VERSION 5.8 ;
BUSBITCHARS "[]" ;
DIVIDERCHAR "/" ;
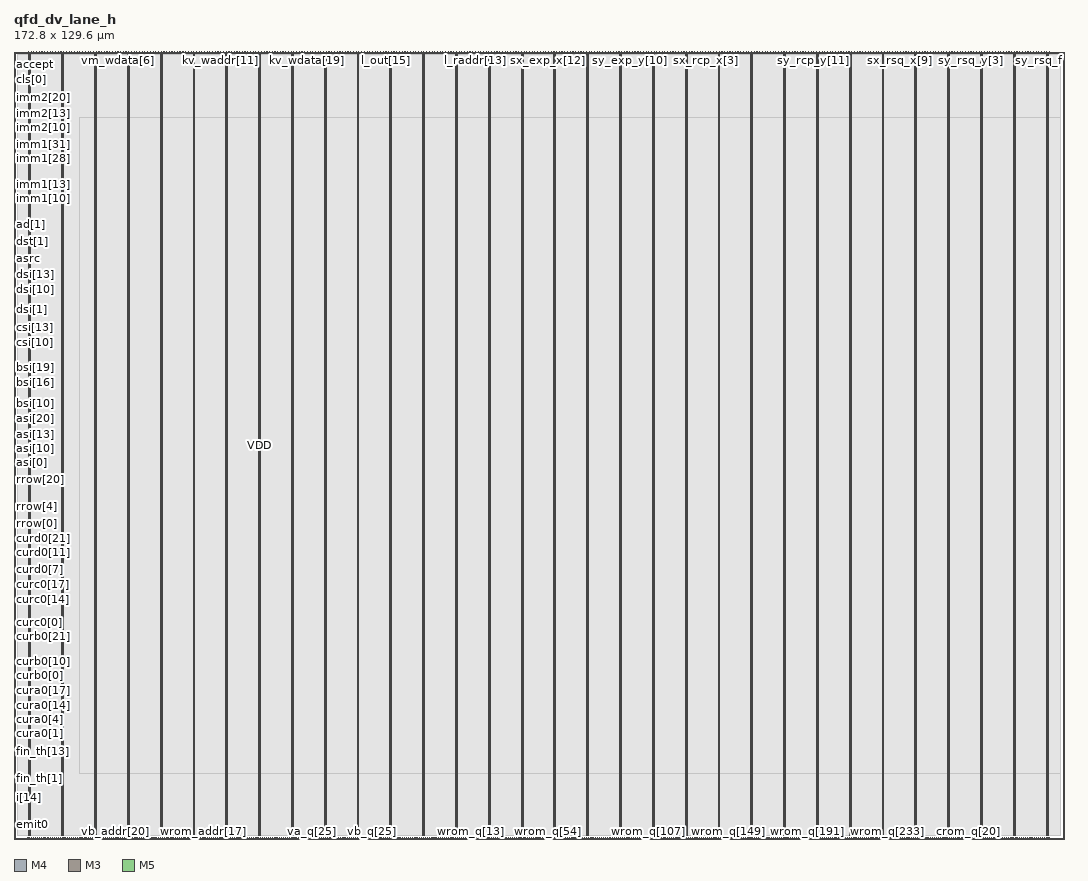
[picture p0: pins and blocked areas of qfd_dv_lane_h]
MACRO qfd_dv_lane_h
  CLASS BLOCK ;
  ORIGIN 0 0 ;
  FOREIGN qfd_dv_lane_h 0 0 ;
  SIZE 172.8 BY 129.6 ;
  SYMMETRY X Y ;
  PIN emit0
    DIRECTION INPUT ;
    USE SIGNAL ;
    PORT
      LAYER M4 ;
        RECT 0.000 2.352 0.192 2.376 ;
    END
  END emit0
  PIN live
    DIRECTION INPUT ;
    USE SIGNAL ;
    PORT
      LAYER M4 ;
        RECT 0.000 2.688 0.192 2.712 ;
    END
  END live
  PIN i[0]
    DIRECTION INPUT ;
    USE SIGNAL ;
    PORT
      LAYER M4 ;
        RECT 0.000 3.072 0.192 3.096 ;
    END
  END i[0]
  PIN i[1]
    DIRECTION INPUT ;
    USE SIGNAL ;
    PORT
      LAYER M4 ;
        RECT 0.000 3.408 0.192 3.432 ;
    END
  END i[1]
  PIN i[2]
    DIRECTION INPUT ;
    USE SIGNAL ;
    PORT
      LAYER M4 ;
        RECT 0.000 3.792 0.192 3.816 ;
    END
  END i[2]
  PIN i[3]
    DIRECTION INPUT ;
    USE SIGNAL ;
    PORT
      LAYER M4 ;
        RECT 0.000 4.128 0.192 4.152 ;
    END
  END i[3]
  PIN i[4]
    DIRECTION INPUT ;
    USE SIGNAL ;
    PORT
      LAYER M4 ;
        RECT 0.000 4.512 0.192 4.536 ;
    END
  END i[4]
  PIN i[5]
    DIRECTION INPUT ;
    USE SIGNAL ;
    PORT
      LAYER M4 ;
        RECT 0.000 4.896 0.192 4.920 ;
    END
  END i[5]
  PIN i[6]
    DIRECTION INPUT ;
    USE SIGNAL ;
    PORT
      LAYER M4 ;
        RECT 0.000 5.232 0.192 5.256 ;
    END
  END i[6]
  PIN i[7]
    DIRECTION INPUT ;
    USE SIGNAL ;
    PORT
      LAYER M4 ;
        RECT 0.000 5.616 0.192 5.640 ;
    END
  END i[7]
  PIN i[8]
    DIRECTION INPUT ;
    USE SIGNAL ;
    PORT
      LAYER M4 ;
        RECT 0.000 5.952 0.192 5.976 ;
    END
  END i[8]
  PIN i[9]
    DIRECTION INPUT ;
    USE SIGNAL ;
    PORT
      LAYER M4 ;
        RECT 0.000 6.336 0.192 6.360 ;
    END
  END i[9]
  PIN i[10]
    DIRECTION INPUT ;
    USE SIGNAL ;
    PORT
      LAYER M4 ;
        RECT 0.000 6.720 0.192 6.744 ;
    END
  END i[10]
  PIN i[11]
    DIRECTION INPUT ;
    USE SIGNAL ;
    PORT
      LAYER M4 ;
        RECT 0.000 7.056 0.192 7.080 ;
    END
  END i[11]
  PIN i[12]
    DIRECTION INPUT ;
    USE SIGNAL ;
    PORT
      LAYER M4 ;
        RECT 0.000 7.440 0.192 7.464 ;
    END
  END i[12]
  PIN i[13]
    DIRECTION INPUT ;
    USE SIGNAL ;
    PORT
      LAYER M4 ;
        RECT 0.000 7.776 0.192 7.800 ;
    END
  END i[13]
  PIN i[14]
    DIRECTION INPUT ;
    USE SIGNAL ;
    PORT
      LAYER M4 ;
        RECT 0.000 8.160 0.192 8.184 ;
    END
  END i[14]
  PIN i[15]
    DIRECTION INPUT ;
    USE SIGNAL ;
    PORT
      LAYER M4 ;
        RECT 0.000 8.544 0.192 8.568 ;
    END
  END i[15]
  PIN i[16]
    DIRECTION INPUT ;
    USE SIGNAL ;
    PORT
      LAYER M4 ;
        RECT 0.000 8.880 0.192 8.904 ;
    END
  END i[16]
  PIN i[17]
    DIRECTION INPUT ;
    USE SIGNAL ;
    PORT
      LAYER M4 ;
        RECT 0.000 9.264 0.192 9.288 ;
    END
  END i[17]
  PIN fin_th[0]
    DIRECTION INPUT ;
    USE SIGNAL ;
    PORT
      LAYER M4 ;
        RECT 0.000 9.600 0.192 9.624 ;
    END
  END fin_th[0]
  PIN fin_th[1]
    DIRECTION INPUT ;
    USE SIGNAL ;
    PORT
      LAYER M4 ;
        RECT 0.000 9.984 0.192 10.008 ;
    END
  END fin_th[1]
  PIN fin_th[2]
    DIRECTION INPUT ;
    USE SIGNAL ;
    PORT
      LAYER M4 ;
        RECT 0.000 10.320 0.192 10.344 ;
    END
  END fin_th[2]
  PIN fin_th[3]
    DIRECTION INPUT ;
    USE SIGNAL ;
    PORT
      LAYER M4 ;
        RECT 0.000 10.704 0.192 10.728 ;
    END
  END fin_th[3]
  PIN fin_th[4]
    DIRECTION INPUT ;
    USE SIGNAL ;
    PORT
      LAYER M4 ;
        RECT 0.000 11.088 0.192 11.112 ;
    END
  END fin_th[4]
  PIN fin_th[5]
    DIRECTION INPUT ;
    USE SIGNAL ;
    PORT
      LAYER M4 ;
        RECT 0.000 11.424 0.192 11.448 ;
    END
  END fin_th[5]
  PIN fin_th[6]
    DIRECTION INPUT ;
    USE SIGNAL ;
    PORT
      LAYER M4 ;
        RECT 0.000 11.808 0.192 11.832 ;
    END
  END fin_th[6]
  PIN fin_th[7]
    DIRECTION INPUT ;
    USE SIGNAL ;
    PORT
      LAYER M4 ;
        RECT 0.000 12.144 0.192 12.168 ;
    END
  END fin_th[7]
  PIN fin_th[8]
    DIRECTION INPUT ;
    USE SIGNAL ;
    PORT
      LAYER M4 ;
        RECT 0.000 12.528 0.192 12.552 ;
    END
  END fin_th[8]
  PIN fin_th[9]
    DIRECTION INPUT ;
    USE SIGNAL ;
    PORT
      LAYER M4 ;
        RECT 0.000 12.912 0.192 12.936 ;
    END
  END fin_th[9]
  PIN fin_th[10]
    DIRECTION INPUT ;
    USE SIGNAL ;
    PORT
      LAYER M4 ;
        RECT 0.000 13.248 0.192 13.272 ;
    END
  END fin_th[10]
  PIN fin_th[11]
    DIRECTION INPUT ;
    USE SIGNAL ;
    PORT
      LAYER M4 ;
        RECT 0.000 13.632 0.192 13.656 ;
    END
  END fin_th[11]
  PIN fin_th[12]
    DIRECTION INPUT ;
    USE SIGNAL ;
    PORT
      LAYER M4 ;
        RECT 0.000 13.968 0.192 13.992 ;
    END
  END fin_th[12]
  PIN fin_th[13]
    DIRECTION INPUT ;
    USE SIGNAL ;
    PORT
      LAYER M4 ;
        RECT 0.000 14.352 0.192 14.376 ;
    END
  END fin_th[13]
  PIN fin_th[14]
    DIRECTION INPUT ;
    USE SIGNAL ;
    PORT
      LAYER M4 ;
        RECT 0.000 14.736 0.192 14.760 ;
    END
  END fin_th[14]
  PIN fin_th[15]
    DIRECTION INPUT ;
    USE SIGNAL ;
    PORT
      LAYER M4 ;
        RECT 0.000 15.072 0.192 15.096 ;
    END
  END fin_th[15]
  PIN fin_th[16]
    DIRECTION INPUT ;
    USE SIGNAL ;
    PORT
      LAYER M4 ;
        RECT 0.000 15.456 0.192 15.480 ;
    END
  END fin_th[16]
  PIN fin_th[17]
    DIRECTION INPUT ;
    USE SIGNAL ;
    PORT
      LAYER M4 ;
        RECT 0.000 15.792 0.192 15.816 ;
    END
  END fin_th[17]
  PIN fin_th[18]
    DIRECTION INPUT ;
    USE SIGNAL ;
    PORT
      LAYER M4 ;
        RECT 0.000 16.176 0.192 16.200 ;
    END
  END fin_th[18]
  PIN i_last_r
    DIRECTION INPUT ;
    USE SIGNAL ;
    PORT
      LAYER M4 ;
        RECT 0.000 16.512 0.192 16.536 ;
    END
  END i_last_r
  PIN cura0[0]
    DIRECTION INPUT ;
    USE SIGNAL ;
    PORT
      LAYER M4 ;
        RECT 0.000 16.896 0.192 16.920 ;
    END
  END cura0[0]
  PIN cura0[1]
    DIRECTION INPUT ;
    USE SIGNAL ;
    PORT
      LAYER M4 ;
        RECT 0.000 17.280 0.192 17.304 ;
    END
  END cura0[1]
  PIN cura0[2]
    DIRECTION INPUT ;
    USE SIGNAL ;
    PORT
      LAYER M4 ;
        RECT 0.000 17.616 0.192 17.640 ;
    END
  END cura0[2]
  PIN cura0[3]
    DIRECTION INPUT ;
    USE SIGNAL ;
    PORT
      LAYER M4 ;
        RECT 0.000 18.000 0.192 18.024 ;
    END
  END cura0[3]
  PIN cura0[4]
    DIRECTION INPUT ;
    USE SIGNAL ;
    PORT
      LAYER M4 ;
        RECT 0.000 18.336 0.192 18.360 ;
    END
  END cura0[4]
  PIN cura0[5]
    DIRECTION INPUT ;
    USE SIGNAL ;
    PORT
      LAYER M4 ;
        RECT 0.000 18.720 0.192 18.744 ;
    END
  END cura0[5]
  PIN cura0[6]
    DIRECTION INPUT ;
    USE SIGNAL ;
    PORT
      LAYER M4 ;
        RECT 0.000 19.104 0.192 19.128 ;
    END
  END cura0[6]
  PIN cura0[7]
    DIRECTION INPUT ;
    USE SIGNAL ;
    PORT
      LAYER M4 ;
        RECT 0.000 19.440 0.192 19.464 ;
    END
  END cura0[7]
  PIN cura0[8]
    DIRECTION INPUT ;
    USE SIGNAL ;
    PORT
      LAYER M4 ;
        RECT 0.000 19.824 0.192 19.848 ;
    END
  END cura0[8]
  PIN cura0[9]
    DIRECTION INPUT ;
    USE SIGNAL ;
    PORT
      LAYER M4 ;
        RECT 0.000 20.160 0.192 20.184 ;
    END
  END cura0[9]
  PIN cura0[10]
    DIRECTION INPUT ;
    USE SIGNAL ;
    PORT
      LAYER M4 ;
        RECT 0.000 20.544 0.192 20.568 ;
    END
  END cura0[10]
  PIN cura0[11]
    DIRECTION INPUT ;
    USE SIGNAL ;
    PORT
      LAYER M4 ;
        RECT 0.000 20.880 0.192 20.904 ;
    END
  END cura0[11]
  PIN cura0[12]
    DIRECTION INPUT ;
    USE SIGNAL ;
    PORT
      LAYER M4 ;
        RECT 0.000 21.264 0.192 21.288 ;
    END
  END cura0[12]
  PIN cura0[13]
    DIRECTION INPUT ;
    USE SIGNAL ;
    PORT
      LAYER M4 ;
        RECT 0.000 21.648 0.192 21.672 ;
    END
  END cura0[13]
  PIN cura0[14]
    DIRECTION INPUT ;
    USE SIGNAL ;
    PORT
      LAYER M4 ;
        RECT 0.000 21.984 0.192 22.008 ;
    END
  END cura0[14]
  PIN cura0[15]
    DIRECTION INPUT ;
    USE SIGNAL ;
    PORT
      LAYER M4 ;
        RECT 0.000 22.368 0.192 22.392 ;
    END
  END cura0[15]
  PIN cura0[16]
    DIRECTION INPUT ;
    USE SIGNAL ;
    PORT
      LAYER M4 ;
        RECT 0.000 22.704 0.192 22.728 ;
    END
  END cura0[16]
  PIN cura0[17]
    DIRECTION INPUT ;
    USE SIGNAL ;
    PORT
      LAYER M4 ;
        RECT 0.000 23.088 0.192 23.112 ;
    END
  END cura0[17]
  PIN cura0[18]
    DIRECTION INPUT ;
    USE SIGNAL ;
    PORT
      LAYER M4 ;
        RECT 0.000 23.472 0.192 23.496 ;
    END
  END cura0[18]
  PIN cura0[19]
    DIRECTION INPUT ;
    USE SIGNAL ;
    PORT
      LAYER M4 ;
        RECT 0.000 23.808 0.192 23.832 ;
    END
  END cura0[19]
  PIN cura0[20]
    DIRECTION INPUT ;
    USE SIGNAL ;
    PORT
      LAYER M4 ;
        RECT 0.000 24.192 0.192 24.216 ;
    END
  END cura0[20]
  PIN cura0[21]
    DIRECTION INPUT ;
    USE SIGNAL ;
    PORT
      LAYER M4 ;
        RECT 0.000 24.528 0.192 24.552 ;
    END
  END cura0[21]
  PIN cura0[22]
    DIRECTION INPUT ;
    USE SIGNAL ;
    PORT
      LAYER M4 ;
        RECT 0.000 24.912 0.192 24.936 ;
    END
  END cura0[22]
  PIN cura0[23]
    DIRECTION INPUT ;
    USE SIGNAL ;
    PORT
      LAYER M4 ;
        RECT 0.000 25.296 0.192 25.320 ;
    END
  END cura0[23]
  PIN curb0[0]
    DIRECTION INPUT ;
    USE SIGNAL ;
    PORT
      LAYER M4 ;
        RECT 0.000 25.632 0.192 25.656 ;
    END
  END curb0[0]
  PIN curb0[1]
    DIRECTION INPUT ;
    USE SIGNAL ;
    PORT
      LAYER M4 ;
        RECT 0.000 26.016 0.192 26.040 ;
    END
  END curb0[1]
  PIN curb0[2]
    DIRECTION INPUT ;
    USE SIGNAL ;
    PORT
      LAYER M4 ;
        RECT 0.000 26.352 0.192 26.376 ;
    END
  END curb0[2]
  PIN curb0[3]
    DIRECTION INPUT ;
    USE SIGNAL ;
    PORT
      LAYER M4 ;
        RECT 0.000 26.736 0.192 26.760 ;
    END
  END curb0[3]
  PIN curb0[4]
    DIRECTION INPUT ;
    USE SIGNAL ;
    PORT
      LAYER M4 ;
        RECT 0.000 27.072 0.192 27.096 ;
    END
  END curb0[4]
  PIN curb0[5]
    DIRECTION INPUT ;
    USE SIGNAL ;
    PORT
      LAYER M4 ;
        RECT 0.000 27.456 0.192 27.480 ;
    END
  END curb0[5]
  PIN curb0[6]
    DIRECTION INPUT ;
    USE SIGNAL ;
    PORT
      LAYER M4 ;
        RECT 0.000 27.840 0.192 27.864 ;
    END
  END curb0[6]
  PIN curb0[7]
    DIRECTION INPUT ;
    USE SIGNAL ;
    PORT
      LAYER M4 ;
        RECT 0.000 28.176 0.192 28.200 ;
    END
  END curb0[7]
  PIN curb0[8]
    DIRECTION INPUT ;
    USE SIGNAL ;
    PORT
      LAYER M4 ;
        RECT 0.000 28.560 0.192 28.584 ;
    END
  END curb0[8]
  PIN curb0[9]
    DIRECTION INPUT ;
    USE SIGNAL ;
    PORT
      LAYER M4 ;
        RECT 0.000 28.896 0.192 28.920 ;
    END
  END curb0[9]
  PIN curb0[10]
    DIRECTION INPUT ;
    USE SIGNAL ;
    PORT
      LAYER M4 ;
        RECT 0.000 29.280 0.192 29.304 ;
    END
  END curb0[10]
  PIN curb0[11]
    DIRECTION INPUT ;
    USE SIGNAL ;
    PORT
      LAYER M4 ;
        RECT 0.000 29.664 0.192 29.688 ;
    END
  END curb0[11]
  PIN curb0[12]
    DIRECTION INPUT ;
    USE SIGNAL ;
    PORT
      LAYER M4 ;
        RECT 0.000 30.000 0.192 30.024 ;
    END
  END curb0[12]
  PIN curb0[13]
    DIRECTION INPUT ;
    USE SIGNAL ;
    PORT
      LAYER M4 ;
        RECT 0.000 30.384 0.192 30.408 ;
    END
  END curb0[13]
  PIN curb0[14]
    DIRECTION INPUT ;
    USE SIGNAL ;
    PORT
      LAYER M4 ;
        RECT 0.000 30.720 0.192 30.744 ;
    END
  END curb0[14]
  PIN curb0[15]
    DIRECTION INPUT ;
    USE SIGNAL ;
    PORT
      LAYER M4 ;
        RECT 0.000 31.104 0.192 31.128 ;
    END
  END curb0[15]
  PIN curb0[16]
    DIRECTION INPUT ;
    USE SIGNAL ;
    PORT
      LAYER M4 ;
        RECT 0.000 31.488 0.192 31.512 ;
    END
  END curb0[16]
  PIN curb0[17]
    DIRECTION INPUT ;
    USE SIGNAL ;
    PORT
      LAYER M4 ;
        RECT 0.000 31.824 0.192 31.848 ;
    END
  END curb0[17]
  PIN curb0[18]
    DIRECTION INPUT ;
    USE SIGNAL ;
    PORT
      LAYER M4 ;
        RECT 0.000 32.208 0.192 32.232 ;
    END
  END curb0[18]
  PIN curb0[19]
    DIRECTION INPUT ;
    USE SIGNAL ;
    PORT
      LAYER M4 ;
        RECT 0.000 32.544 0.192 32.568 ;
    END
  END curb0[19]
  PIN curb0[20]
    DIRECTION INPUT ;
    USE SIGNAL ;
    PORT
      LAYER M4 ;
        RECT 0.000 32.928 0.192 32.952 ;
    END
  END curb0[20]
  PIN curb0[21]
    DIRECTION INPUT ;
    USE SIGNAL ;
    PORT
      LAYER M4 ;
        RECT 0.000 33.264 0.192 33.288 ;
    END
  END curb0[21]
  PIN curb0[22]
    DIRECTION INPUT ;
    USE SIGNAL ;
    PORT
      LAYER M4 ;
        RECT 0.000 33.648 0.192 33.672 ;
    END
  END curb0[22]
  PIN curb0[23]
    DIRECTION INPUT ;
    USE SIGNAL ;
    PORT
      LAYER M4 ;
        RECT 0.000 34.032 0.192 34.056 ;
    END
  END curb0[23]
  PIN curc0[0]
    DIRECTION INPUT ;
    USE SIGNAL ;
    PORT
      LAYER M4 ;
        RECT 0.000 34.368 0.192 34.392 ;
    END
  END curc0[0]
  PIN curc0[1]
    DIRECTION INPUT ;
    USE SIGNAL ;
    PORT
      LAYER M4 ;
        RECT 0.000 34.752 0.192 34.776 ;
    END
  END curc0[1]
  PIN curc0[2]
    DIRECTION INPUT ;
    USE SIGNAL ;
    PORT
      LAYER M4 ;
        RECT 0.000 35.088 0.192 35.112 ;
    END
  END curc0[2]
  PIN curc0[3]
    DIRECTION INPUT ;
    USE SIGNAL ;
    PORT
      LAYER M4 ;
        RECT 0.000 35.472 0.192 35.496 ;
    END
  END curc0[3]
  PIN curc0[4]
    DIRECTION INPUT ;
    USE SIGNAL ;
    PORT
      LAYER M4 ;
        RECT 0.000 35.856 0.192 35.880 ;
    END
  END curc0[4]
  PIN curc0[5]
    DIRECTION INPUT ;
    USE SIGNAL ;
    PORT
      LAYER M4 ;
        RECT 0.000 36.192 0.192 36.216 ;
    END
  END curc0[5]
  PIN curc0[6]
    DIRECTION INPUT ;
    USE SIGNAL ;
    PORT
      LAYER M4 ;
        RECT 0.000 36.576 0.192 36.600 ;
    END
  END curc0[6]
  PIN curc0[7]
    DIRECTION INPUT ;
    USE SIGNAL ;
    PORT
      LAYER M4 ;
        RECT 0.000 36.912 0.192 36.936 ;
    END
  END curc0[7]
  PIN curc0[8]
    DIRECTION INPUT ;
    USE SIGNAL ;
    PORT
      LAYER M4 ;
        RECT 0.000 37.296 0.192 37.320 ;
    END
  END curc0[8]
  PIN curc0[9]
    DIRECTION INPUT ;
    USE SIGNAL ;
    PORT
      LAYER M4 ;
        RECT 0.000 37.680 0.192 37.704 ;
    END
  END curc0[9]
  PIN curc0[10]
    DIRECTION INPUT ;
    USE SIGNAL ;
    PORT
      LAYER M4 ;
        RECT 0.000 38.016 0.192 38.040 ;
    END
  END curc0[10]
  PIN curc0[11]
    DIRECTION INPUT ;
    USE SIGNAL ;
    PORT
      LAYER M4 ;
        RECT 0.000 38.400 0.192 38.424 ;
    END
  END curc0[11]
  PIN curc0[12]
    DIRECTION INPUT ;
    USE SIGNAL ;
    PORT
      LAYER M4 ;
        RECT 0.000 38.736 0.192 38.760 ;
    END
  END curc0[12]
  PIN curc0[13]
    DIRECTION INPUT ;
    USE SIGNAL ;
    PORT
      LAYER M4 ;
        RECT 0.000 39.120 0.192 39.144 ;
    END
  END curc0[13]
  PIN curc0[14]
    DIRECTION INPUT ;
    USE SIGNAL ;
    PORT
      LAYER M4 ;
        RECT 0.000 39.456 0.192 39.480 ;
    END
  END curc0[14]
  PIN curc0[15]
    DIRECTION INPUT ;
    USE SIGNAL ;
    PORT
      LAYER M4 ;
        RECT 0.000 39.840 0.192 39.864 ;
    END
  END curc0[15]
  PIN curc0[16]
    DIRECTION INPUT ;
    USE SIGNAL ;
    PORT
      LAYER M4 ;
        RECT 0.000 40.224 0.192 40.248 ;
    END
  END curc0[16]
  PIN curc0[17]
    DIRECTION INPUT ;
    USE SIGNAL ;
    PORT
      LAYER M4 ;
        RECT 0.000 40.560 0.192 40.584 ;
    END
  END curc0[17]
  PIN curc0[18]
    DIRECTION INPUT ;
    USE SIGNAL ;
    PORT
      LAYER M4 ;
        RECT 0.000 40.944 0.192 40.968 ;
    END
  END curc0[18]
  PIN curc0[19]
    DIRECTION INPUT ;
    USE SIGNAL ;
    PORT
      LAYER M4 ;
        RECT 0.000 41.280 0.192 41.304 ;
    END
  END curc0[19]
  PIN curc0[20]
    DIRECTION INPUT ;
    USE SIGNAL ;
    PORT
      LAYER M4 ;
        RECT 0.000 41.664 0.192 41.688 ;
    END
  END curc0[20]
  PIN curc0[21]
    DIRECTION INPUT ;
    USE SIGNAL ;
    PORT
      LAYER M4 ;
        RECT 0.000 42.048 0.192 42.072 ;
    END
  END curc0[21]
  PIN curc0[22]
    DIRECTION INPUT ;
    USE SIGNAL ;
    PORT
      LAYER M4 ;
        RECT 0.000 42.384 0.192 42.408 ;
    END
  END curc0[22]
  PIN curc0[23]
    DIRECTION INPUT ;
    USE SIGNAL ;
    PORT
      LAYER M4 ;
        RECT 0.000 42.768 0.192 42.792 ;
    END
  END curc0[23]
  PIN curd0[0]
    DIRECTION INPUT ;
    USE SIGNAL ;
    PORT
      LAYER M4 ;
        RECT 0.000 43.104 0.192 43.128 ;
    END
  END curd0[0]
  PIN curd0[1]
    DIRECTION INPUT ;
    USE SIGNAL ;
    PORT
      LAYER M4 ;
        RECT 0.000 43.488 0.192 43.512 ;
    END
  END curd0[1]
  PIN curd0[2]
    DIRECTION INPUT ;
    USE SIGNAL ;
    PORT
      LAYER M4 ;
        RECT 0.000 43.824 0.192 43.848 ;
    END
  END curd0[2]
  PIN curd0[3]
    DIRECTION INPUT ;
    USE SIGNAL ;
    PORT
      LAYER M4 ;
        RECT 0.000 44.208 0.192 44.232 ;
    END
  END curd0[3]
  PIN curd0[4]
    DIRECTION INPUT ;
    USE SIGNAL ;
    PORT
      LAYER M4 ;
        RECT 0.000 44.592 0.192 44.616 ;
    END
  END curd0[4]
  PIN curd0[5]
    DIRECTION INPUT ;
    USE SIGNAL ;
    PORT
      LAYER M4 ;
        RECT 0.000 44.928 0.192 44.952 ;
    END
  END curd0[5]
  PIN curd0[6]
    DIRECTION INPUT ;
    USE SIGNAL ;
    PORT
      LAYER M4 ;
        RECT 0.000 45.312 0.192 45.336 ;
    END
  END curd0[6]
  PIN curd0[7]
    DIRECTION INPUT ;
    USE SIGNAL ;
    PORT
      LAYER M4 ;
        RECT 0.000 45.648 0.192 45.672 ;
    END
  END curd0[7]
  PIN curd0[8]
    DIRECTION INPUT ;
    USE SIGNAL ;
    PORT
      LAYER M4 ;
        RECT 0.000 46.032 0.192 46.056 ;
    END
  END curd0[8]
  PIN curd0[9]
    DIRECTION INPUT ;
    USE SIGNAL ;
    PORT
      LAYER M4 ;
        RECT 0.000 46.416 0.192 46.440 ;
    END
  END curd0[9]
  PIN curd0[10]
    DIRECTION INPUT ;
    USE SIGNAL ;
    PORT
      LAYER M4 ;
        RECT 0.000 46.752 0.192 46.776 ;
    END
  END curd0[10]
  PIN curd0[11]
    DIRECTION INPUT ;
    USE SIGNAL ;
    PORT
      LAYER M4 ;
        RECT 0.000 47.136 0.192 47.160 ;
    END
  END curd0[11]
  PIN curd0[12]
    DIRECTION INPUT ;
    USE SIGNAL ;
    PORT
      LAYER M4 ;
        RECT 0.000 47.472 0.192 47.496 ;
    END
  END curd0[12]
  PIN curd0[13]
    DIRECTION INPUT ;
    USE SIGNAL ;
    PORT
      LAYER M4 ;
        RECT 0.000 47.856 0.192 47.880 ;
    END
  END curd0[13]
  PIN curd0[14]
    DIRECTION INPUT ;
    USE SIGNAL ;
    PORT
      LAYER M4 ;
        RECT 0.000 48.240 0.192 48.264 ;
    END
  END curd0[14]
  PIN curd0[15]
    DIRECTION INPUT ;
    USE SIGNAL ;
    PORT
      LAYER M4 ;
        RECT 0.000 48.576 0.192 48.600 ;
    END
  END curd0[15]
  PIN curd0[16]
    DIRECTION INPUT ;
    USE SIGNAL ;
    PORT
      LAYER M4 ;
        RECT 0.000 48.960 0.192 48.984 ;
    END
  END curd0[16]
  PIN curd0[17]
    DIRECTION INPUT ;
    USE SIGNAL ;
    PORT
      LAYER M4 ;
        RECT 0.000 49.296 0.192 49.320 ;
    END
  END curd0[17]
  PIN curd0[18]
    DIRECTION INPUT ;
    USE SIGNAL ;
    PORT
      LAYER M4 ;
        RECT 0.000 49.680 0.192 49.704 ;
    END
  END curd0[18]
  PIN curd0[19]
    DIRECTION INPUT ;
    USE SIGNAL ;
    PORT
      LAYER M4 ;
        RECT 0.000 50.016 0.192 50.040 ;
    END
  END curd0[19]
  PIN curd0[20]
    DIRECTION INPUT ;
    USE SIGNAL ;
    PORT
      LAYER M4 ;
        RECT 0.000 50.400 0.192 50.424 ;
    END
  END curd0[20]
  PIN curd0[21]
    DIRECTION INPUT ;
    USE SIGNAL ;
    PORT
      LAYER M4 ;
        RECT 0.000 50.784 0.192 50.808 ;
    END
  END curd0[21]
  PIN curd0[22]
    DIRECTION INPUT ;
    USE SIGNAL ;
    PORT
      LAYER M4 ;
        RECT 0.000 51.120 0.192 51.144 ;
    END
  END curd0[22]
  PIN curd0[23]
    DIRECTION INPUT ;
    USE SIGNAL ;
    PORT
      LAYER M4 ;
        RECT 0.000 51.504 0.192 51.528 ;
    END
  END curd0[23]
  PIN rrow[0]
    DIRECTION INPUT ;
    USE SIGNAL ;
    PORT
      LAYER M4 ;
        RECT 0.000 51.840 0.192 51.864 ;
    END
  END rrow[0]
  PIN rrow[1]
    DIRECTION INPUT ;
    USE SIGNAL ;
    PORT
      LAYER M4 ;
        RECT 0.000 52.224 0.192 52.248 ;
    END
  END rrow[1]
  PIN rrow[2]
    DIRECTION INPUT ;
    USE SIGNAL ;
    PORT
      LAYER M4 ;
        RECT 0.000 52.608 0.192 52.632 ;
    END
  END rrow[2]
  PIN rrow[3]
    DIRECTION INPUT ;
    USE SIGNAL ;
    PORT
      LAYER M4 ;
        RECT 0.000 52.944 0.192 52.968 ;
    END
  END rrow[3]
  PIN rrow[4]
    DIRECTION INPUT ;
    USE SIGNAL ;
    PORT
      LAYER M4 ;
        RECT 0.000 53.328 0.192 53.352 ;
    END
  END rrow[4]
  PIN rrow[5]
    DIRECTION INPUT ;
    USE SIGNAL ;
    PORT
      LAYER M4 ;
        RECT 0.000 53.664 0.192 53.688 ;
    END
  END rrow[5]
  PIN rrow[6]
    DIRECTION INPUT ;
    USE SIGNAL ;
    PORT
      LAYER M4 ;
        RECT 0.000 54.048 0.192 54.072 ;
    END
  END rrow[6]
  PIN rrow[7]
    DIRECTION INPUT ;
    USE SIGNAL ;
    PORT
      LAYER M4 ;
        RECT 0.000 54.432 0.192 54.456 ;
    END
  END rrow[7]
  PIN rrow[8]
    DIRECTION INPUT ;
    USE SIGNAL ;
    PORT
      LAYER M4 ;
        RECT 0.000 54.768 0.192 54.792 ;
    END
  END rrow[8]
  PIN rrow[9]
    DIRECTION INPUT ;
    USE SIGNAL ;
    PORT
      LAYER M4 ;
        RECT 0.000 55.152 0.192 55.176 ;
    END
  END rrow[9]
  PIN rrow[10]
    DIRECTION INPUT ;
    USE SIGNAL ;
    PORT
      LAYER M4 ;
        RECT 0.000 55.488 0.192 55.512 ;
    END
  END rrow[10]
  PIN rrow[11]
    DIRECTION INPUT ;
    USE SIGNAL ;
    PORT
      LAYER M4 ;
        RECT 0.000 55.872 0.192 55.896 ;
    END
  END rrow[11]
  PIN rrow[12]
    DIRECTION INPUT ;
    USE SIGNAL ;
    PORT
      LAYER M4 ;
        RECT 0.000 56.208 0.192 56.232 ;
    END
  END rrow[12]
  PIN rrow[13]
    DIRECTION INPUT ;
    USE SIGNAL ;
    PORT
      LAYER M4 ;
        RECT 0.000 56.592 0.192 56.616 ;
    END
  END rrow[13]
  PIN rrow[14]
    DIRECTION INPUT ;
    USE SIGNAL ;
    PORT
      LAYER M4 ;
        RECT 0.000 56.976 0.192 57.000 ;
    END
  END rrow[14]
  PIN rrow[15]
    DIRECTION INPUT ;
    USE SIGNAL ;
    PORT
      LAYER M4 ;
        RECT 0.000 57.312 0.192 57.336 ;
    END
  END rrow[15]
  PIN rrow[16]
    DIRECTION INPUT ;
    USE SIGNAL ;
    PORT
      LAYER M4 ;
        RECT 0.000 57.696 0.192 57.720 ;
    END
  END rrow[16]
  PIN rrow[17]
    DIRECTION INPUT ;
    USE SIGNAL ;
    PORT
      LAYER M4 ;
        RECT 0.000 58.032 0.192 58.056 ;
    END
  END rrow[17]
  PIN rrow[18]
    DIRECTION INPUT ;
    USE SIGNAL ;
    PORT
      LAYER M4 ;
        RECT 0.000 58.416 0.192 58.440 ;
    END
  END rrow[18]
  PIN rrow[19]
    DIRECTION INPUT ;
    USE SIGNAL ;
    PORT
      LAYER M4 ;
        RECT 0.000 58.800 0.192 58.824 ;
    END
  END rrow[19]
  PIN rrow[20]
    DIRECTION INPUT ;
    USE SIGNAL ;
    PORT
      LAYER M4 ;
        RECT 0.000 59.136 0.192 59.160 ;
    END
  END rrow[20]
  PIN rrow[21]
    DIRECTION INPUT ;
    USE SIGNAL ;
    PORT
      LAYER M4 ;
        RECT 0.000 59.520 0.192 59.544 ;
    END
  END rrow[21]
  PIN rrow[22]
    DIRECTION INPUT ;
    USE SIGNAL ;
    PORT
      LAYER M4 ;
        RECT 0.000 59.856 0.192 59.880 ;
    END
  END rrow[22]
  PIN rrow[23]
    DIRECTION INPUT ;
    USE SIGNAL ;
    PORT
      LAYER M4 ;
        RECT 0.000 60.240 0.192 60.264 ;
    END
  END rrow[23]
  PIN asi[0]
    DIRECTION INPUT ;
    USE SIGNAL ;
    PORT
      LAYER M4 ;
        RECT 0.000 60.576 0.192 60.600 ;
    END
  END asi[0]
  PIN asi[1]
    DIRECTION INPUT ;
    USE SIGNAL ;
    PORT
      LAYER M4 ;
        RECT 0.000 60.960 0.192 60.984 ;
    END
  END asi[1]
  PIN asi[2]
    DIRECTION INPUT ;
    USE SIGNAL ;
    PORT
      LAYER M4 ;
        RECT 0.000 61.344 0.192 61.368 ;
    END
  END asi[2]
  PIN asi[3]
    DIRECTION INPUT ;
    USE SIGNAL ;
    PORT
      LAYER M4 ;
        RECT 0.000 61.680 0.192 61.704 ;
    END
  END asi[3]
  PIN asi[4]
    DIRECTION INPUT ;
    USE SIGNAL ;
    PORT
      LAYER M4 ;
        RECT 0.000 62.064 0.192 62.088 ;
    END
  END asi[4]
  PIN asi[5]
    DIRECTION INPUT ;
    USE SIGNAL ;
    PORT
      LAYER M4 ;
        RECT 0.000 62.400 0.192 62.424 ;
    END
  END asi[5]
  PIN asi[6]
    DIRECTION INPUT ;
    USE SIGNAL ;
    PORT
      LAYER M4 ;
        RECT 0.000 62.784 0.192 62.808 ;
    END
  END asi[6]
  PIN asi[7]
    DIRECTION INPUT ;
    USE SIGNAL ;
    PORT
      LAYER M4 ;
        RECT 0.000 63.168 0.192 63.192 ;
    END
  END asi[7]
  PIN asi[8]
    DIRECTION INPUT ;
    USE SIGNAL ;
    PORT
      LAYER M4 ;
        RECT 0.000 63.504 0.192 63.528 ;
    END
  END asi[8]
  PIN asi[9]
    DIRECTION INPUT ;
    USE SIGNAL ;
    PORT
      LAYER M4 ;
        RECT 0.000 63.888 0.192 63.912 ;
    END
  END asi[9]
  PIN asi[10]
    DIRECTION INPUT ;
    USE SIGNAL ;
    PORT
      LAYER M4 ;
        RECT 0.000 64.224 0.192 64.248 ;
    END
  END asi[10]
  PIN asi[11]
    DIRECTION INPUT ;
    USE SIGNAL ;
    PORT
      LAYER M4 ;
        RECT 0.000 64.608 0.192 64.632 ;
    END
  END asi[11]
  PIN asi[12]
    DIRECTION INPUT ;
    USE SIGNAL ;
    PORT
      LAYER M4 ;
        RECT 0.000 64.992 0.192 65.016 ;
    END
  END asi[12]
  PIN asi[13]
    DIRECTION INPUT ;
    USE SIGNAL ;
    PORT
      LAYER M4 ;
        RECT 0.000 65.328 0.192 65.352 ;
    END
  END asi[13]
  PIN asi[14]
    DIRECTION INPUT ;
    USE SIGNAL ;
    PORT
      LAYER M4 ;
        RECT 0.000 65.712 0.192 65.736 ;
    END
  END asi[14]
  PIN asi[15]
    DIRECTION INPUT ;
    USE SIGNAL ;
    PORT
      LAYER M4 ;
        RECT 0.000 66.048 0.192 66.072 ;
    END
  END asi[15]
  PIN asi[16]
    DIRECTION INPUT ;
    USE SIGNAL ;
    PORT
      LAYER M4 ;
        RECT 0.000 66.432 0.192 66.456 ;
    END
  END asi[16]
  PIN asi[17]
    DIRECTION INPUT ;
    USE SIGNAL ;
    PORT
      LAYER M4 ;
        RECT 0.000 66.768 0.192 66.792 ;
    END
  END asi[17]
  PIN asi[18]
    DIRECTION INPUT ;
    USE SIGNAL ;
    PORT
      LAYER M4 ;
        RECT 0.000 67.152 0.192 67.176 ;
    END
  END asi[18]
  PIN asi[19]
    DIRECTION INPUT ;
    USE SIGNAL ;
    PORT
      LAYER M4 ;
        RECT 0.000 67.536 0.192 67.560 ;
    END
  END asi[19]
  PIN asi[20]
    DIRECTION INPUT ;
    USE SIGNAL ;
    PORT
      LAYER M4 ;
        RECT 0.000 67.872 0.192 67.896 ;
    END
  END asi[20]
  PIN asi[21]
    DIRECTION INPUT ;
    USE SIGNAL ;
    PORT
      LAYER M4 ;
        RECT 0.000 68.256 0.192 68.280 ;
    END
  END asi[21]
  PIN asi[22]
    DIRECTION INPUT ;
    USE SIGNAL ;
    PORT
      LAYER M4 ;
        RECT 0.000 68.592 0.192 68.616 ;
    END
  END asi[22]
  PIN asi[23]
    DIRECTION INPUT ;
    USE SIGNAL ;
    PORT
      LAYER M4 ;
        RECT 0.000 68.976 0.192 69.000 ;
    END
  END asi[23]
  PIN bsi[0]
    DIRECTION INPUT ;
    USE SIGNAL ;
    PORT
      LAYER M4 ;
        RECT 0.000 69.360 0.192 69.384 ;
    END
  END bsi[0]
  PIN bsi[1]
    DIRECTION INPUT ;
    USE SIGNAL ;
    PORT
      LAYER M4 ;
        RECT 0.000 69.696 0.192 69.720 ;
    END
  END bsi[1]
  PIN bsi[2]
    DIRECTION INPUT ;
    USE SIGNAL ;
    PORT
      LAYER M4 ;
        RECT 0.000 70.080 0.192 70.104 ;
    END
  END bsi[2]
  PIN bsi[3]
    DIRECTION INPUT ;
    USE SIGNAL ;
    PORT
      LAYER M4 ;
        RECT 0.000 70.416 0.192 70.440 ;
    END
  END bsi[3]
  PIN bsi[4]
    DIRECTION INPUT ;
    USE SIGNAL ;
    PORT
      LAYER M4 ;
        RECT 0.000 70.800 0.192 70.824 ;
    END
  END bsi[4]
  PIN bsi[5]
    DIRECTION INPUT ;
    USE SIGNAL ;
    PORT
      LAYER M4 ;
        RECT 0.000 71.184 0.192 71.208 ;
    END
  END bsi[5]
  PIN bsi[6]
    DIRECTION INPUT ;
    USE SIGNAL ;
    PORT
      LAYER M4 ;
        RECT 0.000 71.520 0.192 71.544 ;
    END
  END bsi[6]
  PIN bsi[7]
    DIRECTION INPUT ;
    USE SIGNAL ;
    PORT
      LAYER M4 ;
        RECT 0.000 71.904 0.192 71.928 ;
    END
  END bsi[7]
  PIN bsi[8]
    DIRECTION INPUT ;
    USE SIGNAL ;
    PORT
      LAYER M4 ;
        RECT 0.000 72.240 0.192 72.264 ;
    END
  END bsi[8]
  PIN bsi[9]
    DIRECTION INPUT ;
    USE SIGNAL ;
    PORT
      LAYER M4 ;
        RECT 0.000 72.624 0.192 72.648 ;
    END
  END bsi[9]
  PIN bsi[10]
    DIRECTION INPUT ;
    USE SIGNAL ;
    PORT
      LAYER M4 ;
        RECT 0.000 72.960 0.192 72.984 ;
    END
  END bsi[10]
  PIN bsi[11]
    DIRECTION INPUT ;
    USE SIGNAL ;
    PORT
      LAYER M4 ;
        RECT 0.000 73.344 0.192 73.368 ;
    END
  END bsi[11]
  PIN bsi[12]
    DIRECTION INPUT ;
    USE SIGNAL ;
    PORT
      LAYER M4 ;
        RECT 0.000 73.728 0.192 73.752 ;
    END
  END bsi[12]
  PIN bsi[13]
    DIRECTION INPUT ;
    USE SIGNAL ;
    PORT
      LAYER M4 ;
        RECT 0.000 74.064 0.192 74.088 ;
    END
  END bsi[13]
  PIN bsi[14]
    DIRECTION INPUT ;
    USE SIGNAL ;
    PORT
      LAYER M4 ;
        RECT 0.000 74.448 0.192 74.472 ;
    END
  END bsi[14]
  PIN bsi[15]
    DIRECTION INPUT ;
    USE SIGNAL ;
    PORT
      LAYER M4 ;
        RECT 0.000 74.784 0.192 74.808 ;
    END
  END bsi[15]
  PIN bsi[16]
    DIRECTION INPUT ;
    USE SIGNAL ;
    PORT
      LAYER M4 ;
        RECT 0.000 75.168 0.192 75.192 ;
    END
  END bsi[16]
  PIN bsi[17]
    DIRECTION INPUT ;
    USE SIGNAL ;
    PORT
      LAYER M4 ;
        RECT 0.000 75.552 0.192 75.576 ;
    END
  END bsi[17]
  PIN bsi[18]
    DIRECTION INPUT ;
    USE SIGNAL ;
    PORT
      LAYER M4 ;
        RECT 0.000 75.888 0.192 75.912 ;
    END
  END bsi[18]
  PIN bsi[19]
    DIRECTION INPUT ;
    USE SIGNAL ;
    PORT
      LAYER M4 ;
        RECT 0.000 76.272 0.192 76.296 ;
    END
  END bsi[19]
  PIN bsi[20]
    DIRECTION INPUT ;
    USE SIGNAL ;
    PORT
      LAYER M4 ;
        RECT 0.000 76.608 0.192 76.632 ;
    END
  END bsi[20]
  PIN bsi[21]
    DIRECTION INPUT ;
    USE SIGNAL ;
    PORT
      LAYER M4 ;
        RECT 0.000 76.992 0.192 77.016 ;
    END
  END bsi[21]
  PIN bsi[22]
    DIRECTION INPUT ;
    USE SIGNAL ;
    PORT
      LAYER M4 ;
        RECT 0.000 77.376 0.192 77.400 ;
    END
  END bsi[22]
  PIN bsi[23]
    DIRECTION INPUT ;
    USE SIGNAL ;
    PORT
      LAYER M4 ;
        RECT 0.000 77.712 0.192 77.736 ;
    END
  END bsi[23]
  PIN csi[0]
    DIRECTION INPUT ;
    USE SIGNAL ;
    PORT
      LAYER M4 ;
        RECT 0.000 78.096 0.192 78.120 ;
    END
  END csi[0]
  PIN csi[1]
    DIRECTION INPUT ;
    USE SIGNAL ;
    PORT
      LAYER M4 ;
        RECT 0.000 78.432 0.192 78.456 ;
    END
  END csi[1]
  PIN csi[2]
    DIRECTION INPUT ;
    USE SIGNAL ;
    PORT
      LAYER M4 ;
        RECT 0.000 78.816 0.192 78.840 ;
    END
  END csi[2]
  PIN csi[3]
    DIRECTION INPUT ;
    USE SIGNAL ;
    PORT
      LAYER M4 ;
        RECT 0.000 79.152 0.192 79.176 ;
    END
  END csi[3]
  PIN csi[4]
    DIRECTION INPUT ;
    USE SIGNAL ;
    PORT
      LAYER M4 ;
        RECT 0.000 79.536 0.192 79.560 ;
    END
  END csi[4]
  PIN csi[5]
    DIRECTION INPUT ;
    USE SIGNAL ;
    PORT
      LAYER M4 ;
        RECT 0.000 79.920 0.192 79.944 ;
    END
  END csi[5]
  PIN csi[6]
    DIRECTION INPUT ;
    USE SIGNAL ;
    PORT
      LAYER M4 ;
        RECT 0.000 80.256 0.192 80.280 ;
    END
  END csi[6]
  PIN csi[7]
    DIRECTION INPUT ;
    USE SIGNAL ;
    PORT
      LAYER M4 ;
        RECT 0.000 80.640 0.192 80.664 ;
    END
  END csi[7]
  PIN csi[8]
    DIRECTION INPUT ;
    USE SIGNAL ;
    PORT
      LAYER M4 ;
        RECT 0.000 80.976 0.192 81.000 ;
    END
  END csi[8]
  PIN csi[9]
    DIRECTION INPUT ;
    USE SIGNAL ;
    PORT
      LAYER M4 ;
        RECT 0.000 81.360 0.192 81.384 ;
    END
  END csi[9]
  PIN csi[10]
    DIRECTION INPUT ;
    USE SIGNAL ;
    PORT
      LAYER M4 ;
        RECT 0.000 81.744 0.192 81.768 ;
    END
  END csi[10]
  PIN csi[11]
    DIRECTION INPUT ;
    USE SIGNAL ;
    PORT
      LAYER M4 ;
        RECT 0.000 82.080 0.192 82.104 ;
    END
  END csi[11]
  PIN csi[12]
    DIRECTION INPUT ;
    USE SIGNAL ;
    PORT
      LAYER M4 ;
        RECT 0.000 82.464 0.192 82.488 ;
    END
  END csi[12]
  PIN csi[13]
    DIRECTION INPUT ;
    USE SIGNAL ;
    PORT
      LAYER M4 ;
        RECT 0.000 82.800 0.192 82.824 ;
    END
  END csi[13]
  PIN csi[14]
    DIRECTION INPUT ;
    USE SIGNAL ;
    PORT
      LAYER M4 ;
        RECT 0.000 83.184 0.192 83.208 ;
    END
  END csi[14]
  PIN csi[15]
    DIRECTION INPUT ;
    USE SIGNAL ;
    PORT
      LAYER M4 ;
        RECT 0.000 83.520 0.192 83.544 ;
    END
  END csi[15]
  PIN csi[16]
    DIRECTION INPUT ;
    USE SIGNAL ;
    PORT
      LAYER M4 ;
        RECT 0.000 83.904 0.192 83.928 ;
    END
  END csi[16]
  PIN csi[17]
    DIRECTION INPUT ;
    USE SIGNAL ;
    PORT
      LAYER M4 ;
        RECT 0.000 84.288 0.192 84.312 ;
    END
  END csi[17]
  PIN csi[18]
    DIRECTION INPUT ;
    USE SIGNAL ;
    PORT
      LAYER M4 ;
        RECT 0.000 84.624 0.192 84.648 ;
    END
  END csi[18]
  PIN csi[19]
    DIRECTION INPUT ;
    USE SIGNAL ;
    PORT
      LAYER M4 ;
        RECT 0.000 85.008 0.192 85.032 ;
    END
  END csi[19]
  PIN csi[20]
    DIRECTION INPUT ;
    USE SIGNAL ;
    PORT
      LAYER M4 ;
        RECT 0.000 85.344 0.192 85.368 ;
    END
  END csi[20]
  PIN csi[21]
    DIRECTION INPUT ;
    USE SIGNAL ;
    PORT
      LAYER M4 ;
        RECT 0.000 85.728 0.192 85.752 ;
    END
  END csi[21]
  PIN csi[22]
    DIRECTION INPUT ;
    USE SIGNAL ;
    PORT
      LAYER M4 ;
        RECT 0.000 86.112 0.192 86.136 ;
    END
  END csi[22]
  PIN csi[23]
    DIRECTION INPUT ;
    USE SIGNAL ;
    PORT
      LAYER M4 ;
        RECT 0.000 86.448 0.192 86.472 ;
    END
  END csi[23]
  PIN dsi[0]
    DIRECTION INPUT ;
    USE SIGNAL ;
    PORT
      LAYER M4 ;
        RECT 0.000 86.832 0.192 86.856 ;
    END
  END dsi[0]
  PIN dsi[1]
    DIRECTION INPUT ;
    USE SIGNAL ;
    PORT
      LAYER M4 ;
        RECT 0.000 87.168 0.192 87.192 ;
    END
  END dsi[1]
  PIN dsi[2]
    DIRECTION INPUT ;
    USE SIGNAL ;
    PORT
      LAYER M4 ;
        RECT 0.000 87.552 0.192 87.576 ;
    END
  END dsi[2]
  PIN dsi[3]
    DIRECTION INPUT ;
    USE SIGNAL ;
    PORT
      LAYER M4 ;
        RECT 0.000 87.936 0.192 87.960 ;
    END
  END dsi[3]
  PIN dsi[4]
    DIRECTION INPUT ;
    USE SIGNAL ;
    PORT
      LAYER M4 ;
        RECT 0.000 88.272 0.192 88.296 ;
    END
  END dsi[4]
  PIN dsi[5]
    DIRECTION INPUT ;
    USE SIGNAL ;
    PORT
      LAYER M4 ;
        RECT 0.000 88.656 0.192 88.680 ;
    END
  END dsi[5]
  PIN dsi[6]
    DIRECTION INPUT ;
    USE SIGNAL ;
    PORT
      LAYER M4 ;
        RECT 0.000 88.992 0.192 89.016 ;
    END
  END dsi[6]
  PIN dsi[7]
    DIRECTION INPUT ;
    USE SIGNAL ;
    PORT
      LAYER M4 ;
        RECT 0.000 89.376 0.192 89.400 ;
    END
  END dsi[7]
  PIN dsi[8]
    DIRECTION INPUT ;
    USE SIGNAL ;
    PORT
      LAYER M4 ;
        RECT 0.000 89.712 0.192 89.736 ;
    END
  END dsi[8]
  PIN dsi[9]
    DIRECTION INPUT ;
    USE SIGNAL ;
    PORT
      LAYER M4 ;
        RECT 0.000 90.096 0.192 90.120 ;
    END
  END dsi[9]
  PIN dsi[10]
    DIRECTION INPUT ;
    USE SIGNAL ;
    PORT
      LAYER M4 ;
        RECT 0.000 90.480 0.192 90.504 ;
    END
  END dsi[10]
  PIN dsi[11]
    DIRECTION INPUT ;
    USE SIGNAL ;
    PORT
      LAYER M4 ;
        RECT 0.000 90.816 0.192 90.840 ;
    END
  END dsi[11]
  PIN dsi[12]
    DIRECTION INPUT ;
    USE SIGNAL ;
    PORT
      LAYER M4 ;
        RECT 0.000 91.200 0.192 91.224 ;
    END
  END dsi[12]
  PIN dsi[13]
    DIRECTION INPUT ;
    USE SIGNAL ;
    PORT
      LAYER M4 ;
        RECT 0.000 91.536 0.192 91.560 ;
    END
  END dsi[13]
  PIN dsi[14]
    DIRECTION INPUT ;
    USE SIGNAL ;
    PORT
      LAYER M4 ;
        RECT 0.000 91.920 0.192 91.944 ;
    END
  END dsi[14]
  PIN dsi[15]
    DIRECTION INPUT ;
    USE SIGNAL ;
    PORT
      LAYER M4 ;
        RECT 0.000 92.304 0.192 92.328 ;
    END
  END dsi[15]
  PIN dsi[16]
    DIRECTION INPUT ;
    USE SIGNAL ;
    PORT
      LAYER M4 ;
        RECT 0.000 92.640 0.192 92.664 ;
    END
  END dsi[16]
  PIN dsi[17]
    DIRECTION INPUT ;
    USE SIGNAL ;
    PORT
      LAYER M4 ;
        RECT 0.000 93.024 0.192 93.048 ;
    END
  END dsi[17]
  PIN dsi[18]
    DIRECTION INPUT ;
    USE SIGNAL ;
    PORT
      LAYER M4 ;
        RECT 0.000 93.360 0.192 93.384 ;
    END
  END dsi[18]
  PIN dsi[19]
    DIRECTION INPUT ;
    USE SIGNAL ;
    PORT
      LAYER M4 ;
        RECT 0.000 93.744 0.192 93.768 ;
    END
  END dsi[19]
  PIN dsi[20]
    DIRECTION INPUT ;
    USE SIGNAL ;
    PORT
      LAYER M4 ;
        RECT 0.000 94.128 0.192 94.152 ;
    END
  END dsi[20]
  PIN dsi[21]
    DIRECTION INPUT ;
    USE SIGNAL ;
    PORT
      LAYER M4 ;
        RECT 0.000 94.464 0.192 94.488 ;
    END
  END dsi[21]
  PIN dsi[22]
    DIRECTION INPUT ;
    USE SIGNAL ;
    PORT
      LAYER M4 ;
        RECT 0.000 94.848 0.192 94.872 ;
    END
  END dsi[22]
  PIN dsi[23]
    DIRECTION INPUT ;
    USE SIGNAL ;
    PORT
      LAYER M4 ;
        RECT 0.000 95.184 0.192 95.208 ;
    END
  END dsi[23]
  PIN asrc
    DIRECTION INPUT ;
    USE SIGNAL ;
    PORT
      LAYER M4 ;
        RECT 0.000 95.568 0.192 95.592 ;
    END
  END asrc
  PIN bsrc
    DIRECTION INPUT ;
    USE SIGNAL ;
    PORT
      LAYER M4 ;
        RECT 0.000 95.904 0.192 95.928 ;
    END
  END bsrc
  PIN csrc
    DIRECTION INPUT ;
    USE SIGNAL ;
    PORT
      LAYER M4 ;
        RECT 0.000 96.288 0.192 96.312 ;
    END
  END csrc
  PIN mc
    DIRECTION INPUT ;
    USE SIGNAL ;
    PORT
      LAYER M4 ;
        RECT 0.000 96.672 0.192 96.696 ;
    END
  END mc
  PIN md
    DIRECTION INPUT ;
    USE SIGNAL ;
    PORT
      LAYER M4 ;
        RECT 0.000 97.008 0.192 97.032 ;
    END
  END md
  PIN redsq
    DIRECTION INPUT ;
    USE SIGNAL ;
    PORT
      LAYER M4 ;
        RECT 0.000 97.392 0.192 97.416 ;
    END
  END redsq
  PIN ma[0]
    DIRECTION INPUT ;
    USE SIGNAL ;
    PORT
      LAYER M4 ;
        RECT 0.000 97.728 0.192 97.752 ;
    END
  END ma[0]
  PIN ma[1]
    DIRECTION INPUT ;
    USE SIGNAL ;
    PORT
      LAYER M4 ;
        RECT 0.000 98.112 0.192 98.136 ;
    END
  END ma[1]
  PIN mb[0]
    DIRECTION INPUT ;
    USE SIGNAL ;
    PORT
      LAYER M4 ;
        RECT 0.000 98.496 0.192 98.520 ;
    END
  END mb[0]
  PIN mb[1]
    DIRECTION INPUT ;
    USE SIGNAL ;
    PORT
      LAYER M4 ;
        RECT 0.000 98.832 0.192 98.856 ;
    END
  END mb[1]
  PIN dst[0]
    DIRECTION INPUT ;
    USE SIGNAL ;
    PORT
      LAYER M4 ;
        RECT 0.000 99.216 0.192 99.240 ;
    END
  END dst[0]
  PIN dst[1]
    DIRECTION INPUT ;
    USE SIGNAL ;
    PORT
      LAYER M4 ;
        RECT 0.000 99.552 0.192 99.576 ;
    END
  END dst[1]
  PIN red[0]
    DIRECTION INPUT ;
    USE SIGNAL ;
    PORT
      LAYER M4 ;
        RECT 0.000 99.936 0.192 99.960 ;
    END
  END red[0]
  PIN red[1]
    DIRECTION INPUT ;
    USE SIGNAL ;
    PORT
      LAYER M4 ;
        RECT 0.000 100.320 0.192 100.344 ;
    END
  END red[1]
  PIN ad[0]
    DIRECTION INPUT ;
    USE SIGNAL ;
    PORT
      LAYER M4 ;
        RECT 0.000 100.656 0.192 100.680 ;
    END
  END ad[0]
  PIN ad[1]
    DIRECTION INPUT ;
    USE SIGNAL ;
    PORT
      LAYER M4 ;
        RECT 0.000 101.040 0.192 101.064 ;
    END
  END ad[1]
  PIN ad[2]
    DIRECTION INPUT ;
    USE SIGNAL ;
    PORT
      LAYER M4 ;
        RECT 0.000 101.376 0.192 101.400 ;
    END
  END ad[2]
  PIN imm1[0]
    DIRECTION INPUT ;
    USE SIGNAL ;
    PORT
      LAYER M4 ;
        RECT 0.000 101.760 0.192 101.784 ;
    END
  END imm1[0]
  PIN imm1[1]
    DIRECTION INPUT ;
    USE SIGNAL ;
    PORT
      LAYER M4 ;
        RECT 0.000 102.096 0.192 102.120 ;
    END
  END imm1[1]
  PIN imm1[2]
    DIRECTION INPUT ;
    USE SIGNAL ;
    PORT
      LAYER M4 ;
        RECT 0.000 102.480 0.192 102.504 ;
    END
  END imm1[2]
  PIN imm1[3]
    DIRECTION INPUT ;
    USE SIGNAL ;
    PORT
      LAYER M4 ;
        RECT 0.000 102.864 0.192 102.888 ;
    END
  END imm1[3]
  PIN imm1[4]
    DIRECTION INPUT ;
    USE SIGNAL ;
    PORT
      LAYER M4 ;
        RECT 0.000 103.200 0.192 103.224 ;
    END
  END imm1[4]
  PIN imm1[5]
    DIRECTION INPUT ;
    USE SIGNAL ;
    PORT
      LAYER M4 ;
        RECT 0.000 103.584 0.192 103.608 ;
    END
  END imm1[5]
  PIN imm1[6]
    DIRECTION INPUT ;
    USE SIGNAL ;
    PORT
      LAYER M4 ;
        RECT 0.000 103.920 0.192 103.944 ;
    END
  END imm1[6]
  PIN imm1[7]
    DIRECTION INPUT ;
    USE SIGNAL ;
    PORT
      LAYER M4 ;
        RECT 0.000 104.304 0.192 104.328 ;
    END
  END imm1[7]
  PIN imm1[8]
    DIRECTION INPUT ;
    USE SIGNAL ;
    PORT
      LAYER M4 ;
        RECT 0.000 104.688 0.192 104.712 ;
    END
  END imm1[8]
  PIN imm1[9]
    DIRECTION INPUT ;
    USE SIGNAL ;
    PORT
      LAYER M4 ;
        RECT 0.000 105.024 0.192 105.048 ;
    END
  END imm1[9]
  PIN imm1[10]
    DIRECTION INPUT ;
    USE SIGNAL ;
    PORT
      LAYER M4 ;
        RECT 0.000 105.408 0.192 105.432 ;
    END
  END imm1[10]
  PIN imm1[11]
    DIRECTION INPUT ;
    USE SIGNAL ;
    PORT
      LAYER M4 ;
        RECT 0.000 105.744 0.192 105.768 ;
    END
  END imm1[11]
  PIN imm1[12]
    DIRECTION INPUT ;
    USE SIGNAL ;
    PORT
      LAYER M4 ;
        RECT 0.000 106.128 0.192 106.152 ;
    END
  END imm1[12]
  PIN imm1[13]
    DIRECTION INPUT ;
    USE SIGNAL ;
    PORT
      LAYER M4 ;
        RECT 0.000 106.464 0.192 106.488 ;
    END
  END imm1[13]
  PIN imm1[14]
    DIRECTION INPUT ;
    USE SIGNAL ;
    PORT
      LAYER M4 ;
        RECT 0.000 106.848 0.192 106.872 ;
    END
  END imm1[14]
  PIN imm1[15]
    DIRECTION INPUT ;
    USE SIGNAL ;
    PORT
      LAYER M4 ;
        RECT 0.000 107.232 0.192 107.256 ;
    END
  END imm1[15]
  PIN imm1[16]
    DIRECTION INPUT ;
    USE SIGNAL ;
    PORT
      LAYER M4 ;
        RECT 0.000 107.568 0.192 107.592 ;
    END
  END imm1[16]
  PIN imm1[17]
    DIRECTION INPUT ;
    USE SIGNAL ;
    PORT
      LAYER M4 ;
        RECT 0.000 107.952 0.192 107.976 ;
    END
  END imm1[17]
  PIN imm1[18]
    DIRECTION INPUT ;
    USE SIGNAL ;
    PORT
      LAYER M4 ;
        RECT 0.000 108.288 0.192 108.312 ;
    END
  END imm1[18]
  PIN imm1[19]
    DIRECTION INPUT ;
    USE SIGNAL ;
    PORT
      LAYER M4 ;
        RECT 0.000 108.672 0.192 108.696 ;
    END
  END imm1[19]
  PIN imm1[20]
    DIRECTION INPUT ;
    USE SIGNAL ;
    PORT
      LAYER M4 ;
        RECT 0.000 109.056 0.192 109.080 ;
    END
  END imm1[20]
  PIN imm1[21]
    DIRECTION INPUT ;
    USE SIGNAL ;
    PORT
      LAYER M4 ;
        RECT 0.000 109.392 0.192 109.416 ;
    END
  END imm1[21]
  PIN imm1[22]
    DIRECTION INPUT ;
    USE SIGNAL ;
    PORT
      LAYER M4 ;
        RECT 0.000 109.776 0.192 109.800 ;
    END
  END imm1[22]
  PIN imm1[23]
    DIRECTION INPUT ;
    USE SIGNAL ;
    PORT
      LAYER M4 ;
        RECT 0.000 110.112 0.192 110.136 ;
    END
  END imm1[23]
  PIN imm1[24]
    DIRECTION INPUT ;
    USE SIGNAL ;
    PORT
      LAYER M4 ;
        RECT 0.000 110.496 0.192 110.520 ;
    END
  END imm1[24]
  PIN imm1[25]
    DIRECTION INPUT ;
    USE SIGNAL ;
    PORT
      LAYER M4 ;
        RECT 0.000 110.880 0.192 110.904 ;
    END
  END imm1[25]
  PIN imm1[26]
    DIRECTION INPUT ;
    USE SIGNAL ;
    PORT
      LAYER M4 ;
        RECT 0.000 111.216 0.192 111.240 ;
    END
  END imm1[26]
  PIN imm1[27]
    DIRECTION INPUT ;
    USE SIGNAL ;
    PORT
      LAYER M4 ;
        RECT 0.000 111.600 0.192 111.624 ;
    END
  END imm1[27]
  PIN imm1[28]
    DIRECTION INPUT ;
    USE SIGNAL ;
    PORT
      LAYER M4 ;
        RECT 0.000 111.936 0.192 111.960 ;
    END
  END imm1[28]
  PIN imm1[29]
    DIRECTION INPUT ;
    USE SIGNAL ;
    PORT
      LAYER M4 ;
        RECT 0.000 112.320 0.192 112.344 ;
    END
  END imm1[29]
  PIN imm1[30]
    DIRECTION INPUT ;
    USE SIGNAL ;
    PORT
      LAYER M4 ;
        RECT 0.000 112.656 0.192 112.680 ;
    END
  END imm1[30]
  PIN imm1[31]
    DIRECTION INPUT ;
    USE SIGNAL ;
    PORT
      LAYER M4 ;
        RECT 0.000 113.040 0.192 113.064 ;
    END
  END imm1[31]
  PIN imm2[0]
    DIRECTION INPUT ;
    USE SIGNAL ;
    PORT
      LAYER M4 ;
        RECT 0.000 113.424 0.192 113.448 ;
    END
  END imm2[0]
  PIN imm2[1]
    DIRECTION INPUT ;
    USE SIGNAL ;
    PORT
      LAYER M4 ;
        RECT 0.000 113.760 0.192 113.784 ;
    END
  END imm2[1]
  PIN imm2[2]
    DIRECTION INPUT ;
    USE SIGNAL ;
    PORT
      LAYER M4 ;
        RECT 0.000 114.144 0.192 114.168 ;
    END
  END imm2[2]
  PIN imm2[3]
    DIRECTION INPUT ;
    USE SIGNAL ;
    PORT
      LAYER M4 ;
        RECT 0.000 114.480 0.192 114.504 ;
    END
  END imm2[3]
  PIN imm2[4]
    DIRECTION INPUT ;
    USE SIGNAL ;
    PORT
      LAYER M4 ;
        RECT 0.000 114.864 0.192 114.888 ;
    END
  END imm2[4]
  PIN imm2[5]
    DIRECTION INPUT ;
    USE SIGNAL ;
    PORT
      LAYER M4 ;
        RECT 0.000 115.248 0.192 115.272 ;
    END
  END imm2[5]
  PIN imm2[6]
    DIRECTION INPUT ;
    USE SIGNAL ;
    PORT
      LAYER M4 ;
        RECT 0.000 115.584 0.192 115.608 ;
    END
  END imm2[6]
  PIN imm2[7]
    DIRECTION INPUT ;
    USE SIGNAL ;
    PORT
      LAYER M4 ;
        RECT 0.000 115.968 0.192 115.992 ;
    END
  END imm2[7]
  PIN imm2[8]
    DIRECTION INPUT ;
    USE SIGNAL ;
    PORT
      LAYER M4 ;
        RECT 0.000 116.304 0.192 116.328 ;
    END
  END imm2[8]
  PIN imm2[9]
    DIRECTION INPUT ;
    USE SIGNAL ;
    PORT
      LAYER M4 ;
        RECT 0.000 116.688 0.192 116.712 ;
    END
  END imm2[9]
  PIN imm2[10]
    DIRECTION INPUT ;
    USE SIGNAL ;
    PORT
      LAYER M4 ;
        RECT 0.000 117.072 0.192 117.096 ;
    END
  END imm2[10]
  PIN imm2[11]
    DIRECTION INPUT ;
    USE SIGNAL ;
    PORT
      LAYER M4 ;
        RECT 0.000 117.408 0.192 117.432 ;
    END
  END imm2[11]
  PIN imm2[12]
    DIRECTION INPUT ;
    USE SIGNAL ;
    PORT
      LAYER M4 ;
        RECT 0.000 117.792 0.192 117.816 ;
    END
  END imm2[12]
  PIN imm2[13]
    DIRECTION INPUT ;
    USE SIGNAL ;
    PORT
      LAYER M4 ;
        RECT 0.000 118.128 0.192 118.152 ;
    END
  END imm2[13]
  PIN imm2[14]
    DIRECTION INPUT ;
    USE SIGNAL ;
    PORT
      LAYER M4 ;
        RECT 0.000 118.512 0.192 118.536 ;
    END
  END imm2[14]
  PIN imm2[15]
    DIRECTION INPUT ;
    USE SIGNAL ;
    PORT
      LAYER M4 ;
        RECT 0.000 118.848 0.192 118.872 ;
    END
  END imm2[15]
  PIN imm2[16]
    DIRECTION INPUT ;
    USE SIGNAL ;
    PORT
      LAYER M4 ;
        RECT 0.000 119.232 0.192 119.256 ;
    END
  END imm2[16]
  PIN imm2[17]
    DIRECTION INPUT ;
    USE SIGNAL ;
    PORT
      LAYER M4 ;
        RECT 0.000 119.616 0.192 119.640 ;
    END
  END imm2[17]
  PIN imm2[18]
    DIRECTION INPUT ;
    USE SIGNAL ;
    PORT
      LAYER M4 ;
        RECT 0.000 119.952 0.192 119.976 ;
    END
  END imm2[18]
  PIN imm2[19]
    DIRECTION INPUT ;
    USE SIGNAL ;
    PORT
      LAYER M4 ;
        RECT 0.000 120.336 0.192 120.360 ;
    END
  END imm2[19]
  PIN imm2[20]
    DIRECTION INPUT ;
    USE SIGNAL ;
    PORT
      LAYER M4 ;
        RECT 0.000 120.672 0.192 120.696 ;
    END
  END imm2[20]
  PIN imm2[21]
    DIRECTION INPUT ;
    USE SIGNAL ;
    PORT
      LAYER M4 ;
        RECT 0.000 121.056 0.192 121.080 ;
    END
  END imm2[21]
  PIN imm2[22]
    DIRECTION INPUT ;
    USE SIGNAL ;
    PORT
      LAYER M4 ;
        RECT 0.000 121.440 0.192 121.464 ;
    END
  END imm2[22]
  PIN imm2[23]
    DIRECTION INPUT ;
    USE SIGNAL ;
    PORT
      LAYER M4 ;
        RECT 0.000 121.776 0.192 121.800 ;
    END
  END imm2[23]
  PIN imm2[24]
    DIRECTION INPUT ;
    USE SIGNAL ;
    PORT
      LAYER M4 ;
        RECT 0.000 122.160 0.192 122.184 ;
    END
  END imm2[24]
  PIN imm2[25]
    DIRECTION INPUT ;
    USE SIGNAL ;
    PORT
      LAYER M4 ;
        RECT 0.000 122.496 0.192 122.520 ;
    END
  END imm2[25]
  PIN imm2[26]
    DIRECTION INPUT ;
    USE SIGNAL ;
    PORT
      LAYER M4 ;
        RECT 0.000 122.880 0.192 122.904 ;
    END
  END imm2[26]
  PIN imm2[27]
    DIRECTION INPUT ;
    USE SIGNAL ;
    PORT
      LAYER M4 ;
        RECT 0.000 123.216 0.192 123.240 ;
    END
  END imm2[27]
  PIN imm2[28]
    DIRECTION INPUT ;
    USE SIGNAL ;
    PORT
      LAYER M4 ;
        RECT 0.000 123.600 0.192 123.624 ;
    END
  END imm2[28]
  PIN imm2[29]
    DIRECTION INPUT ;
    USE SIGNAL ;
    PORT
      LAYER M4 ;
        RECT 0.000 123.984 0.192 124.008 ;
    END
  END imm2[29]
  PIN imm2[30]
    DIRECTION INPUT ;
    USE SIGNAL ;
    PORT
      LAYER M4 ;
        RECT 0.000 124.320 0.192 124.344 ;
    END
  END imm2[30]
  PIN imm2[31]
    DIRECTION INPUT ;
    USE SIGNAL ;
    PORT
      LAYER M4 ;
        RECT 0.000 124.704 0.192 124.728 ;
    END
  END imm2[31]
  PIN cls[0]
    DIRECTION INPUT ;
    USE SIGNAL ;
    PORT
      LAYER M4 ;
        RECT 0.000 125.040 0.192 125.064 ;
    END
  END cls[0]
  PIN cls[1]
    DIRECTION INPUT ;
    USE SIGNAL ;
    PORT
      LAYER M4 ;
        RECT 0.000 125.424 0.192 125.448 ;
    END
  END cls[1]
  PIN cls[2]
    DIRECTION INPUT ;
    USE SIGNAL ;
    PORT
      LAYER M4 ;
        RECT 0.000 125.808 0.192 125.832 ;
    END
  END cls[2]
  PIN accept
    DIRECTION INPUT ;
    USE SIGNAL ;
    PORT
      LAYER M4 ;
        RECT 0.000 126.144 0.192 126.168 ;
    END
  END accept
  PIN i_sfu[0]
    DIRECTION INPUT ;
    USE SIGNAL ;
    PORT
      LAYER M4 ;
        RECT 0.000 126.528 0.192 126.552 ;
    END
  END i_sfu[0]
  PIN i_sfu[1]
    DIRECTION INPUT ;
    USE SIGNAL ;
    PORT
      LAYER M4 ;
        RECT 0.000 126.864 0.192 126.888 ;
    END
  END i_sfu[1]
  PIN i_sfu[2]
    DIRECTION INPUT ;
    USE SIGNAL ;
    PORT
      LAYER M4 ;
        RECT 0.000 127.248 0.192 127.272 ;
    END
  END i_sfu[2]
  PIN va_re
    DIRECTION OUTPUT ;
    USE SIGNAL ;
    PORT
      LAYER M3 ;
        RECT 2.301 0.000 2.325 0.192 ;
    END
  END va_re
  PIN va_addr[0]
    DIRECTION OUTPUT ;
    USE SIGNAL ;
    PORT
      LAYER M5 ;
        RECT 2.592 0.000 2.616 0.192 ;
    END
  END va_addr[0]
  PIN va_addr[1]
    DIRECTION OUTPUT ;
    USE SIGNAL ;
    PORT
      LAYER M3 ;
        RECT 2.913 0.000 2.937 0.192 ;
    END
  END va_addr[1]
  PIN va_addr[2]
    DIRECTION OUTPUT ;
    USE SIGNAL ;
    PORT
      LAYER M5 ;
        RECT 3.216 0.000 3.240 0.192 ;
    END
  END va_addr[2]
  PIN va_addr[3]
    DIRECTION OUTPUT ;
    USE SIGNAL ;
    PORT
      LAYER M3 ;
        RECT 3.561 0.000 3.585 0.192 ;
    END
  END va_addr[3]
  PIN va_addr[4]
    DIRECTION OUTPUT ;
    USE SIGNAL ;
    PORT
      LAYER M5 ;
        RECT 3.840 0.000 3.864 0.192 ;
    END
  END va_addr[4]
  PIN va_addr[5]
    DIRECTION OUTPUT ;
    USE SIGNAL ;
    PORT
      LAYER M3 ;
        RECT 4.173 0.000 4.197 0.192 ;
    END
  END va_addr[5]
  PIN va_addr[6]
    DIRECTION OUTPUT ;
    USE SIGNAL ;
    PORT
      LAYER M5 ;
        RECT 4.464 0.000 4.488 0.192 ;
    END
  END va_addr[6]
  PIN va_addr[7]
    DIRECTION OUTPUT ;
    USE SIGNAL ;
    PORT
      LAYER M3 ;
        RECT 4.785 0.000 4.809 0.192 ;
    END
  END va_addr[7]
  PIN va_addr[8]
    DIRECTION OUTPUT ;
    USE SIGNAL ;
    PORT
      LAYER M5 ;
        RECT 5.088 0.000 5.112 0.192 ;
    END
  END va_addr[8]
  PIN va_addr[9]
    DIRECTION OUTPUT ;
    USE SIGNAL ;
    PORT
      LAYER M3 ;
        RECT 5.433 0.000 5.457 0.192 ;
    END
  END va_addr[9]
  PIN va_addr[10]
    DIRECTION OUTPUT ;
    USE SIGNAL ;
    PORT
      LAYER M5 ;
        RECT 5.712 0.000 5.736 0.192 ;
    END
  END va_addr[10]
  PIN va_addr[11]
    DIRECTION OUTPUT ;
    USE SIGNAL ;
    PORT
      LAYER M3 ;
        RECT 6.045 0.000 6.069 0.192 ;
    END
  END va_addr[11]
  PIN va_addr[12]
    DIRECTION OUTPUT ;
    USE SIGNAL ;
    PORT
      LAYER M5 ;
        RECT 6.336 0.000 6.360 0.192 ;
    END
  END va_addr[12]
  PIN va_addr[13]
    DIRECTION OUTPUT ;
    USE SIGNAL ;
    PORT
      LAYER M3 ;
        RECT 6.657 0.000 6.681 0.192 ;
    END
  END va_addr[13]
  PIN va_addr[14]
    DIRECTION OUTPUT ;
    USE SIGNAL ;
    PORT
      LAYER M5 ;
        RECT 6.960 0.000 6.984 0.192 ;
    END
  END va_addr[14]
  PIN va_addr[15]
    DIRECTION OUTPUT ;
    USE SIGNAL ;
    PORT
      LAYER M3 ;
        RECT 7.269 0.000 7.293 0.192 ;
    END
  END va_addr[15]
  PIN va_addr[16]
    DIRECTION OUTPUT ;
    USE SIGNAL ;
    PORT
      LAYER M5 ;
        RECT 7.584 0.000 7.608 0.192 ;
    END
  END va_addr[16]
  PIN va_addr[17]
    DIRECTION OUTPUT ;
    USE SIGNAL ;
    PORT
      LAYER M3 ;
        RECT 7.917 0.000 7.941 0.192 ;
    END
  END va_addr[17]
  PIN va_addr[18]
    DIRECTION OUTPUT ;
    USE SIGNAL ;
    PORT
      LAYER M5 ;
        RECT 8.208 0.000 8.232 0.192 ;
    END
  END va_addr[18]
  PIN va_addr[19]
    DIRECTION OUTPUT ;
    USE SIGNAL ;
    PORT
      LAYER M3 ;
        RECT 8.529 0.000 8.553 0.192 ;
    END
  END va_addr[19]
  PIN va_addr[20]
    DIRECTION OUTPUT ;
    USE SIGNAL ;
    PORT
      LAYER M5 ;
        RECT 8.832 0.000 8.856 0.192 ;
    END
  END va_addr[20]
  PIN va_addr[21]
    DIRECTION OUTPUT ;
    USE SIGNAL ;
    PORT
      LAYER M3 ;
        RECT 9.141 0.000 9.165 0.192 ;
    END
  END va_addr[21]
  PIN va_addr[22]
    DIRECTION OUTPUT ;
    USE SIGNAL ;
    PORT
      LAYER M5 ;
        RECT 9.456 0.000 9.480 0.192 ;
    END
  END va_addr[22]
  PIN va_addr[23]
    DIRECTION OUTPUT ;
    USE SIGNAL ;
    PORT
      LAYER M3 ;
        RECT 9.789 0.000 9.813 0.192 ;
    END
  END va_addr[23]
  PIN vb_re
    DIRECTION OUTPUT ;
    USE SIGNAL ;
    PORT
      LAYER M5 ;
        RECT 10.080 0.000 10.104 0.192 ;
    END
  END vb_re
  PIN vb_addr[0]
    DIRECTION OUTPUT ;
    USE SIGNAL ;
    PORT
      LAYER M3 ;
        RECT 10.401 0.000 10.425 0.192 ;
    END
  END vb_addr[0]
  PIN vb_addr[1]
    DIRECTION OUTPUT ;
    USE SIGNAL ;
    PORT
      LAYER M5 ;
        RECT 10.704 0.000 10.728 0.192 ;
    END
  END vb_addr[1]
  PIN vb_addr[2]
    DIRECTION OUTPUT ;
    USE SIGNAL ;
    PORT
      LAYER M3 ;
        RECT 11.013 0.000 11.037 0.192 ;
    END
  END vb_addr[2]
  PIN vb_addr[3]
    DIRECTION OUTPUT ;
    USE SIGNAL ;
    PORT
      LAYER M5 ;
        RECT 11.328 0.000 11.352 0.192 ;
    END
  END vb_addr[3]
  PIN vb_addr[4]
    DIRECTION OUTPUT ;
    USE SIGNAL ;
    PORT
      LAYER M3 ;
        RECT 11.661 0.000 11.685 0.192 ;
    END
  END vb_addr[4]
  PIN vb_addr[5]
    DIRECTION OUTPUT ;
    USE SIGNAL ;
    PORT
      LAYER M5 ;
        RECT 11.952 0.000 11.976 0.192 ;
    END
  END vb_addr[5]
  PIN vb_addr[6]
    DIRECTION OUTPUT ;
    USE SIGNAL ;
    PORT
      LAYER M3 ;
        RECT 12.273 0.000 12.297 0.192 ;
    END
  END vb_addr[6]
  PIN vb_addr[7]
    DIRECTION OUTPUT ;
    USE SIGNAL ;
    PORT
      LAYER M5 ;
        RECT 12.576 0.000 12.600 0.192 ;
    END
  END vb_addr[7]
  PIN vb_addr[8]
    DIRECTION OUTPUT ;
    USE SIGNAL ;
    PORT
      LAYER M3 ;
        RECT 12.885 0.000 12.909 0.192 ;
    END
  END vb_addr[8]
  PIN vb_addr[9]
    DIRECTION OUTPUT ;
    USE SIGNAL ;
    PORT
      LAYER M5 ;
        RECT 13.200 0.000 13.224 0.192 ;
    END
  END vb_addr[9]
  PIN vb_addr[10]
    DIRECTION OUTPUT ;
    USE SIGNAL ;
    PORT
      LAYER M3 ;
        RECT 13.497 0.000 13.521 0.192 ;
    END
  END vb_addr[10]
  PIN vb_addr[11]
    DIRECTION OUTPUT ;
    USE SIGNAL ;
    PORT
      LAYER M5 ;
        RECT 13.824 0.000 13.848 0.192 ;
    END
  END vb_addr[11]
  PIN vb_addr[12]
    DIRECTION OUTPUT ;
    USE SIGNAL ;
    PORT
      LAYER M3 ;
        RECT 14.145 0.000 14.169 0.192 ;
    END
  END vb_addr[12]
  PIN vb_addr[13]
    DIRECTION OUTPUT ;
    USE SIGNAL ;
    PORT
      LAYER M5 ;
        RECT 14.448 0.000 14.472 0.192 ;
    END
  END vb_addr[13]
  PIN vb_addr[14]
    DIRECTION OUTPUT ;
    USE SIGNAL ;
    PORT
      LAYER M3 ;
        RECT 14.757 0.000 14.781 0.192 ;
    END
  END vb_addr[14]
  PIN vb_addr[15]
    DIRECTION OUTPUT ;
    USE SIGNAL ;
    PORT
      LAYER M5 ;
        RECT 15.072 0.000 15.096 0.192 ;
    END
  END vb_addr[15]
  PIN vb_addr[16]
    DIRECTION OUTPUT ;
    USE SIGNAL ;
    PORT
      LAYER M3 ;
        RECT 15.369 0.000 15.393 0.192 ;
    END
  END vb_addr[16]
  PIN vb_addr[17]
    DIRECTION OUTPUT ;
    USE SIGNAL ;
    PORT
      LAYER M5 ;
        RECT 15.696 0.000 15.720 0.192 ;
    END
  END vb_addr[17]
  PIN vb_addr[18]
    DIRECTION OUTPUT ;
    USE SIGNAL ;
    PORT
      LAYER M3 ;
        RECT 16.017 0.000 16.041 0.192 ;
    END
  END vb_addr[18]
  PIN vb_addr[19]
    DIRECTION OUTPUT ;
    USE SIGNAL ;
    PORT
      LAYER M5 ;
        RECT 16.320 0.000 16.344 0.192 ;
    END
  END vb_addr[19]
  PIN vb_addr[20]
    DIRECTION OUTPUT ;
    USE SIGNAL ;
    PORT
      LAYER M3 ;
        RECT 16.629 0.000 16.653 0.192 ;
    END
  END vb_addr[20]
  PIN vb_addr[21]
    DIRECTION OUTPUT ;
    USE SIGNAL ;
    PORT
      LAYER M5 ;
        RECT 16.944 0.000 16.968 0.192 ;
    END
  END vb_addr[21]
  PIN vb_addr[22]
    DIRECTION OUTPUT ;
    USE SIGNAL ;
    PORT
      LAYER M3 ;
        RECT 17.241 0.000 17.265 0.192 ;
    END
  END vb_addr[22]
  PIN vb_addr[23]
    DIRECTION OUTPUT ;
    USE SIGNAL ;
    PORT
      LAYER M5 ;
        RECT 17.568 0.000 17.592 0.192 ;
    END
  END vb_addr[23]
  PIN vc_re
    DIRECTION OUTPUT ;
    USE SIGNAL ;
    PORT
      LAYER M3 ;
        RECT 17.889 0.000 17.913 0.192 ;
    END
  END vc_re
  PIN vc_addr[0]
    DIRECTION OUTPUT ;
    USE SIGNAL ;
    PORT
      LAYER M5 ;
        RECT 18.192 0.000 18.216 0.192 ;
    END
  END vc_addr[0]
  PIN vc_addr[1]
    DIRECTION OUTPUT ;
    USE SIGNAL ;
    PORT
      LAYER M3 ;
        RECT 18.501 0.000 18.525 0.192 ;
    END
  END vc_addr[1]
  PIN vc_addr[2]
    DIRECTION OUTPUT ;
    USE SIGNAL ;
    PORT
      LAYER M5 ;
        RECT 18.816 0.000 18.840 0.192 ;
    END
  END vc_addr[2]
  PIN vc_addr[3]
    DIRECTION OUTPUT ;
    USE SIGNAL ;
    PORT
      LAYER M3 ;
        RECT 19.113 0.000 19.137 0.192 ;
    END
  END vc_addr[3]
  PIN vc_addr[4]
    DIRECTION OUTPUT ;
    USE SIGNAL ;
    PORT
      LAYER M5 ;
        RECT 19.440 0.000 19.464 0.192 ;
    END
  END vc_addr[4]
  PIN vc_addr[5]
    DIRECTION OUTPUT ;
    USE SIGNAL ;
    PORT
      LAYER M3 ;
        RECT 19.761 0.000 19.785 0.192 ;
    END
  END vc_addr[5]
  PIN vc_addr[6]
    DIRECTION OUTPUT ;
    USE SIGNAL ;
    PORT
      LAYER M5 ;
        RECT 20.064 0.000 20.088 0.192 ;
    END
  END vc_addr[6]
  PIN vc_addr[7]
    DIRECTION OUTPUT ;
    USE SIGNAL ;
    PORT
      LAYER M3 ;
        RECT 20.373 0.000 20.397 0.192 ;
    END
  END vc_addr[7]
  PIN vc_addr[8]
    DIRECTION OUTPUT ;
    USE SIGNAL ;
    PORT
      LAYER M5 ;
        RECT 20.688 0.000 20.712 0.192 ;
    END
  END vc_addr[8]
  PIN vc_addr[9]
    DIRECTION OUTPUT ;
    USE SIGNAL ;
    PORT
      LAYER M3 ;
        RECT 20.985 0.000 21.009 0.192 ;
    END
  END vc_addr[9]
  PIN vc_addr[10]
    DIRECTION OUTPUT ;
    USE SIGNAL ;
    PORT
      LAYER M5 ;
        RECT 21.312 0.000 21.336 0.192 ;
    END
  END vc_addr[10]
  PIN vc_addr[11]
    DIRECTION OUTPUT ;
    USE SIGNAL ;
    PORT
      LAYER M3 ;
        RECT 21.597 0.000 21.621 0.192 ;
    END
  END vc_addr[11]
  PIN vc_addr[12]
    DIRECTION OUTPUT ;
    USE SIGNAL ;
    PORT
      LAYER M5 ;
        RECT 21.936 0.000 21.960 0.192 ;
    END
  END vc_addr[12]
  PIN vc_addr[13]
    DIRECTION OUTPUT ;
    USE SIGNAL ;
    PORT
      LAYER M3 ;
        RECT 22.245 0.000 22.269 0.192 ;
    END
  END vc_addr[13]
  PIN vc_addr[14]
    DIRECTION OUTPUT ;
    USE SIGNAL ;
    PORT
      LAYER M5 ;
        RECT 22.560 0.000 22.584 0.192 ;
    END
  END vc_addr[14]
  PIN vc_addr[15]
    DIRECTION OUTPUT ;
    USE SIGNAL ;
    PORT
      LAYER M3 ;
        RECT 22.857 0.000 22.881 0.192 ;
    END
  END vc_addr[15]
  PIN vc_addr[16]
    DIRECTION OUTPUT ;
    USE SIGNAL ;
    PORT
      LAYER M5 ;
        RECT 23.184 0.000 23.208 0.192 ;
    END
  END vc_addr[16]
  PIN vc_addr[17]
    DIRECTION OUTPUT ;
    USE SIGNAL ;
    PORT
      LAYER M3 ;
        RECT 23.469 0.000 23.493 0.192 ;
    END
  END vc_addr[17]
  PIN vc_addr[18]
    DIRECTION OUTPUT ;
    USE SIGNAL ;
    PORT
      LAYER M5 ;
        RECT 23.808 0.000 23.832 0.192 ;
    END
  END vc_addr[18]
  PIN vc_addr[19]
    DIRECTION OUTPUT ;
    USE SIGNAL ;
    PORT
      LAYER M3 ;
        RECT 24.117 0.000 24.141 0.192 ;
    END
  END vc_addr[19]
  PIN vc_addr[20]
    DIRECTION OUTPUT ;
    USE SIGNAL ;
    PORT
      LAYER M5 ;
        RECT 24.432 0.000 24.456 0.192 ;
    END
  END vc_addr[20]
  PIN vc_addr[21]
    DIRECTION OUTPUT ;
    USE SIGNAL ;
    PORT
      LAYER M3 ;
        RECT 24.729 0.000 24.753 0.192 ;
    END
  END vc_addr[21]
  PIN vc_addr[22]
    DIRECTION OUTPUT ;
    USE SIGNAL ;
    PORT
      LAYER M5 ;
        RECT 25.056 0.000 25.080 0.192 ;
    END
  END vc_addr[22]
  PIN vc_addr[23]
    DIRECTION OUTPUT ;
    USE SIGNAL ;
    PORT
      LAYER M3 ;
        RECT 25.341 0.000 25.365 0.192 ;
    END
  END vc_addr[23]
  PIN wrom_re
    DIRECTION OUTPUT ;
    USE SIGNAL ;
    PORT
      LAYER M5 ;
        RECT 25.680 0.000 25.704 0.192 ;
    END
  END wrom_re
  PIN wrom_addr[0]
    DIRECTION OUTPUT ;
    USE SIGNAL ;
    PORT
      LAYER M3 ;
        RECT 25.989 0.000 26.013 0.192 ;
    END
  END wrom_addr[0]
  PIN wrom_addr[1]
    DIRECTION OUTPUT ;
    USE SIGNAL ;
    PORT
      LAYER M5 ;
        RECT 26.304 0.000 26.328 0.192 ;
    END
  END wrom_addr[1]
  PIN wrom_addr[2]
    DIRECTION OUTPUT ;
    USE SIGNAL ;
    PORT
      LAYER M3 ;
        RECT 26.601 0.000 26.625 0.192 ;
    END
  END wrom_addr[2]
  PIN wrom_addr[3]
    DIRECTION OUTPUT ;
    USE SIGNAL ;
    PORT
      LAYER M5 ;
        RECT 26.928 0.000 26.952 0.192 ;
    END
  END wrom_addr[3]
  PIN wrom_addr[4]
    DIRECTION OUTPUT ;
    USE SIGNAL ;
    PORT
      LAYER M3 ;
        RECT 27.213 0.000 27.237 0.192 ;
    END
  END wrom_addr[4]
  PIN wrom_addr[5]
    DIRECTION OUTPUT ;
    USE SIGNAL ;
    PORT
      LAYER M5 ;
        RECT 27.552 0.000 27.576 0.192 ;
    END
  END wrom_addr[5]
  PIN wrom_addr[6]
    DIRECTION OUTPUT ;
    USE SIGNAL ;
    PORT
      LAYER M3 ;
        RECT 27.825 0.000 27.849 0.192 ;
    END
  END wrom_addr[6]
  PIN wrom_addr[7]
    DIRECTION OUTPUT ;
    USE SIGNAL ;
    PORT
      LAYER M5 ;
        RECT 28.128 0.000 28.152 0.192 ;
    END
  END wrom_addr[7]
  PIN wrom_addr[8]
    DIRECTION OUTPUT ;
    USE SIGNAL ;
    PORT
      LAYER M3 ;
        RECT 28.473 0.000 28.497 0.192 ;
    END
  END wrom_addr[8]
  PIN wrom_addr[9]
    DIRECTION OUTPUT ;
    USE SIGNAL ;
    PORT
      LAYER M5 ;
        RECT 28.752 0.000 28.776 0.192 ;
    END
  END wrom_addr[9]
  PIN wrom_addr[10]
    DIRECTION OUTPUT ;
    USE SIGNAL ;
    PORT
      LAYER M3 ;
        RECT 29.085 0.000 29.109 0.192 ;
    END
  END wrom_addr[10]
  PIN wrom_addr[11]
    DIRECTION OUTPUT ;
    USE SIGNAL ;
    PORT
      LAYER M5 ;
        RECT 29.376 0.000 29.400 0.192 ;
    END
  END wrom_addr[11]
  PIN wrom_addr[12]
    DIRECTION OUTPUT ;
    USE SIGNAL ;
    PORT
      LAYER M3 ;
        RECT 29.697 0.000 29.721 0.192 ;
    END
  END wrom_addr[12]
  PIN wrom_addr[13]
    DIRECTION OUTPUT ;
    USE SIGNAL ;
    PORT
      LAYER M5 ;
        RECT 30.000 0.000 30.024 0.192 ;
    END
  END wrom_addr[13]
  PIN wrom_addr[14]
    DIRECTION OUTPUT ;
    USE SIGNAL ;
    PORT
      LAYER M3 ;
        RECT 30.345 0.000 30.369 0.192 ;
    END
  END wrom_addr[14]
  PIN wrom_addr[15]
    DIRECTION OUTPUT ;
    USE SIGNAL ;
    PORT
      LAYER M5 ;
        RECT 30.624 0.000 30.648 0.192 ;
    END
  END wrom_addr[15]
  PIN wrom_addr[16]
    DIRECTION OUTPUT ;
    USE SIGNAL ;
    PORT
      LAYER M3 ;
        RECT 30.957 0.000 30.981 0.192 ;
    END
  END wrom_addr[16]
  PIN wrom_addr[17]
    DIRECTION OUTPUT ;
    USE SIGNAL ;
    PORT
      LAYER M5 ;
        RECT 31.248 0.000 31.272 0.192 ;
    END
  END wrom_addr[17]
  PIN wrom_addr[18]
    DIRECTION OUTPUT ;
    USE SIGNAL ;
    PORT
      LAYER M3 ;
        RECT 31.569 0.000 31.593 0.192 ;
    END
  END wrom_addr[18]
  PIN wrom_addr[19]
    DIRECTION OUTPUT ;
    USE SIGNAL ;
    PORT
      LAYER M5 ;
        RECT 31.872 0.000 31.896 0.192 ;
    END
  END wrom_addr[19]
  PIN wrom_addr[20]
    DIRECTION OUTPUT ;
    USE SIGNAL ;
    PORT
      LAYER M3 ;
        RECT 32.217 0.000 32.241 0.192 ;
    END
  END wrom_addr[20]
  PIN wrom_addr[21]
    DIRECTION OUTPUT ;
    USE SIGNAL ;
    PORT
      LAYER M5 ;
        RECT 32.496 0.000 32.520 0.192 ;
    END
  END wrom_addr[21]
  PIN wrom_addr[22]
    DIRECTION OUTPUT ;
    USE SIGNAL ;
    PORT
      LAYER M3 ;
        RECT 32.829 0.000 32.853 0.192 ;
    END
  END wrom_addr[22]
  PIN wrom_addr[23]
    DIRECTION OUTPUT ;
    USE SIGNAL ;
    PORT
      LAYER M5 ;
        RECT 33.120 0.000 33.144 0.192 ;
    END
  END wrom_addr[23]
  PIN crom_re
    DIRECTION OUTPUT ;
    USE SIGNAL ;
    PORT
      LAYER M3 ;
        RECT 33.441 0.000 33.465 0.192 ;
    END
  END crom_re
  PIN crom_addr[0]
    DIRECTION OUTPUT ;
    USE SIGNAL ;
    PORT
      LAYER M5 ;
        RECT 33.744 0.000 33.768 0.192 ;
    END
  END crom_addr[0]
  PIN crom_addr[1]
    DIRECTION OUTPUT ;
    USE SIGNAL ;
    PORT
      LAYER M3 ;
        RECT 34.053 0.000 34.077 0.192 ;
    END
  END crom_addr[1]
  PIN crom_addr[2]
    DIRECTION OUTPUT ;
    USE SIGNAL ;
    PORT
      LAYER M5 ;
        RECT 34.368 0.000 34.392 0.192 ;
    END
  END crom_addr[2]
  PIN crom_addr[3]
    DIRECTION OUTPUT ;
    USE SIGNAL ;
    PORT
      LAYER M3 ;
        RECT 34.701 0.000 34.725 0.192 ;
    END
  END crom_addr[3]
  PIN crom_addr[4]
    DIRECTION OUTPUT ;
    USE SIGNAL ;
    PORT
      LAYER M5 ;
        RECT 34.992 0.000 35.016 0.192 ;
    END
  END crom_addr[4]
  PIN crom_addr[5]
    DIRECTION OUTPUT ;
    USE SIGNAL ;
    PORT
      LAYER M3 ;
        RECT 35.313 0.000 35.337 0.192 ;
    END
  END crom_addr[5]
  PIN crom_addr[6]
    DIRECTION OUTPUT ;
    USE SIGNAL ;
    PORT
      LAYER M5 ;
        RECT 35.616 0.000 35.640 0.192 ;
    END
  END crom_addr[6]
  PIN crom_addr[7]
    DIRECTION OUTPUT ;
    USE SIGNAL ;
    PORT
      LAYER M3 ;
        RECT 35.925 0.000 35.949 0.192 ;
    END
  END crom_addr[7]
  PIN crom_addr[8]
    DIRECTION OUTPUT ;
    USE SIGNAL ;
    PORT
      LAYER M5 ;
        RECT 36.240 0.000 36.264 0.192 ;
    END
  END crom_addr[8]
  PIN crom_addr[9]
    DIRECTION OUTPUT ;
    USE SIGNAL ;
    PORT
      LAYER M3 ;
        RECT 36.573 0.000 36.597 0.192 ;
    END
  END crom_addr[9]
  PIN crom_addr[10]
    DIRECTION OUTPUT ;
    USE SIGNAL ;
    PORT
      LAYER M5 ;
        RECT 36.864 0.000 36.888 0.192 ;
    END
  END crom_addr[10]
  PIN crom_addr[11]
    DIRECTION OUTPUT ;
    USE SIGNAL ;
    PORT
      LAYER M3 ;
        RECT 37.185 0.000 37.209 0.192 ;
    END
  END crom_addr[11]
  PIN crom_addr[12]
    DIRECTION OUTPUT ;
    USE SIGNAL ;
    PORT
      LAYER M5 ;
        RECT 37.488 0.000 37.512 0.192 ;
    END
  END crom_addr[12]
  PIN crom_addr[13]
    DIRECTION OUTPUT ;
    USE SIGNAL ;
    PORT
      LAYER M3 ;
        RECT 37.797 0.000 37.821 0.192 ;
    END
  END crom_addr[13]
  PIN crom_addr[14]
    DIRECTION OUTPUT ;
    USE SIGNAL ;
    PORT
      LAYER M5 ;
        RECT 38.112 0.000 38.136 0.192 ;
    END
  END crom_addr[14]
  PIN crom_addr[15]
    DIRECTION OUTPUT ;
    USE SIGNAL ;
    PORT
      LAYER M3 ;
        RECT 38.445 0.000 38.469 0.192 ;
    END
  END crom_addr[15]
  PIN crom_addr[16]
    DIRECTION OUTPUT ;
    USE SIGNAL ;
    PORT
      LAYER M5 ;
        RECT 38.736 0.000 38.760 0.192 ;
    END
  END crom_addr[16]
  PIN crom_addr[17]
    DIRECTION OUTPUT ;
    USE SIGNAL ;
    PORT
      LAYER M3 ;
        RECT 39.057 0.000 39.081 0.192 ;
    END
  END crom_addr[17]
  PIN crom_addr[18]
    DIRECTION OUTPUT ;
    USE SIGNAL ;
    PORT
      LAYER M5 ;
        RECT 39.360 0.000 39.384 0.192 ;
    END
  END crom_addr[18]
  PIN crom_addr[19]
    DIRECTION OUTPUT ;
    USE SIGNAL ;
    PORT
      LAYER M3 ;
        RECT 39.669 0.000 39.693 0.192 ;
    END
  END crom_addr[19]
  PIN crom_addr[20]
    DIRECTION OUTPUT ;
    USE SIGNAL ;
    PORT
      LAYER M5 ;
        RECT 39.984 0.000 40.008 0.192 ;
    END
  END crom_addr[20]
  PIN crom_addr[21]
    DIRECTION OUTPUT ;
    USE SIGNAL ;
    PORT
      LAYER M3 ;
        RECT 40.281 0.000 40.305 0.192 ;
    END
  END crom_addr[21]
  PIN crom_addr[22]
    DIRECTION OUTPUT ;
    USE SIGNAL ;
    PORT
      LAYER M5 ;
        RECT 40.608 0.000 40.632 0.192 ;
    END
  END crom_addr[22]
  PIN crom_addr[23]
    DIRECTION OUTPUT ;
    USE SIGNAL ;
    PORT
      LAYER M3 ;
        RECT 40.929 0.000 40.953 0.192 ;
    END
  END crom_addr[23]
  PIN va_q[0]
    DIRECTION INPUT ;
    USE SIGNAL ;
    PORT
      LAYER M5 ;
        RECT 41.232 0.000 41.256 0.192 ;
    END
  END va_q[0]
  PIN va_q[1]
    DIRECTION INPUT ;
    USE SIGNAL ;
    PORT
      LAYER M3 ;
        RECT 41.541 0.000 41.565 0.192 ;
    END
  END va_q[1]
  PIN va_q[2]
    DIRECTION INPUT ;
    USE SIGNAL ;
    PORT
      LAYER M5 ;
        RECT 41.856 0.000 41.880 0.192 ;
    END
  END va_q[2]
  PIN va_q[3]
    DIRECTION INPUT ;
    USE SIGNAL ;
    PORT
      LAYER M3 ;
        RECT 42.153 0.000 42.177 0.192 ;
    END
  END va_q[3]
  PIN va_q[4]
    DIRECTION INPUT ;
    USE SIGNAL ;
    PORT
      LAYER M5 ;
        RECT 42.480 0.000 42.504 0.192 ;
    END
  END va_q[4]
  PIN va_q[5]
    DIRECTION INPUT ;
    USE SIGNAL ;
    PORT
      LAYER M3 ;
        RECT 42.801 0.000 42.825 0.192 ;
    END
  END va_q[5]
  PIN va_q[6]
    DIRECTION INPUT ;
    USE SIGNAL ;
    PORT
      LAYER M5 ;
        RECT 43.104 0.000 43.128 0.192 ;
    END
  END va_q[6]
  PIN va_q[7]
    DIRECTION INPUT ;
    USE SIGNAL ;
    PORT
      LAYER M3 ;
        RECT 43.413 0.000 43.437 0.192 ;
    END
  END va_q[7]
  PIN va_q[8]
    DIRECTION INPUT ;
    USE SIGNAL ;
    PORT
      LAYER M5 ;
        RECT 43.728 0.000 43.752 0.192 ;
    END
  END va_q[8]
  PIN va_q[9]
    DIRECTION INPUT ;
    USE SIGNAL ;
    PORT
      LAYER M3 ;
        RECT 44.025 0.000 44.049 0.192 ;
    END
  END va_q[9]
  PIN va_q[10]
    DIRECTION INPUT ;
    USE SIGNAL ;
    PORT
      LAYER M5 ;
        RECT 44.352 0.000 44.376 0.192 ;
    END
  END va_q[10]
  PIN va_q[11]
    DIRECTION INPUT ;
    USE SIGNAL ;
    PORT
      LAYER M3 ;
        RECT 44.673 0.000 44.697 0.192 ;
    END
  END va_q[11]
  PIN va_q[12]
    DIRECTION INPUT ;
    USE SIGNAL ;
    PORT
      LAYER M5 ;
        RECT 44.976 0.000 45.000 0.192 ;
    END
  END va_q[12]
  PIN va_q[13]
    DIRECTION INPUT ;
    USE SIGNAL ;
    PORT
      LAYER M3 ;
        RECT 45.285 0.000 45.309 0.192 ;
    END
  END va_q[13]
  PIN va_q[14]
    DIRECTION INPUT ;
    USE SIGNAL ;
    PORT
      LAYER M5 ;
        RECT 45.600 0.000 45.624 0.192 ;
    END
  END va_q[14]
  PIN va_q[15]
    DIRECTION INPUT ;
    USE SIGNAL ;
    PORT
      LAYER M3 ;
        RECT 45.897 0.000 45.921 0.192 ;
    END
  END va_q[15]
  PIN va_q[16]
    DIRECTION INPUT ;
    USE SIGNAL ;
    PORT
      LAYER M5 ;
        RECT 46.224 0.000 46.248 0.192 ;
    END
  END va_q[16]
  PIN va_q[17]
    DIRECTION INPUT ;
    USE SIGNAL ;
    PORT
      LAYER M3 ;
        RECT 46.509 0.000 46.533 0.192 ;
    END
  END va_q[17]
  PIN va_q[18]
    DIRECTION INPUT ;
    USE SIGNAL ;
    PORT
      LAYER M5 ;
        RECT 46.848 0.000 46.872 0.192 ;
    END
  END va_q[18]
  PIN va_q[19]
    DIRECTION INPUT ;
    USE SIGNAL ;
    PORT
      LAYER M3 ;
        RECT 47.157 0.000 47.181 0.192 ;
    END
  END va_q[19]
  PIN va_q[20]
    DIRECTION INPUT ;
    USE SIGNAL ;
    PORT
      LAYER M5 ;
        RECT 47.472 0.000 47.496 0.192 ;
    END
  END va_q[20]
  PIN va_q[21]
    DIRECTION INPUT ;
    USE SIGNAL ;
    PORT
      LAYER M3 ;
        RECT 47.769 0.000 47.793 0.192 ;
    END
  END va_q[21]
  PIN va_q[22]
    DIRECTION INPUT ;
    USE SIGNAL ;
    PORT
      LAYER M5 ;
        RECT 48.096 0.000 48.120 0.192 ;
    END
  END va_q[22]
  PIN va_q[23]
    DIRECTION INPUT ;
    USE SIGNAL ;
    PORT
      LAYER M3 ;
        RECT 48.381 0.000 48.405 0.192 ;
    END
  END va_q[23]
  PIN va_q[24]
    DIRECTION INPUT ;
    USE SIGNAL ;
    PORT
      LAYER M5 ;
        RECT 48.720 0.000 48.744 0.192 ;
    END
  END va_q[24]
  PIN va_q[25]
    DIRECTION INPUT ;
    USE SIGNAL ;
    PORT
      LAYER M3 ;
        RECT 49.029 0.000 49.053 0.192 ;
    END
  END va_q[25]
  PIN va_q[26]
    DIRECTION INPUT ;
    USE SIGNAL ;
    PORT
      LAYER M5 ;
        RECT 49.344 0.000 49.368 0.192 ;
    END
  END va_q[26]
  PIN va_q[27]
    DIRECTION INPUT ;
    USE SIGNAL ;
    PORT
      LAYER M3 ;
        RECT 49.641 0.000 49.665 0.192 ;
    END
  END va_q[27]
  PIN va_q[28]
    DIRECTION INPUT ;
    USE SIGNAL ;
    PORT
      LAYER M5 ;
        RECT 49.968 0.000 49.992 0.192 ;
    END
  END va_q[28]
  PIN va_q[29]
    DIRECTION INPUT ;
    USE SIGNAL ;
    PORT
      LAYER M3 ;
        RECT 50.253 0.000 50.277 0.192 ;
    END
  END va_q[29]
  PIN va_q[30]
    DIRECTION INPUT ;
    USE SIGNAL ;
    PORT
      LAYER M5 ;
        RECT 50.592 0.000 50.616 0.192 ;
    END
  END va_q[30]
  PIN va_q[31]
    DIRECTION INPUT ;
    USE SIGNAL ;
    PORT
      LAYER M3 ;
        RECT 50.901 0.000 50.925 0.192 ;
    END
  END va_q[31]
  PIN vb_q[0]
    DIRECTION INPUT ;
    USE SIGNAL ;
    PORT
      LAYER M5 ;
        RECT 51.216 0.000 51.240 0.192 ;
    END
  END vb_q[0]
  PIN vb_q[1]
    DIRECTION INPUT ;
    USE SIGNAL ;
    PORT
      LAYER M3 ;
        RECT 51.513 0.000 51.537 0.192 ;
    END
  END vb_q[1]
  PIN vb_q[2]
    DIRECTION INPUT ;
    USE SIGNAL ;
    PORT
      LAYER M5 ;
        RECT 51.840 0.000 51.864 0.192 ;
    END
  END vb_q[2]
  PIN vb_q[3]
    DIRECTION INPUT ;
    USE SIGNAL ;
    PORT
      LAYER M3 ;
        RECT 52.125 0.000 52.149 0.192 ;
    END
  END vb_q[3]
  PIN vb_q[4]
    DIRECTION INPUT ;
    USE SIGNAL ;
    PORT
      LAYER M5 ;
        RECT 52.464 0.000 52.488 0.192 ;
    END
  END vb_q[4]
  PIN vb_q[5]
    DIRECTION INPUT ;
    USE SIGNAL ;
    PORT
      LAYER M3 ;
        RECT 52.737 0.000 52.761 0.192 ;
    END
  END vb_q[5]
  PIN vb_q[6]
    DIRECTION INPUT ;
    USE SIGNAL ;
    PORT
      LAYER M5 ;
        RECT 53.088 0.000 53.112 0.192 ;
    END
  END vb_q[6]
  PIN vb_q[7]
    DIRECTION INPUT ;
    USE SIGNAL ;
    PORT
      LAYER M3 ;
        RECT 53.385 0.000 53.409 0.192 ;
    END
  END vb_q[7]
  PIN vb_q[8]
    DIRECTION INPUT ;
    USE SIGNAL ;
    PORT
      LAYER M5 ;
        RECT 53.712 0.000 53.736 0.192 ;
    END
  END vb_q[8]
  PIN vb_q[9]
    DIRECTION INPUT ;
    USE SIGNAL ;
    PORT
      LAYER M3 ;
        RECT 53.997 0.000 54.021 0.192 ;
    END
  END vb_q[9]
  PIN vb_q[10]
    DIRECTION INPUT ;
    USE SIGNAL ;
    PORT
      LAYER M5 ;
        RECT 54.288 0.000 54.312 0.192 ;
    END
  END vb_q[10]
  PIN vb_q[11]
    DIRECTION INPUT ;
    USE SIGNAL ;
    PORT
      LAYER M3 ;
        RECT 54.609 0.000 54.633 0.192 ;
    END
  END vb_q[11]
  PIN vb_q[12]
    DIRECTION INPUT ;
    USE SIGNAL ;
    PORT
      LAYER M5 ;
        RECT 54.912 0.000 54.936 0.192 ;
    END
  END vb_q[12]
  PIN vb_q[13]
    DIRECTION INPUT ;
    USE SIGNAL ;
    PORT
      LAYER M3 ;
        RECT 55.257 0.000 55.281 0.192 ;
    END
  END vb_q[13]
  PIN vb_q[14]
    DIRECTION INPUT ;
    USE SIGNAL ;
    PORT
      LAYER M5 ;
        RECT 55.536 0.000 55.560 0.192 ;
    END
  END vb_q[14]
  PIN vb_q[15]
    DIRECTION INPUT ;
    USE SIGNAL ;
    PORT
      LAYER M3 ;
        RECT 55.869 0.000 55.893 0.192 ;
    END
  END vb_q[15]
  PIN vb_q[16]
    DIRECTION INPUT ;
    USE SIGNAL ;
    PORT
      LAYER M5 ;
        RECT 56.160 0.000 56.184 0.192 ;
    END
  END vb_q[16]
  PIN vb_q[17]
    DIRECTION INPUT ;
    USE SIGNAL ;
    PORT
      LAYER M3 ;
        RECT 56.481 0.000 56.505 0.192 ;
    END
  END vb_q[17]
  PIN vb_q[18]
    DIRECTION INPUT ;
    USE SIGNAL ;
    PORT
      LAYER M5 ;
        RECT 56.784 0.000 56.808 0.192 ;
    END
  END vb_q[18]
  PIN vb_q[19]
    DIRECTION INPUT ;
    USE SIGNAL ;
    PORT
      LAYER M3 ;
        RECT 57.129 0.000 57.153 0.192 ;
    END
  END vb_q[19]
  PIN vb_q[20]
    DIRECTION INPUT ;
    USE SIGNAL ;
    PORT
      LAYER M5 ;
        RECT 57.408 0.000 57.432 0.192 ;
    END
  END vb_q[20]
  PIN vb_q[21]
    DIRECTION INPUT ;
    USE SIGNAL ;
    PORT
      LAYER M3 ;
        RECT 57.741 0.000 57.765 0.192 ;
    END
  END vb_q[21]
  PIN vb_q[22]
    DIRECTION INPUT ;
    USE SIGNAL ;
    PORT
      LAYER M5 ;
        RECT 58.032 0.000 58.056 0.192 ;
    END
  END vb_q[22]
  PIN vb_q[23]
    DIRECTION INPUT ;
    USE SIGNAL ;
    PORT
      LAYER M3 ;
        RECT 58.353 0.000 58.377 0.192 ;
    END
  END vb_q[23]
  PIN vb_q[24]
    DIRECTION INPUT ;
    USE SIGNAL ;
    PORT
      LAYER M5 ;
        RECT 58.656 0.000 58.680 0.192 ;
    END
  END vb_q[24]
  PIN vb_q[25]
    DIRECTION INPUT ;
    USE SIGNAL ;
    PORT
      LAYER M3 ;
        RECT 58.965 0.000 58.989 0.192 ;
    END
  END vb_q[25]
  PIN vb_q[26]
    DIRECTION INPUT ;
    USE SIGNAL ;
    PORT
      LAYER M5 ;
        RECT 59.280 0.000 59.304 0.192 ;
    END
  END vb_q[26]
  PIN vb_q[27]
    DIRECTION INPUT ;
    USE SIGNAL ;
    PORT
      LAYER M3 ;
        RECT 59.613 0.000 59.637 0.192 ;
    END
  END vb_q[27]
  PIN vb_q[28]
    DIRECTION INPUT ;
    USE SIGNAL ;
    PORT
      LAYER M5 ;
        RECT 59.904 0.000 59.928 0.192 ;
    END
  END vb_q[28]
  PIN vb_q[29]
    DIRECTION INPUT ;
    USE SIGNAL ;
    PORT
      LAYER M3 ;
        RECT 60.225 0.000 60.249 0.192 ;
    END
  END vb_q[29]
  PIN vb_q[30]
    DIRECTION INPUT ;
    USE SIGNAL ;
    PORT
      LAYER M5 ;
        RECT 60.528 0.000 60.552 0.192 ;
    END
  END vb_q[30]
  PIN vb_q[31]
    DIRECTION INPUT ;
    USE SIGNAL ;
    PORT
      LAYER M3 ;
        RECT 60.837 0.000 60.861 0.192 ;
    END
  END vb_q[31]
  PIN vc_q[0]
    DIRECTION INPUT ;
    USE SIGNAL ;
    PORT
      LAYER M5 ;
        RECT 61.152 0.000 61.176 0.192 ;
    END
  END vc_q[0]
  PIN vc_q[1]
    DIRECTION INPUT ;
    USE SIGNAL ;
    PORT
      LAYER M3 ;
        RECT 61.485 0.000 61.509 0.192 ;
    END
  END vc_q[1]
  PIN vc_q[2]
    DIRECTION INPUT ;
    USE SIGNAL ;
    PORT
      LAYER M5 ;
        RECT 61.776 0.000 61.800 0.192 ;
    END
  END vc_q[2]
  PIN vc_q[3]
    DIRECTION INPUT ;
    USE SIGNAL ;
    PORT
      LAYER M3 ;
        RECT 62.097 0.000 62.121 0.192 ;
    END
  END vc_q[3]
  PIN vc_q[4]
    DIRECTION INPUT ;
    USE SIGNAL ;
    PORT
      LAYER M5 ;
        RECT 62.400 0.000 62.424 0.192 ;
    END
  END vc_q[4]
  PIN vc_q[5]
    DIRECTION INPUT ;
    USE SIGNAL ;
    PORT
      LAYER M3 ;
        RECT 62.709 0.000 62.733 0.192 ;
    END
  END vc_q[5]
  PIN vc_q[6]
    DIRECTION INPUT ;
    USE SIGNAL ;
    PORT
      LAYER M5 ;
        RECT 63.024 0.000 63.048 0.192 ;
    END
  END vc_q[6]
  PIN vc_q[7]
    DIRECTION INPUT ;
    USE SIGNAL ;
    PORT
      LAYER M3 ;
        RECT 63.357 0.000 63.381 0.192 ;
    END
  END vc_q[7]
  PIN vc_q[8]
    DIRECTION INPUT ;
    USE SIGNAL ;
    PORT
      LAYER M5 ;
        RECT 63.648 0.000 63.672 0.192 ;
    END
  END vc_q[8]
  PIN vc_q[9]
    DIRECTION INPUT ;
    USE SIGNAL ;
    PORT
      LAYER M3 ;
        RECT 63.969 0.000 63.993 0.192 ;
    END
  END vc_q[9]
  PIN vc_q[10]
    DIRECTION INPUT ;
    USE SIGNAL ;
    PORT
      LAYER M5 ;
        RECT 64.272 0.000 64.296 0.192 ;
    END
  END vc_q[10]
  PIN vc_q[11]
    DIRECTION INPUT ;
    USE SIGNAL ;
    PORT
      LAYER M3 ;
        RECT 64.581 0.000 64.605 0.192 ;
    END
  END vc_q[11]
  PIN vc_q[12]
    DIRECTION INPUT ;
    USE SIGNAL ;
    PORT
      LAYER M5 ;
        RECT 64.896 0.000 64.920 0.192 ;
    END
  END vc_q[12]
  PIN vc_q[13]
    DIRECTION INPUT ;
    USE SIGNAL ;
    PORT
      LAYER M3 ;
        RECT 65.229 0.000 65.253 0.192 ;
    END
  END vc_q[13]
  PIN vc_q[14]
    DIRECTION INPUT ;
    USE SIGNAL ;
    PORT
      LAYER M5 ;
        RECT 65.520 0.000 65.544 0.192 ;
    END
  END vc_q[14]
  PIN vc_q[15]
    DIRECTION INPUT ;
    USE SIGNAL ;
    PORT
      LAYER M3 ;
        RECT 65.841 0.000 65.865 0.192 ;
    END
  END vc_q[15]
  PIN vc_q[16]
    DIRECTION INPUT ;
    USE SIGNAL ;
    PORT
      LAYER M5 ;
        RECT 66.144 0.000 66.168 0.192 ;
    END
  END vc_q[16]
  PIN vc_q[17]
    DIRECTION INPUT ;
    USE SIGNAL ;
    PORT
      LAYER M3 ;
        RECT 66.453 0.000 66.477 0.192 ;
    END
  END vc_q[17]
  PIN vc_q[18]
    DIRECTION INPUT ;
    USE SIGNAL ;
    PORT
      LAYER M5 ;
        RECT 66.768 0.000 66.792 0.192 ;
    END
  END vc_q[18]
  PIN vc_q[19]
    DIRECTION INPUT ;
    USE SIGNAL ;
    PORT
      LAYER M3 ;
        RECT 67.065 0.000 67.089 0.192 ;
    END
  END vc_q[19]
  PIN vc_q[20]
    DIRECTION INPUT ;
    USE SIGNAL ;
    PORT
      LAYER M5 ;
        RECT 67.392 0.000 67.416 0.192 ;
    END
  END vc_q[20]
  PIN vc_q[21]
    DIRECTION INPUT ;
    USE SIGNAL ;
    PORT
      LAYER M3 ;
        RECT 67.713 0.000 67.737 0.192 ;
    END
  END vc_q[21]
  PIN vc_q[22]
    DIRECTION INPUT ;
    USE SIGNAL ;
    PORT
      LAYER M5 ;
        RECT 68.016 0.000 68.040 0.192 ;
    END
  END vc_q[22]
  PIN vc_q[23]
    DIRECTION INPUT ;
    USE SIGNAL ;
    PORT
      LAYER M3 ;
        RECT 68.325 0.000 68.349 0.192 ;
    END
  END vc_q[23]
  PIN vc_q[24]
    DIRECTION INPUT ;
    USE SIGNAL ;
    PORT
      LAYER M5 ;
        RECT 68.640 0.000 68.664 0.192 ;
    END
  END vc_q[24]
  PIN vc_q[25]
    DIRECTION INPUT ;
    USE SIGNAL ;
    PORT
      LAYER M3 ;
        RECT 68.937 0.000 68.961 0.192 ;
    END
  END vc_q[25]
  PIN vc_q[26]
    DIRECTION INPUT ;
    USE SIGNAL ;
    PORT
      LAYER M5 ;
        RECT 69.264 0.000 69.288 0.192 ;
    END
  END vc_q[26]
  PIN vc_q[27]
    DIRECTION INPUT ;
    USE SIGNAL ;
    PORT
      LAYER M3 ;
        RECT 69.585 0.000 69.609 0.192 ;
    END
  END vc_q[27]
  PIN vc_q[28]
    DIRECTION INPUT ;
    USE SIGNAL ;
    PORT
      LAYER M5 ;
        RECT 69.888 0.000 69.912 0.192 ;
    END
  END vc_q[28]
  PIN vc_q[29]
    DIRECTION INPUT ;
    USE SIGNAL ;
    PORT
      LAYER M3 ;
        RECT 70.197 0.000 70.221 0.192 ;
    END
  END vc_q[29]
  PIN vc_q[30]
    DIRECTION INPUT ;
    USE SIGNAL ;
    PORT
      LAYER M5 ;
        RECT 70.512 0.000 70.536 0.192 ;
    END
  END vc_q[30]
  PIN vc_q[31]
    DIRECTION INPUT ;
    USE SIGNAL ;
    PORT
      LAYER M3 ;
        RECT 70.809 0.000 70.833 0.192 ;
    END
  END vc_q[31]
  PIN wrom_q[0]
    DIRECTION INPUT ;
    USE SIGNAL ;
    PORT
      LAYER M5 ;
        RECT 71.136 0.000 71.160 0.192 ;
    END
  END wrom_q[0]
  PIN wrom_q[1]
    DIRECTION INPUT ;
    USE SIGNAL ;
    PORT
      LAYER M3 ;
        RECT 71.457 0.000 71.481 0.192 ;
    END
  END wrom_q[1]
  PIN wrom_q[2]
    DIRECTION INPUT ;
    USE SIGNAL ;
    PORT
      LAYER M5 ;
        RECT 71.760 0.000 71.784 0.192 ;
    END
  END wrom_q[2]
  PIN wrom_q[3]
    DIRECTION INPUT ;
    USE SIGNAL ;
    PORT
      LAYER M3 ;
        RECT 72.069 0.000 72.093 0.192 ;
    END
  END wrom_q[3]
  PIN wrom_q[4]
    DIRECTION INPUT ;
    USE SIGNAL ;
    PORT
      LAYER M5 ;
        RECT 72.384 0.000 72.408 0.192 ;
    END
  END wrom_q[4]
  PIN wrom_q[5]
    DIRECTION INPUT ;
    USE SIGNAL ;
    PORT
      LAYER M3 ;
        RECT 72.681 0.000 72.705 0.192 ;
    END
  END wrom_q[5]
  PIN wrom_q[6]
    DIRECTION INPUT ;
    USE SIGNAL ;
    PORT
      LAYER M5 ;
        RECT 73.008 0.000 73.032 0.192 ;
    END
  END wrom_q[6]
  PIN wrom_q[7]
    DIRECTION INPUT ;
    USE SIGNAL ;
    PORT
      LAYER M3 ;
        RECT 73.293 0.000 73.317 0.192 ;
    END
  END wrom_q[7]
  PIN wrom_q[8]
    DIRECTION INPUT ;
    USE SIGNAL ;
    PORT
      LAYER M5 ;
        RECT 73.632 0.000 73.656 0.192 ;
    END
  END wrom_q[8]
  PIN wrom_q[9]
    DIRECTION INPUT ;
    USE SIGNAL ;
    PORT
      LAYER M3 ;
        RECT 73.941 0.000 73.965 0.192 ;
    END
  END wrom_q[9]
  PIN wrom_q[10]
    DIRECTION INPUT ;
    USE SIGNAL ;
    PORT
      LAYER M5 ;
        RECT 74.256 0.000 74.280 0.192 ;
    END
  END wrom_q[10]
  PIN wrom_q[11]
    DIRECTION INPUT ;
    USE SIGNAL ;
    PORT
      LAYER M3 ;
        RECT 74.553 0.000 74.577 0.192 ;
    END
  END wrom_q[11]
  PIN wrom_q[12]
    DIRECTION INPUT ;
    USE SIGNAL ;
    PORT
      LAYER M5 ;
        RECT 74.880 0.000 74.904 0.192 ;
    END
  END wrom_q[12]
  PIN wrom_q[13]
    DIRECTION INPUT ;
    USE SIGNAL ;
    PORT
      LAYER M3 ;
        RECT 75.165 0.000 75.189 0.192 ;
    END
  END wrom_q[13]
  PIN wrom_q[14]
    DIRECTION INPUT ;
    USE SIGNAL ;
    PORT
      LAYER M5 ;
        RECT 75.504 0.000 75.528 0.192 ;
    END
  END wrom_q[14]
  PIN wrom_q[15]
    DIRECTION INPUT ;
    USE SIGNAL ;
    PORT
      LAYER M3 ;
        RECT 75.813 0.000 75.837 0.192 ;
    END
  END wrom_q[15]
  PIN wrom_q[16]
    DIRECTION INPUT ;
    USE SIGNAL ;
    PORT
      LAYER M5 ;
        RECT 76.128 0.000 76.152 0.192 ;
    END
  END wrom_q[16]
  PIN wrom_q[17]
    DIRECTION INPUT ;
    USE SIGNAL ;
    PORT
      LAYER M3 ;
        RECT 76.425 0.000 76.449 0.192 ;
    END
  END wrom_q[17]
  PIN wrom_q[18]
    DIRECTION INPUT ;
    USE SIGNAL ;
    PORT
      LAYER M5 ;
        RECT 76.752 0.000 76.776 0.192 ;
    END
  END wrom_q[18]
  PIN wrom_q[19]
    DIRECTION INPUT ;
    USE SIGNAL ;
    PORT
      LAYER M3 ;
        RECT 77.037 0.000 77.061 0.192 ;
    END
  END wrom_q[19]
  PIN wrom_q[20]
    DIRECTION INPUT ;
    USE SIGNAL ;
    PORT
      LAYER M5 ;
        RECT 77.376 0.000 77.400 0.192 ;
    END
  END wrom_q[20]
  PIN wrom_q[21]
    DIRECTION INPUT ;
    USE SIGNAL ;
    PORT
      LAYER M3 ;
        RECT 77.685 0.000 77.709 0.192 ;
    END
  END wrom_q[21]
  PIN wrom_q[22]
    DIRECTION INPUT ;
    USE SIGNAL ;
    PORT
      LAYER M5 ;
        RECT 78.000 0.000 78.024 0.192 ;
    END
  END wrom_q[22]
  PIN wrom_q[23]
    DIRECTION INPUT ;
    USE SIGNAL ;
    PORT
      LAYER M3 ;
        RECT 78.297 0.000 78.321 0.192 ;
    END
  END wrom_q[23]
  PIN wrom_q[24]
    DIRECTION INPUT ;
    USE SIGNAL ;
    PORT
      LAYER M5 ;
        RECT 78.624 0.000 78.648 0.192 ;
    END
  END wrom_q[24]
  PIN wrom_q[25]
    DIRECTION INPUT ;
    USE SIGNAL ;
    PORT
      LAYER M3 ;
        RECT 78.909 0.000 78.933 0.192 ;
    END
  END wrom_q[25]
  PIN wrom_q[26]
    DIRECTION INPUT ;
    USE SIGNAL ;
    PORT
      LAYER M5 ;
        RECT 79.248 0.000 79.272 0.192 ;
    END
  END wrom_q[26]
  PIN wrom_q[27]
    DIRECTION INPUT ;
    USE SIGNAL ;
    PORT
      LAYER M3 ;
        RECT 79.521 0.000 79.545 0.192 ;
    END
  END wrom_q[27]
  PIN wrom_q[28]
    DIRECTION INPUT ;
    USE SIGNAL ;
    PORT
      LAYER M5 ;
        RECT 79.872 0.000 79.896 0.192 ;
    END
  END wrom_q[28]
  PIN wrom_q[29]
    DIRECTION INPUT ;
    USE SIGNAL ;
    PORT
      LAYER M3 ;
        RECT 80.169 0.000 80.193 0.192 ;
    END
  END wrom_q[29]
  PIN wrom_q[30]
    DIRECTION INPUT ;
    USE SIGNAL ;
    PORT
      LAYER M5 ;
        RECT 80.448 0.000 80.472 0.192 ;
    END
  END wrom_q[30]
  PIN wrom_q[31]
    DIRECTION INPUT ;
    USE SIGNAL ;
    PORT
      LAYER M3 ;
        RECT 80.781 0.000 80.805 0.192 ;
    END
  END wrom_q[31]
  PIN wrom_q[32]
    DIRECTION INPUT ;
    USE SIGNAL ;
    PORT
      LAYER M5 ;
        RECT 81.072 0.000 81.096 0.192 ;
    END
  END wrom_q[32]
  PIN wrom_q[33]
    DIRECTION INPUT ;
    USE SIGNAL ;
    PORT
      LAYER M3 ;
        RECT 81.393 0.000 81.417 0.192 ;
    END
  END wrom_q[33]
  PIN wrom_q[34]
    DIRECTION INPUT ;
    USE SIGNAL ;
    PORT
      LAYER M5 ;
        RECT 81.696 0.000 81.720 0.192 ;
    END
  END wrom_q[34]
  PIN wrom_q[35]
    DIRECTION INPUT ;
    USE SIGNAL ;
    PORT
      LAYER M3 ;
        RECT 82.041 0.000 82.065 0.192 ;
    END
  END wrom_q[35]
  PIN wrom_q[36]
    DIRECTION INPUT ;
    USE SIGNAL ;
    PORT
      LAYER M5 ;
        RECT 82.320 0.000 82.344 0.192 ;
    END
  END wrom_q[36]
  PIN wrom_q[37]
    DIRECTION INPUT ;
    USE SIGNAL ;
    PORT
      LAYER M3 ;
        RECT 82.653 0.000 82.677 0.192 ;
    END
  END wrom_q[37]
  PIN wrom_q[38]
    DIRECTION INPUT ;
    USE SIGNAL ;
    PORT
      LAYER M5 ;
        RECT 82.944 0.000 82.968 0.192 ;
    END
  END wrom_q[38]
  PIN wrom_q[39]
    DIRECTION INPUT ;
    USE SIGNAL ;
    PORT
      LAYER M3 ;
        RECT 83.265 0.000 83.289 0.192 ;
    END
  END wrom_q[39]
  PIN wrom_q[40]
    DIRECTION INPUT ;
    USE SIGNAL ;
    PORT
      LAYER M5 ;
        RECT 83.568 0.000 83.592 0.192 ;
    END
  END wrom_q[40]
  PIN wrom_q[41]
    DIRECTION INPUT ;
    USE SIGNAL ;
    PORT
      LAYER M3 ;
        RECT 83.913 0.000 83.937 0.192 ;
    END
  END wrom_q[41]
  PIN wrom_q[42]
    DIRECTION INPUT ;
    USE SIGNAL ;
    PORT
      LAYER M5 ;
        RECT 84.192 0.000 84.216 0.192 ;
    END
  END wrom_q[42]
  PIN wrom_q[43]
    DIRECTION INPUT ;
    USE SIGNAL ;
    PORT
      LAYER M3 ;
        RECT 84.525 0.000 84.549 0.192 ;
    END
  END wrom_q[43]
  PIN wrom_q[44]
    DIRECTION INPUT ;
    USE SIGNAL ;
    PORT
      LAYER M5 ;
        RECT 84.816 0.000 84.840 0.192 ;
    END
  END wrom_q[44]
  PIN wrom_q[45]
    DIRECTION INPUT ;
    USE SIGNAL ;
    PORT
      LAYER M3 ;
        RECT 85.137 0.000 85.161 0.192 ;
    END
  END wrom_q[45]
  PIN wrom_q[46]
    DIRECTION INPUT ;
    USE SIGNAL ;
    PORT
      LAYER M5 ;
        RECT 85.440 0.000 85.464 0.192 ;
    END
  END wrom_q[46]
  PIN wrom_q[47]
    DIRECTION INPUT ;
    USE SIGNAL ;
    PORT
      LAYER M3 ;
        RECT 85.749 0.000 85.773 0.192 ;
    END
  END wrom_q[47]
  PIN wrom_q[48]
    DIRECTION INPUT ;
    USE SIGNAL ;
    PORT
      LAYER M5 ;
        RECT 86.064 0.000 86.088 0.192 ;
    END
  END wrom_q[48]
  PIN wrom_q[49]
    DIRECTION INPUT ;
    USE SIGNAL ;
    PORT
      LAYER M3 ;
        RECT 86.397 0.000 86.421 0.192 ;
    END
  END wrom_q[49]
  PIN wrom_q[50]
    DIRECTION INPUT ;
    USE SIGNAL ;
    PORT
      LAYER M5 ;
        RECT 86.688 0.000 86.712 0.192 ;
    END
  END wrom_q[50]
  PIN wrom_q[51]
    DIRECTION INPUT ;
    USE SIGNAL ;
    PORT
      LAYER M3 ;
        RECT 87.009 0.000 87.033 0.192 ;
    END
  END wrom_q[51]
  PIN wrom_q[52]
    DIRECTION INPUT ;
    USE SIGNAL ;
    PORT
      LAYER M5 ;
        RECT 87.312 0.000 87.336 0.192 ;
    END
  END wrom_q[52]
  PIN wrom_q[53]
    DIRECTION INPUT ;
    USE SIGNAL ;
    PORT
      LAYER M3 ;
        RECT 87.621 0.000 87.645 0.192 ;
    END
  END wrom_q[53]
  PIN wrom_q[54]
    DIRECTION INPUT ;
    USE SIGNAL ;
    PORT
      LAYER M5 ;
        RECT 87.936 0.000 87.960 0.192 ;
    END
  END wrom_q[54]
  PIN wrom_q[55]
    DIRECTION INPUT ;
    USE SIGNAL ;
    PORT
      LAYER M3 ;
        RECT 88.269 0.000 88.293 0.192 ;
    END
  END wrom_q[55]
  PIN wrom_q[56]
    DIRECTION INPUT ;
    USE SIGNAL ;
    PORT
      LAYER M5 ;
        RECT 88.560 0.000 88.584 0.192 ;
    END
  END wrom_q[56]
  PIN wrom_q[57]
    DIRECTION INPUT ;
    USE SIGNAL ;
    PORT
      LAYER M3 ;
        RECT 88.881 0.000 88.905 0.192 ;
    END
  END wrom_q[57]
  PIN wrom_q[58]
    DIRECTION INPUT ;
    USE SIGNAL ;
    PORT
      LAYER M5 ;
        RECT 89.184 0.000 89.208 0.192 ;
    END
  END wrom_q[58]
  PIN wrom_q[59]
    DIRECTION INPUT ;
    USE SIGNAL ;
    PORT
      LAYER M3 ;
        RECT 89.493 0.000 89.517 0.192 ;
    END
  END wrom_q[59]
  PIN wrom_q[60]
    DIRECTION INPUT ;
    USE SIGNAL ;
    PORT
      LAYER M5 ;
        RECT 89.808 0.000 89.832 0.192 ;
    END
  END wrom_q[60]
  PIN wrom_q[61]
    DIRECTION INPUT ;
    USE SIGNAL ;
    PORT
      LAYER M3 ;
        RECT 90.141 0.000 90.165 0.192 ;
    END
  END wrom_q[61]
  PIN wrom_q[62]
    DIRECTION INPUT ;
    USE SIGNAL ;
    PORT
      LAYER M5 ;
        RECT 90.432 0.000 90.456 0.192 ;
    END
  END wrom_q[62]
  PIN wrom_q[63]
    DIRECTION INPUT ;
    USE SIGNAL ;
    PORT
      LAYER M3 ;
        RECT 90.753 0.000 90.777 0.192 ;
    END
  END wrom_q[63]
  PIN wrom_q[64]
    DIRECTION INPUT ;
    USE SIGNAL ;
    PORT
      LAYER M5 ;
        RECT 91.056 0.000 91.080 0.192 ;
    END
  END wrom_q[64]
  PIN wrom_q[65]
    DIRECTION INPUT ;
    USE SIGNAL ;
    PORT
      LAYER M3 ;
        RECT 91.365 0.000 91.389 0.192 ;
    END
  END wrom_q[65]
  PIN wrom_q[66]
    DIRECTION INPUT ;
    USE SIGNAL ;
    PORT
      LAYER M5 ;
        RECT 91.680 0.000 91.704 0.192 ;
    END
  END wrom_q[66]
  PIN wrom_q[67]
    DIRECTION INPUT ;
    USE SIGNAL ;
    PORT
      LAYER M3 ;
        RECT 91.977 0.000 92.001 0.192 ;
    END
  END wrom_q[67]
  PIN wrom_q[68]
    DIRECTION INPUT ;
    USE SIGNAL ;
    PORT
      LAYER M5 ;
        RECT 92.304 0.000 92.328 0.192 ;
    END
  END wrom_q[68]
  PIN wrom_q[69]
    DIRECTION INPUT ;
    USE SIGNAL ;
    PORT
      LAYER M3 ;
        RECT 92.625 0.000 92.649 0.192 ;
    END
  END wrom_q[69]
  PIN wrom_q[70]
    DIRECTION INPUT ;
    USE SIGNAL ;
    PORT
      LAYER M5 ;
        RECT 92.928 0.000 92.952 0.192 ;
    END
  END wrom_q[70]
  PIN wrom_q[71]
    DIRECTION INPUT ;
    USE SIGNAL ;
    PORT
      LAYER M3 ;
        RECT 93.237 0.000 93.261 0.192 ;
    END
  END wrom_q[71]
  PIN wrom_q[72]
    DIRECTION INPUT ;
    USE SIGNAL ;
    PORT
      LAYER M5 ;
        RECT 93.552 0.000 93.576 0.192 ;
    END
  END wrom_q[72]
  PIN wrom_q[73]
    DIRECTION INPUT ;
    USE SIGNAL ;
    PORT
      LAYER M3 ;
        RECT 93.849 0.000 93.873 0.192 ;
    END
  END wrom_q[73]
  PIN wrom_q[74]
    DIRECTION INPUT ;
    USE SIGNAL ;
    PORT
      LAYER M5 ;
        RECT 94.176 0.000 94.200 0.192 ;
    END
  END wrom_q[74]
  PIN wrom_q[75]
    DIRECTION INPUT ;
    USE SIGNAL ;
    PORT
      LAYER M3 ;
        RECT 94.497 0.000 94.521 0.192 ;
    END
  END wrom_q[75]
  PIN wrom_q[76]
    DIRECTION INPUT ;
    USE SIGNAL ;
    PORT
      LAYER M5 ;
        RECT 94.800 0.000 94.824 0.192 ;
    END
  END wrom_q[76]
  PIN wrom_q[77]
    DIRECTION INPUT ;
    USE SIGNAL ;
    PORT
      LAYER M3 ;
        RECT 95.109 0.000 95.133 0.192 ;
    END
  END wrom_q[77]
  PIN wrom_q[78]
    DIRECTION INPUT ;
    USE SIGNAL ;
    PORT
      LAYER M5 ;
        RECT 95.424 0.000 95.448 0.192 ;
    END
  END wrom_q[78]
  PIN wrom_q[79]
    DIRECTION INPUT ;
    USE SIGNAL ;
    PORT
      LAYER M3 ;
        RECT 95.721 0.000 95.745 0.192 ;
    END
  END wrom_q[79]
  PIN wrom_q[80]
    DIRECTION INPUT ;
    USE SIGNAL ;
    PORT
      LAYER M5 ;
        RECT 96.048 0.000 96.072 0.192 ;
    END
  END wrom_q[80]
  PIN wrom_q[81]
    DIRECTION INPUT ;
    USE SIGNAL ;
    PORT
      LAYER M3 ;
        RECT 96.369 0.000 96.393 0.192 ;
    END
  END wrom_q[81]
  PIN wrom_q[82]
    DIRECTION INPUT ;
    USE SIGNAL ;
    PORT
      LAYER M5 ;
        RECT 96.672 0.000 96.696 0.192 ;
    END
  END wrom_q[82]
  PIN wrom_q[83]
    DIRECTION INPUT ;
    USE SIGNAL ;
    PORT
      LAYER M3 ;
        RECT 96.981 0.000 97.005 0.192 ;
    END
  END wrom_q[83]
  PIN wrom_q[84]
    DIRECTION INPUT ;
    USE SIGNAL ;
    PORT
      LAYER M5 ;
        RECT 97.296 0.000 97.320 0.192 ;
    END
  END wrom_q[84]
  PIN wrom_q[85]
    DIRECTION INPUT ;
    USE SIGNAL ;
    PORT
      LAYER M3 ;
        RECT 97.593 0.000 97.617 0.192 ;
    END
  END wrom_q[85]
  PIN wrom_q[86]
    DIRECTION INPUT ;
    USE SIGNAL ;
    PORT
      LAYER M5 ;
        RECT 97.920 0.000 97.944 0.192 ;
    END
  END wrom_q[86]
  PIN wrom_q[87]
    DIRECTION INPUT ;
    USE SIGNAL ;
    PORT
      LAYER M3 ;
        RECT 98.205 0.000 98.229 0.192 ;
    END
  END wrom_q[87]
  PIN wrom_q[88]
    DIRECTION INPUT ;
    USE SIGNAL ;
    PORT
      LAYER M5 ;
        RECT 98.544 0.000 98.568 0.192 ;
    END
  END wrom_q[88]
  PIN wrom_q[89]
    DIRECTION INPUT ;
    USE SIGNAL ;
    PORT
      LAYER M3 ;
        RECT 98.853 0.000 98.877 0.192 ;
    END
  END wrom_q[89]
  PIN wrom_q[90]
    DIRECTION INPUT ;
    USE SIGNAL ;
    PORT
      LAYER M5 ;
        RECT 99.168 0.000 99.192 0.192 ;
    END
  END wrom_q[90]
  PIN wrom_q[91]
    DIRECTION INPUT ;
    USE SIGNAL ;
    PORT
      LAYER M3 ;
        RECT 99.465 0.000 99.489 0.192 ;
    END
  END wrom_q[91]
  PIN wrom_q[92]
    DIRECTION INPUT ;
    USE SIGNAL ;
    PORT
      LAYER M5 ;
        RECT 99.792 0.000 99.816 0.192 ;
    END
  END wrom_q[92]
  PIN wrom_q[93]
    DIRECTION INPUT ;
    USE SIGNAL ;
    PORT
      LAYER M3 ;
        RECT 100.077 0.000 100.101 0.192 ;
    END
  END wrom_q[93]
  PIN wrom_q[94]
    DIRECTION INPUT ;
    USE SIGNAL ;
    PORT
      LAYER M5 ;
        RECT 100.416 0.000 100.440 0.192 ;
    END
  END wrom_q[94]
  PIN wrom_q[95]
    DIRECTION INPUT ;
    USE SIGNAL ;
    PORT
      LAYER M3 ;
        RECT 100.725 0.000 100.749 0.192 ;
    END
  END wrom_q[95]
  PIN wrom_q[96]
    DIRECTION INPUT ;
    USE SIGNAL ;
    PORT
      LAYER M5 ;
        RECT 101.040 0.000 101.064 0.192 ;
    END
  END wrom_q[96]
  PIN wrom_q[97]
    DIRECTION INPUT ;
    USE SIGNAL ;
    PORT
      LAYER M3 ;
        RECT 101.337 0.000 101.361 0.192 ;
    END
  END wrom_q[97]
  PIN wrom_q[98]
    DIRECTION INPUT ;
    USE SIGNAL ;
    PORT
      LAYER M5 ;
        RECT 101.664 0.000 101.688 0.192 ;
    END
  END wrom_q[98]
  PIN wrom_q[99]
    DIRECTION INPUT ;
    USE SIGNAL ;
    PORT
      LAYER M3 ;
        RECT 101.949 0.000 101.973 0.192 ;
    END
  END wrom_q[99]
  PIN wrom_q[100]
    DIRECTION INPUT ;
    USE SIGNAL ;
    PORT
      LAYER M5 ;
        RECT 102.288 0.000 102.312 0.192 ;
    END
  END wrom_q[100]
  PIN wrom_q[101]
    DIRECTION INPUT ;
    USE SIGNAL ;
    PORT
      LAYER M3 ;
        RECT 102.597 0.000 102.621 0.192 ;
    END
  END wrom_q[101]
  PIN wrom_q[102]
    DIRECTION INPUT ;
    USE SIGNAL ;
    PORT
      LAYER M5 ;
        RECT 102.912 0.000 102.936 0.192 ;
    END
  END wrom_q[102]
  PIN wrom_q[103]
    DIRECTION INPUT ;
    USE SIGNAL ;
    PORT
      LAYER M3 ;
        RECT 103.209 0.000 103.233 0.192 ;
    END
  END wrom_q[103]
  PIN wrom_q[104]
    DIRECTION INPUT ;
    USE SIGNAL ;
    PORT
      LAYER M5 ;
        RECT 103.536 0.000 103.560 0.192 ;
    END
  END wrom_q[104]
  PIN wrom_q[105]
    DIRECTION INPUT ;
    USE SIGNAL ;
    PORT
      LAYER M3 ;
        RECT 103.821 0.000 103.845 0.192 ;
    END
  END wrom_q[105]
  PIN wrom_q[106]
    DIRECTION INPUT ;
    USE SIGNAL ;
    PORT
      LAYER M5 ;
        RECT 104.160 0.000 104.184 0.192 ;
    END
  END wrom_q[106]
  PIN wrom_q[107]
    DIRECTION INPUT ;
    USE SIGNAL ;
    PORT
      LAYER M3 ;
        RECT 104.433 0.000 104.457 0.192 ;
    END
  END wrom_q[107]
  PIN wrom_q[108]
    DIRECTION INPUT ;
    USE SIGNAL ;
    PORT
      LAYER M5 ;
        RECT 104.784 0.000 104.808 0.192 ;
    END
  END wrom_q[108]
  PIN wrom_q[109]
    DIRECTION INPUT ;
    USE SIGNAL ;
    PORT
      LAYER M3 ;
        RECT 105.081 0.000 105.105 0.192 ;
    END
  END wrom_q[109]
  PIN wrom_q[110]
    DIRECTION INPUT ;
    USE SIGNAL ;
    PORT
      LAYER M5 ;
        RECT 105.408 0.000 105.432 0.192 ;
    END
  END wrom_q[110]
  PIN wrom_q[111]
    DIRECTION INPUT ;
    USE SIGNAL ;
    PORT
      LAYER M3 ;
        RECT 105.693 0.000 105.717 0.192 ;
    END
  END wrom_q[111]
  PIN wrom_q[112]
    DIRECTION INPUT ;
    USE SIGNAL ;
    PORT
      LAYER M5 ;
        RECT 105.984 0.000 106.008 0.192 ;
    END
  END wrom_q[112]
  PIN wrom_q[113]
    DIRECTION INPUT ;
    USE SIGNAL ;
    PORT
      LAYER M3 ;
        RECT 106.305 0.000 106.329 0.192 ;
    END
  END wrom_q[113]
  PIN wrom_q[114]
    DIRECTION INPUT ;
    USE SIGNAL ;
    PORT
      LAYER M5 ;
        RECT 106.608 0.000 106.632 0.192 ;
    END
  END wrom_q[114]
  PIN wrom_q[115]
    DIRECTION INPUT ;
    USE SIGNAL ;
    PORT
      LAYER M3 ;
        RECT 106.953 0.000 106.977 0.192 ;
    END
  END wrom_q[115]
  PIN wrom_q[116]
    DIRECTION INPUT ;
    USE SIGNAL ;
    PORT
      LAYER M5 ;
        RECT 107.232 0.000 107.256 0.192 ;
    END
  END wrom_q[116]
  PIN wrom_q[117]
    DIRECTION INPUT ;
    USE SIGNAL ;
    PORT
      LAYER M3 ;
        RECT 107.565 0.000 107.589 0.192 ;
    END
  END wrom_q[117]
  PIN wrom_q[118]
    DIRECTION INPUT ;
    USE SIGNAL ;
    PORT
      LAYER M5 ;
        RECT 107.856 0.000 107.880 0.192 ;
    END
  END wrom_q[118]
  PIN wrom_q[119]
    DIRECTION INPUT ;
    USE SIGNAL ;
    PORT
      LAYER M3 ;
        RECT 108.177 0.000 108.201 0.192 ;
    END
  END wrom_q[119]
  PIN wrom_q[120]
    DIRECTION INPUT ;
    USE SIGNAL ;
    PORT
      LAYER M5 ;
        RECT 108.480 0.000 108.504 0.192 ;
    END
  END wrom_q[120]
  PIN wrom_q[121]
    DIRECTION INPUT ;
    USE SIGNAL ;
    PORT
      LAYER M3 ;
        RECT 108.825 0.000 108.849 0.192 ;
    END
  END wrom_q[121]
  PIN wrom_q[122]
    DIRECTION INPUT ;
    USE SIGNAL ;
    PORT
      LAYER M5 ;
        RECT 109.104 0.000 109.128 0.192 ;
    END
  END wrom_q[122]
  PIN wrom_q[123]
    DIRECTION INPUT ;
    USE SIGNAL ;
    PORT
      LAYER M3 ;
        RECT 109.437 0.000 109.461 0.192 ;
    END
  END wrom_q[123]
  PIN wrom_q[124]
    DIRECTION INPUT ;
    USE SIGNAL ;
    PORT
      LAYER M5 ;
        RECT 109.728 0.000 109.752 0.192 ;
    END
  END wrom_q[124]
  PIN wrom_q[125]
    DIRECTION INPUT ;
    USE SIGNAL ;
    PORT
      LAYER M3 ;
        RECT 110.049 0.000 110.073 0.192 ;
    END
  END wrom_q[125]
  PIN wrom_q[126]
    DIRECTION INPUT ;
    USE SIGNAL ;
    PORT
      LAYER M5 ;
        RECT 110.352 0.000 110.376 0.192 ;
    END
  END wrom_q[126]
  PIN wrom_q[127]
    DIRECTION INPUT ;
    USE SIGNAL ;
    PORT
      LAYER M3 ;
        RECT 110.697 0.000 110.721 0.192 ;
    END
  END wrom_q[127]
  PIN wrom_q[128]
    DIRECTION INPUT ;
    USE SIGNAL ;
    PORT
      LAYER M5 ;
        RECT 110.976 0.000 111.000 0.192 ;
    END
  END wrom_q[128]
  PIN wrom_q[129]
    DIRECTION INPUT ;
    USE SIGNAL ;
    PORT
      LAYER M3 ;
        RECT 111.309 0.000 111.333 0.192 ;
    END
  END wrom_q[129]
  PIN wrom_q[130]
    DIRECTION INPUT ;
    USE SIGNAL ;
    PORT
      LAYER M5 ;
        RECT 111.600 0.000 111.624 0.192 ;
    END
  END wrom_q[130]
  PIN wrom_q[131]
    DIRECTION INPUT ;
    USE SIGNAL ;
    PORT
      LAYER M3 ;
        RECT 111.921 0.000 111.945 0.192 ;
    END
  END wrom_q[131]
  PIN wrom_q[132]
    DIRECTION INPUT ;
    USE SIGNAL ;
    PORT
      LAYER M5 ;
        RECT 112.224 0.000 112.248 0.192 ;
    END
  END wrom_q[132]
  PIN wrom_q[133]
    DIRECTION INPUT ;
    USE SIGNAL ;
    PORT
      LAYER M3 ;
        RECT 112.533 0.000 112.557 0.192 ;
    END
  END wrom_q[133]
  PIN wrom_q[134]
    DIRECTION INPUT ;
    USE SIGNAL ;
    PORT
      LAYER M5 ;
        RECT 112.848 0.000 112.872 0.192 ;
    END
  END wrom_q[134]
  PIN wrom_q[135]
    DIRECTION INPUT ;
    USE SIGNAL ;
    PORT
      LAYER M3 ;
        RECT 113.181 0.000 113.205 0.192 ;
    END
  END wrom_q[135]
  PIN wrom_q[136]
    DIRECTION INPUT ;
    USE SIGNAL ;
    PORT
      LAYER M5 ;
        RECT 113.472 0.000 113.496 0.192 ;
    END
  END wrom_q[136]
  PIN wrom_q[137]
    DIRECTION INPUT ;
    USE SIGNAL ;
    PORT
      LAYER M3 ;
        RECT 113.793 0.000 113.817 0.192 ;
    END
  END wrom_q[137]
  PIN wrom_q[138]
    DIRECTION INPUT ;
    USE SIGNAL ;
    PORT
      LAYER M5 ;
        RECT 114.096 0.000 114.120 0.192 ;
    END
  END wrom_q[138]
  PIN wrom_q[139]
    DIRECTION INPUT ;
    USE SIGNAL ;
    PORT
      LAYER M3 ;
        RECT 114.405 0.000 114.429 0.192 ;
    END
  END wrom_q[139]
  PIN wrom_q[140]
    DIRECTION INPUT ;
    USE SIGNAL ;
    PORT
      LAYER M5 ;
        RECT 114.720 0.000 114.744 0.192 ;
    END
  END wrom_q[140]
  PIN wrom_q[141]
    DIRECTION INPUT ;
    USE SIGNAL ;
    PORT
      LAYER M3 ;
        RECT 115.053 0.000 115.077 0.192 ;
    END
  END wrom_q[141]
  PIN wrom_q[142]
    DIRECTION INPUT ;
    USE SIGNAL ;
    PORT
      LAYER M5 ;
        RECT 115.344 0.000 115.368 0.192 ;
    END
  END wrom_q[142]
  PIN wrom_q[143]
    DIRECTION INPUT ;
    USE SIGNAL ;
    PORT
      LAYER M3 ;
        RECT 115.665 0.000 115.689 0.192 ;
    END
  END wrom_q[143]
  PIN wrom_q[144]
    DIRECTION INPUT ;
    USE SIGNAL ;
    PORT
      LAYER M5 ;
        RECT 115.968 0.000 115.992 0.192 ;
    END
  END wrom_q[144]
  PIN wrom_q[145]
    DIRECTION INPUT ;
    USE SIGNAL ;
    PORT
      LAYER M3 ;
        RECT 116.277 0.000 116.301 0.192 ;
    END
  END wrom_q[145]
  PIN wrom_q[146]
    DIRECTION INPUT ;
    USE SIGNAL ;
    PORT
      LAYER M5 ;
        RECT 116.592 0.000 116.616 0.192 ;
    END
  END wrom_q[146]
  PIN wrom_q[147]
    DIRECTION INPUT ;
    USE SIGNAL ;
    PORT
      LAYER M3 ;
        RECT 116.925 0.000 116.949 0.192 ;
    END
  END wrom_q[147]
  PIN wrom_q[148]
    DIRECTION INPUT ;
    USE SIGNAL ;
    PORT
      LAYER M5 ;
        RECT 117.216 0.000 117.240 0.192 ;
    END
  END wrom_q[148]
  PIN wrom_q[149]
    DIRECTION INPUT ;
    USE SIGNAL ;
    PORT
      LAYER M3 ;
        RECT 117.537 0.000 117.561 0.192 ;
    END
  END wrom_q[149]
  PIN wrom_q[150]
    DIRECTION INPUT ;
    USE SIGNAL ;
    PORT
      LAYER M5 ;
        RECT 117.840 0.000 117.864 0.192 ;
    END
  END wrom_q[150]
  PIN wrom_q[151]
    DIRECTION INPUT ;
    USE SIGNAL ;
    PORT
      LAYER M3 ;
        RECT 118.149 0.000 118.173 0.192 ;
    END
  END wrom_q[151]
  PIN wrom_q[152]
    DIRECTION INPUT ;
    USE SIGNAL ;
    PORT
      LAYER M5 ;
        RECT 118.464 0.000 118.488 0.192 ;
    END
  END wrom_q[152]
  PIN wrom_q[153]
    DIRECTION INPUT ;
    USE SIGNAL ;
    PORT
      LAYER M3 ;
        RECT 118.761 0.000 118.785 0.192 ;
    END
  END wrom_q[153]
  PIN wrom_q[154]
    DIRECTION INPUT ;
    USE SIGNAL ;
    PORT
      LAYER M5 ;
        RECT 119.088 0.000 119.112 0.192 ;
    END
  END wrom_q[154]
  PIN wrom_q[155]
    DIRECTION INPUT ;
    USE SIGNAL ;
    PORT
      LAYER M3 ;
        RECT 119.409 0.000 119.433 0.192 ;
    END
  END wrom_q[155]
  PIN wrom_q[156]
    DIRECTION INPUT ;
    USE SIGNAL ;
    PORT
      LAYER M5 ;
        RECT 119.712 0.000 119.736 0.192 ;
    END
  END wrom_q[156]
  PIN wrom_q[157]
    DIRECTION INPUT ;
    USE SIGNAL ;
    PORT
      LAYER M3 ;
        RECT 120.021 0.000 120.045 0.192 ;
    END
  END wrom_q[157]
  PIN wrom_q[158]
    DIRECTION INPUT ;
    USE SIGNAL ;
    PORT
      LAYER M5 ;
        RECT 120.336 0.000 120.360 0.192 ;
    END
  END wrom_q[158]
  PIN wrom_q[159]
    DIRECTION INPUT ;
    USE SIGNAL ;
    PORT
      LAYER M3 ;
        RECT 120.633 0.000 120.657 0.192 ;
    END
  END wrom_q[159]
  PIN wrom_q[160]
    DIRECTION INPUT ;
    USE SIGNAL ;
    PORT
      LAYER M5 ;
        RECT 120.960 0.000 120.984 0.192 ;
    END
  END wrom_q[160]
  PIN wrom_q[161]
    DIRECTION INPUT ;
    USE SIGNAL ;
    PORT
      LAYER M3 ;
        RECT 121.281 0.000 121.305 0.192 ;
    END
  END wrom_q[161]
  PIN wrom_q[162]
    DIRECTION INPUT ;
    USE SIGNAL ;
    PORT
      LAYER M5 ;
        RECT 121.584 0.000 121.608 0.192 ;
    END
  END wrom_q[162]
  PIN wrom_q[163]
    DIRECTION INPUT ;
    USE SIGNAL ;
    PORT
      LAYER M3 ;
        RECT 121.893 0.000 121.917 0.192 ;
    END
  END wrom_q[163]
  PIN wrom_q[164]
    DIRECTION INPUT ;
    USE SIGNAL ;
    PORT
      LAYER M5 ;
        RECT 122.208 0.000 122.232 0.192 ;
    END
  END wrom_q[164]
  PIN wrom_q[165]
    DIRECTION INPUT ;
    USE SIGNAL ;
    PORT
      LAYER M3 ;
        RECT 122.505 0.000 122.529 0.192 ;
    END
  END wrom_q[165]
  PIN wrom_q[166]
    DIRECTION INPUT ;
    USE SIGNAL ;
    PORT
      LAYER M5 ;
        RECT 122.832 0.000 122.856 0.192 ;
    END
  END wrom_q[166]
  PIN wrom_q[167]
    DIRECTION INPUT ;
    USE SIGNAL ;
    PORT
      LAYER M3 ;
        RECT 123.153 0.000 123.177 0.192 ;
    END
  END wrom_q[167]
  PIN wrom_q[168]
    DIRECTION INPUT ;
    USE SIGNAL ;
    PORT
      LAYER M5 ;
        RECT 123.456 0.000 123.480 0.192 ;
    END
  END wrom_q[168]
  PIN wrom_q[169]
    DIRECTION INPUT ;
    USE SIGNAL ;
    PORT
      LAYER M3 ;
        RECT 123.765 0.000 123.789 0.192 ;
    END
  END wrom_q[169]
  PIN wrom_q[170]
    DIRECTION INPUT ;
    USE SIGNAL ;
    PORT
      LAYER M5 ;
        RECT 124.080 0.000 124.104 0.192 ;
    END
  END wrom_q[170]
  PIN wrom_q[171]
    DIRECTION INPUT ;
    USE SIGNAL ;
    PORT
      LAYER M3 ;
        RECT 124.377 0.000 124.401 0.192 ;
    END
  END wrom_q[171]
  PIN wrom_q[172]
    DIRECTION INPUT ;
    USE SIGNAL ;
    PORT
      LAYER M5 ;
        RECT 124.704 0.000 124.728 0.192 ;
    END
  END wrom_q[172]
  PIN wrom_q[173]
    DIRECTION INPUT ;
    USE SIGNAL ;
    PORT
      LAYER M3 ;
        RECT 124.989 0.000 125.013 0.192 ;
    END
  END wrom_q[173]
  PIN wrom_q[174]
    DIRECTION INPUT ;
    USE SIGNAL ;
    PORT
      LAYER M5 ;
        RECT 125.328 0.000 125.352 0.192 ;
    END
  END wrom_q[174]
  PIN wrom_q[175]
    DIRECTION INPUT ;
    USE SIGNAL ;
    PORT
      LAYER M3 ;
        RECT 125.637 0.000 125.661 0.192 ;
    END
  END wrom_q[175]
  PIN wrom_q[176]
    DIRECTION INPUT ;
    USE SIGNAL ;
    PORT
      LAYER M5 ;
        RECT 125.952 0.000 125.976 0.192 ;
    END
  END wrom_q[176]
  PIN wrom_q[177]
    DIRECTION INPUT ;
    USE SIGNAL ;
    PORT
      LAYER M3 ;
        RECT 126.249 0.000 126.273 0.192 ;
    END
  END wrom_q[177]
  PIN wrom_q[178]
    DIRECTION INPUT ;
    USE SIGNAL ;
    PORT
      LAYER M5 ;
        RECT 126.576 0.000 126.600 0.192 ;
    END
  END wrom_q[178]
  PIN wrom_q[179]
    DIRECTION INPUT ;
    USE SIGNAL ;
    PORT
      LAYER M3 ;
        RECT 126.861 0.000 126.885 0.192 ;
    END
  END wrom_q[179]
  PIN wrom_q[180]
    DIRECTION INPUT ;
    USE SIGNAL ;
    PORT
      LAYER M5 ;
        RECT 127.200 0.000 127.224 0.192 ;
    END
  END wrom_q[180]
  PIN wrom_q[181]
    DIRECTION INPUT ;
    USE SIGNAL ;
    PORT
      LAYER M3 ;
        RECT 127.509 0.000 127.533 0.192 ;
    END
  END wrom_q[181]
  PIN wrom_q[182]
    DIRECTION INPUT ;
    USE SIGNAL ;
    PORT
      LAYER M5 ;
        RECT 127.824 0.000 127.848 0.192 ;
    END
  END wrom_q[182]
  PIN wrom_q[183]
    DIRECTION INPUT ;
    USE SIGNAL ;
    PORT
      LAYER M3 ;
        RECT 128.121 0.000 128.145 0.192 ;
    END
  END wrom_q[183]
  PIN wrom_q[184]
    DIRECTION INPUT ;
    USE SIGNAL ;
    PORT
      LAYER M5 ;
        RECT 128.448 0.000 128.472 0.192 ;
    END
  END wrom_q[184]
  PIN wrom_q[185]
    DIRECTION INPUT ;
    USE SIGNAL ;
    PORT
      LAYER M3 ;
        RECT 128.733 0.000 128.757 0.192 ;
    END
  END wrom_q[185]
  PIN wrom_q[186]
    DIRECTION INPUT ;
    USE SIGNAL ;
    PORT
      LAYER M5 ;
        RECT 129.072 0.000 129.096 0.192 ;
    END
  END wrom_q[186]
  PIN wrom_q[187]
    DIRECTION INPUT ;
    USE SIGNAL ;
    PORT
      LAYER M3 ;
        RECT 129.381 0.000 129.405 0.192 ;
    END
  END wrom_q[187]
  PIN wrom_q[188]
    DIRECTION INPUT ;
    USE SIGNAL ;
    PORT
      LAYER M5 ;
        RECT 129.696 0.000 129.720 0.192 ;
    END
  END wrom_q[188]
  PIN wrom_q[189]
    DIRECTION INPUT ;
    USE SIGNAL ;
    PORT
      LAYER M3 ;
        RECT 129.993 0.000 130.017 0.192 ;
    END
  END wrom_q[189]
  PIN wrom_q[190]
    DIRECTION INPUT ;
    USE SIGNAL ;
    PORT
      LAYER M5 ;
        RECT 130.320 0.000 130.344 0.192 ;
    END
  END wrom_q[190]
  PIN wrom_q[191]
    DIRECTION INPUT ;
    USE SIGNAL ;
    PORT
      LAYER M3 ;
        RECT 130.605 0.000 130.629 0.192 ;
    END
  END wrom_q[191]
  PIN wrom_q[192]
    DIRECTION INPUT ;
    USE SIGNAL ;
    PORT
      LAYER M5 ;
        RECT 130.944 0.000 130.968 0.192 ;
    END
  END wrom_q[192]
  PIN wrom_q[193]
    DIRECTION INPUT ;
    USE SIGNAL ;
    PORT
      LAYER M3 ;
        RECT 131.217 0.000 131.241 0.192 ;
    END
  END wrom_q[193]
  PIN wrom_q[194]
    DIRECTION INPUT ;
    USE SIGNAL ;
    PORT
      LAYER M5 ;
        RECT 131.568 0.000 131.592 0.192 ;
    END
  END wrom_q[194]
  PIN wrom_q[195]
    DIRECTION INPUT ;
    USE SIGNAL ;
    PORT
      LAYER M3 ;
        RECT 131.865 0.000 131.889 0.192 ;
    END
  END wrom_q[195]
  PIN wrom_q[196]
    DIRECTION INPUT ;
    USE SIGNAL ;
    PORT
      LAYER M5 ;
        RECT 132.144 0.000 132.168 0.192 ;
    END
  END wrom_q[196]
  PIN wrom_q[197]
    DIRECTION INPUT ;
    USE SIGNAL ;
    PORT
      LAYER M3 ;
        RECT 132.477 0.000 132.501 0.192 ;
    END
  END wrom_q[197]
  PIN wrom_q[198]
    DIRECTION INPUT ;
    USE SIGNAL ;
    PORT
      LAYER M5 ;
        RECT 132.768 0.000 132.792 0.192 ;
    END
  END wrom_q[198]
  PIN wrom_q[199]
    DIRECTION INPUT ;
    USE SIGNAL ;
    PORT
      LAYER M3 ;
        RECT 133.089 0.000 133.113 0.192 ;
    END
  END wrom_q[199]
  PIN wrom_q[200]
    DIRECTION INPUT ;
    USE SIGNAL ;
    PORT
      LAYER M5 ;
        RECT 133.392 0.000 133.416 0.192 ;
    END
  END wrom_q[200]
  PIN wrom_q[201]
    DIRECTION INPUT ;
    USE SIGNAL ;
    PORT
      LAYER M3 ;
        RECT 133.737 0.000 133.761 0.192 ;
    END
  END wrom_q[201]
  PIN wrom_q[202]
    DIRECTION INPUT ;
    USE SIGNAL ;
    PORT
      LAYER M5 ;
        RECT 134.016 0.000 134.040 0.192 ;
    END
  END wrom_q[202]
  PIN wrom_q[203]
    DIRECTION INPUT ;
    USE SIGNAL ;
    PORT
      LAYER M3 ;
        RECT 134.349 0.000 134.373 0.192 ;
    END
  END wrom_q[203]
  PIN wrom_q[204]
    DIRECTION INPUT ;
    USE SIGNAL ;
    PORT
      LAYER M5 ;
        RECT 134.640 0.000 134.664 0.192 ;
    END
  END wrom_q[204]
  PIN wrom_q[205]
    DIRECTION INPUT ;
    USE SIGNAL ;
    PORT
      LAYER M3 ;
        RECT 134.961 0.000 134.985 0.192 ;
    END
  END wrom_q[205]
  PIN wrom_q[206]
    DIRECTION INPUT ;
    USE SIGNAL ;
    PORT
      LAYER M5 ;
        RECT 135.264 0.000 135.288 0.192 ;
    END
  END wrom_q[206]
  PIN wrom_q[207]
    DIRECTION INPUT ;
    USE SIGNAL ;
    PORT
      LAYER M3 ;
        RECT 135.609 0.000 135.633 0.192 ;
    END
  END wrom_q[207]
  PIN wrom_q[208]
    DIRECTION INPUT ;
    USE SIGNAL ;
    PORT
      LAYER M5 ;
        RECT 135.888 0.000 135.912 0.192 ;
    END
  END wrom_q[208]
  PIN wrom_q[209]
    DIRECTION INPUT ;
    USE SIGNAL ;
    PORT
      LAYER M3 ;
        RECT 136.221 0.000 136.245 0.192 ;
    END
  END wrom_q[209]
  PIN wrom_q[210]
    DIRECTION INPUT ;
    USE SIGNAL ;
    PORT
      LAYER M5 ;
        RECT 136.512 0.000 136.536 0.192 ;
    END
  END wrom_q[210]
  PIN wrom_q[211]
    DIRECTION INPUT ;
    USE SIGNAL ;
    PORT
      LAYER M3 ;
        RECT 136.833 0.000 136.857 0.192 ;
    END
  END wrom_q[211]
  PIN wrom_q[212]
    DIRECTION INPUT ;
    USE SIGNAL ;
    PORT
      LAYER M5 ;
        RECT 137.136 0.000 137.160 0.192 ;
    END
  END wrom_q[212]
  PIN wrom_q[213]
    DIRECTION INPUT ;
    USE SIGNAL ;
    PORT
      LAYER M3 ;
        RECT 137.445 0.000 137.469 0.192 ;
    END
  END wrom_q[213]
  PIN wrom_q[214]
    DIRECTION INPUT ;
    USE SIGNAL ;
    PORT
      LAYER M5 ;
        RECT 137.760 0.000 137.784 0.192 ;
    END
  END wrom_q[214]
  PIN wrom_q[215]
    DIRECTION INPUT ;
    USE SIGNAL ;
    PORT
      LAYER M3 ;
        RECT 138.093 0.000 138.117 0.192 ;
    END
  END wrom_q[215]
  PIN wrom_q[216]
    DIRECTION INPUT ;
    USE SIGNAL ;
    PORT
      LAYER M5 ;
        RECT 138.384 0.000 138.408 0.192 ;
    END
  END wrom_q[216]
  PIN wrom_q[217]
    DIRECTION INPUT ;
    USE SIGNAL ;
    PORT
      LAYER M3 ;
        RECT 138.705 0.000 138.729 0.192 ;
    END
  END wrom_q[217]
  PIN wrom_q[218]
    DIRECTION INPUT ;
    USE SIGNAL ;
    PORT
      LAYER M5 ;
        RECT 139.008 0.000 139.032 0.192 ;
    END
  END wrom_q[218]
  PIN wrom_q[219]
    DIRECTION INPUT ;
    USE SIGNAL ;
    PORT
      LAYER M3 ;
        RECT 139.317 0.000 139.341 0.192 ;
    END
  END wrom_q[219]
  PIN wrom_q[220]
    DIRECTION INPUT ;
    USE SIGNAL ;
    PORT
      LAYER M5 ;
        RECT 139.632 0.000 139.656 0.192 ;
    END
  END wrom_q[220]
  PIN wrom_q[221]
    DIRECTION INPUT ;
    USE SIGNAL ;
    PORT
      LAYER M3 ;
        RECT 139.965 0.000 139.989 0.192 ;
    END
  END wrom_q[221]
  PIN wrom_q[222]
    DIRECTION INPUT ;
    USE SIGNAL ;
    PORT
      LAYER M5 ;
        RECT 140.256 0.000 140.280 0.192 ;
    END
  END wrom_q[222]
  PIN wrom_q[223]
    DIRECTION INPUT ;
    USE SIGNAL ;
    PORT
      LAYER M3 ;
        RECT 140.577 0.000 140.601 0.192 ;
    END
  END wrom_q[223]
  PIN wrom_q[224]
    DIRECTION INPUT ;
    USE SIGNAL ;
    PORT
      LAYER M5 ;
        RECT 140.880 0.000 140.904 0.192 ;
    END
  END wrom_q[224]
  PIN wrom_q[225]
    DIRECTION INPUT ;
    USE SIGNAL ;
    PORT
      LAYER M3 ;
        RECT 141.189 0.000 141.213 0.192 ;
    END
  END wrom_q[225]
  PIN wrom_q[226]
    DIRECTION INPUT ;
    USE SIGNAL ;
    PORT
      LAYER M5 ;
        RECT 141.504 0.000 141.528 0.192 ;
    END
  END wrom_q[226]
  PIN wrom_q[227]
    DIRECTION INPUT ;
    USE SIGNAL ;
    PORT
      LAYER M3 ;
        RECT 141.837 0.000 141.861 0.192 ;
    END
  END wrom_q[227]
  PIN wrom_q[228]
    DIRECTION INPUT ;
    USE SIGNAL ;
    PORT
      LAYER M5 ;
        RECT 142.128 0.000 142.152 0.192 ;
    END
  END wrom_q[228]
  PIN wrom_q[229]
    DIRECTION INPUT ;
    USE SIGNAL ;
    PORT
      LAYER M3 ;
        RECT 142.449 0.000 142.473 0.192 ;
    END
  END wrom_q[229]
  PIN wrom_q[230]
    DIRECTION INPUT ;
    USE SIGNAL ;
    PORT
      LAYER M5 ;
        RECT 142.752 0.000 142.776 0.192 ;
    END
  END wrom_q[230]
  PIN wrom_q[231]
    DIRECTION INPUT ;
    USE SIGNAL ;
    PORT
      LAYER M3 ;
        RECT 143.061 0.000 143.085 0.192 ;
    END
  END wrom_q[231]
  PIN wrom_q[232]
    DIRECTION INPUT ;
    USE SIGNAL ;
    PORT
      LAYER M5 ;
        RECT 143.376 0.000 143.400 0.192 ;
    END
  END wrom_q[232]
  PIN wrom_q[233]
    DIRECTION INPUT ;
    USE SIGNAL ;
    PORT
      LAYER M3 ;
        RECT 143.673 0.000 143.697 0.192 ;
    END
  END wrom_q[233]
  PIN wrom_q[234]
    DIRECTION INPUT ;
    USE SIGNAL ;
    PORT
      LAYER M5 ;
        RECT 144.000 0.000 144.024 0.192 ;
    END
  END wrom_q[234]
  PIN wrom_q[235]
    DIRECTION INPUT ;
    USE SIGNAL ;
    PORT
      LAYER M3 ;
        RECT 144.321 0.000 144.345 0.192 ;
    END
  END wrom_q[235]
  PIN wrom_q[236]
    DIRECTION INPUT ;
    USE SIGNAL ;
    PORT
      LAYER M5 ;
        RECT 144.624 0.000 144.648 0.192 ;
    END
  END wrom_q[236]
  PIN wrom_q[237]
    DIRECTION INPUT ;
    USE SIGNAL ;
    PORT
      LAYER M3 ;
        RECT 144.933 0.000 144.957 0.192 ;
    END
  END wrom_q[237]
  PIN wrom_q[238]
    DIRECTION INPUT ;
    USE SIGNAL ;
    PORT
      LAYER M5 ;
        RECT 145.248 0.000 145.272 0.192 ;
    END
  END wrom_q[238]
  PIN wrom_q[239]
    DIRECTION INPUT ;
    USE SIGNAL ;
    PORT
      LAYER M3 ;
        RECT 145.545 0.000 145.569 0.192 ;
    END
  END wrom_q[239]
  PIN wrom_q[240]
    DIRECTION INPUT ;
    USE SIGNAL ;
    PORT
      LAYER M5 ;
        RECT 145.872 0.000 145.896 0.192 ;
    END
  END wrom_q[240]
  PIN wrom_q[241]
    DIRECTION INPUT ;
    USE SIGNAL ;
    PORT
      LAYER M3 ;
        RECT 146.193 0.000 146.217 0.192 ;
    END
  END wrom_q[241]
  PIN wrom_q[242]
    DIRECTION INPUT ;
    USE SIGNAL ;
    PORT
      LAYER M5 ;
        RECT 146.496 0.000 146.520 0.192 ;
    END
  END wrom_q[242]
  PIN wrom_q[243]
    DIRECTION INPUT ;
    USE SIGNAL ;
    PORT
      LAYER M3 ;
        RECT 146.805 0.000 146.829 0.192 ;
    END
  END wrom_q[243]
  PIN wrom_q[244]
    DIRECTION INPUT ;
    USE SIGNAL ;
    PORT
      LAYER M5 ;
        RECT 147.120 0.000 147.144 0.192 ;
    END
  END wrom_q[244]
  PIN wrom_q[245]
    DIRECTION INPUT ;
    USE SIGNAL ;
    PORT
      LAYER M3 ;
        RECT 147.417 0.000 147.441 0.192 ;
    END
  END wrom_q[245]
  PIN wrom_q[246]
    DIRECTION INPUT ;
    USE SIGNAL ;
    PORT
      LAYER M5 ;
        RECT 147.744 0.000 147.768 0.192 ;
    END
  END wrom_q[246]
  PIN wrom_q[247]
    DIRECTION INPUT ;
    USE SIGNAL ;
    PORT
      LAYER M3 ;
        RECT 148.065 0.000 148.089 0.192 ;
    END
  END wrom_q[247]
  PIN wrom_q[248]
    DIRECTION INPUT ;
    USE SIGNAL ;
    PORT
      LAYER M5 ;
        RECT 148.368 0.000 148.392 0.192 ;
    END
  END wrom_q[248]
  PIN wrom_q[249]
    DIRECTION INPUT ;
    USE SIGNAL ;
    PORT
      LAYER M3 ;
        RECT 148.677 0.000 148.701 0.192 ;
    END
  END wrom_q[249]
  PIN wrom_q[250]
    DIRECTION INPUT ;
    USE SIGNAL ;
    PORT
      LAYER M5 ;
        RECT 148.992 0.000 149.016 0.192 ;
    END
  END wrom_q[250]
  PIN wrom_q[251]
    DIRECTION INPUT ;
    USE SIGNAL ;
    PORT
      LAYER M3 ;
        RECT 149.289 0.000 149.313 0.192 ;
    END
  END wrom_q[251]
  PIN wrom_q[252]
    DIRECTION INPUT ;
    USE SIGNAL ;
    PORT
      LAYER M5 ;
        RECT 149.616 0.000 149.640 0.192 ;
    END
  END wrom_q[252]
  PIN wrom_q[253]
    DIRECTION INPUT ;
    USE SIGNAL ;
    PORT
      LAYER M3 ;
        RECT 149.901 0.000 149.925 0.192 ;
    END
  END wrom_q[253]
  PIN wrom_q[254]
    DIRECTION INPUT ;
    USE SIGNAL ;
    PORT
      LAYER M5 ;
        RECT 150.240 0.000 150.264 0.192 ;
    END
  END wrom_q[254]
  PIN wrom_q[255]
    DIRECTION INPUT ;
    USE SIGNAL ;
    PORT
      LAYER M3 ;
        RECT 150.549 0.000 150.573 0.192 ;
    END
  END wrom_q[255]
  PIN crom_q[0]
    DIRECTION INPUT ;
    USE SIGNAL ;
    PORT
      LAYER M5 ;
        RECT 150.864 0.000 150.888 0.192 ;
    END
  END crom_q[0]
  PIN crom_q[1]
    DIRECTION INPUT ;
    USE SIGNAL ;
    PORT
      LAYER M3 ;
        RECT 151.161 0.000 151.185 0.192 ;
    END
  END crom_q[1]
  PIN crom_q[2]
    DIRECTION INPUT ;
    USE SIGNAL ;
    PORT
      LAYER M5 ;
        RECT 151.488 0.000 151.512 0.192 ;
    END
  END crom_q[2]
  PIN crom_q[3]
    DIRECTION INPUT ;
    USE SIGNAL ;
    PORT
      LAYER M3 ;
        RECT 151.773 0.000 151.797 0.192 ;
    END
  END crom_q[3]
  PIN crom_q[4]
    DIRECTION INPUT ;
    USE SIGNAL ;
    PORT
      LAYER M5 ;
        RECT 152.112 0.000 152.136 0.192 ;
    END
  END crom_q[4]
  PIN crom_q[5]
    DIRECTION INPUT ;
    USE SIGNAL ;
    PORT
      LAYER M3 ;
        RECT 152.421 0.000 152.445 0.192 ;
    END
  END crom_q[5]
  PIN crom_q[6]
    DIRECTION INPUT ;
    USE SIGNAL ;
    PORT
      LAYER M5 ;
        RECT 152.736 0.000 152.760 0.192 ;
    END
  END crom_q[6]
  PIN crom_q[7]
    DIRECTION INPUT ;
    USE SIGNAL ;
    PORT
      LAYER M3 ;
        RECT 153.033 0.000 153.057 0.192 ;
    END
  END crom_q[7]
  PIN crom_q[8]
    DIRECTION INPUT ;
    USE SIGNAL ;
    PORT
      LAYER M5 ;
        RECT 153.360 0.000 153.384 0.192 ;
    END
  END crom_q[8]
  PIN crom_q[9]
    DIRECTION INPUT ;
    USE SIGNAL ;
    PORT
      LAYER M3 ;
        RECT 153.645 0.000 153.669 0.192 ;
    END
  END crom_q[9]
  PIN crom_q[10]
    DIRECTION INPUT ;
    USE SIGNAL ;
    PORT
      LAYER M5 ;
        RECT 153.984 0.000 154.008 0.192 ;
    END
  END crom_q[10]
  PIN crom_q[11]
    DIRECTION INPUT ;
    USE SIGNAL ;
    PORT
      LAYER M3 ;
        RECT 154.293 0.000 154.317 0.192 ;
    END
  END crom_q[11]
  PIN crom_q[12]
    DIRECTION INPUT ;
    USE SIGNAL ;
    PORT
      LAYER M5 ;
        RECT 154.608 0.000 154.632 0.192 ;
    END
  END crom_q[12]
  PIN crom_q[13]
    DIRECTION INPUT ;
    USE SIGNAL ;
    PORT
      LAYER M3 ;
        RECT 154.905 0.000 154.929 0.192 ;
    END
  END crom_q[13]
  PIN crom_q[14]
    DIRECTION INPUT ;
    USE SIGNAL ;
    PORT
      LAYER M5 ;
        RECT 155.232 0.000 155.256 0.192 ;
    END
  END crom_q[14]
  PIN crom_q[15]
    DIRECTION INPUT ;
    USE SIGNAL ;
    PORT
      LAYER M3 ;
        RECT 155.517 0.000 155.541 0.192 ;
    END
  END crom_q[15]
  PIN crom_q[16]
    DIRECTION INPUT ;
    USE SIGNAL ;
    PORT
      LAYER M5 ;
        RECT 155.856 0.000 155.880 0.192 ;
    END
  END crom_q[16]
  PIN crom_q[17]
    DIRECTION INPUT ;
    USE SIGNAL ;
    PORT
      LAYER M3 ;
        RECT 156.129 0.000 156.153 0.192 ;
    END
  END crom_q[17]
  PIN crom_q[18]
    DIRECTION INPUT ;
    USE SIGNAL ;
    PORT
      LAYER M5 ;
        RECT 156.480 0.000 156.504 0.192 ;
    END
  END crom_q[18]
  PIN crom_q[19]
    DIRECTION INPUT ;
    USE SIGNAL ;
    PORT
      LAYER M3 ;
        RECT 156.777 0.000 156.801 0.192 ;
    END
  END crom_q[19]
  PIN crom_q[20]
    DIRECTION INPUT ;
    USE SIGNAL ;
    PORT
      LAYER M5 ;
        RECT 157.104 0.000 157.128 0.192 ;
    END
  END crom_q[20]
  PIN crom_q[21]
    DIRECTION INPUT ;
    USE SIGNAL ;
    PORT
      LAYER M3 ;
        RECT 157.389 0.000 157.413 0.192 ;
    END
  END crom_q[21]
  PIN crom_q[22]
    DIRECTION INPUT ;
    USE SIGNAL ;
    PORT
      LAYER M5 ;
        RECT 157.680 0.000 157.704 0.192 ;
    END
  END crom_q[22]
  PIN crom_q[23]
    DIRECTION INPUT ;
    USE SIGNAL ;
    PORT
      LAYER M3 ;
        RECT 158.001 0.000 158.025 0.192 ;
    END
  END crom_q[23]
  PIN crom_q[24]
    DIRECTION INPUT ;
    USE SIGNAL ;
    PORT
      LAYER M5 ;
        RECT 158.304 0.000 158.328 0.192 ;
    END
  END crom_q[24]
  PIN crom_q[25]
    DIRECTION INPUT ;
    USE SIGNAL ;
    PORT
      LAYER M3 ;
        RECT 158.649 0.000 158.673 0.192 ;
    END
  END crom_q[25]
  PIN crom_q[26]
    DIRECTION INPUT ;
    USE SIGNAL ;
    PORT
      LAYER M5 ;
        RECT 158.928 0.000 158.952 0.192 ;
    END
  END crom_q[26]
  PIN crom_q[27]
    DIRECTION INPUT ;
    USE SIGNAL ;
    PORT
      LAYER M3 ;
        RECT 159.261 0.000 159.285 0.192 ;
    END
  END crom_q[27]
  PIN crom_q[28]
    DIRECTION INPUT ;
    USE SIGNAL ;
    PORT
      LAYER M5 ;
        RECT 159.552 0.000 159.576 0.192 ;
    END
  END crom_q[28]
  PIN crom_q[29]
    DIRECTION INPUT ;
    USE SIGNAL ;
    PORT
      LAYER M3 ;
        RECT 159.873 0.000 159.897 0.192 ;
    END
  END crom_q[29]
  PIN crom_q[30]
    DIRECTION INPUT ;
    USE SIGNAL ;
    PORT
      LAYER M5 ;
        RECT 160.176 0.000 160.200 0.192 ;
    END
  END crom_q[30]
  PIN crom_q[31]
    DIRECTION INPUT ;
    USE SIGNAL ;
    PORT
      LAYER M3 ;
        RECT 160.521 0.000 160.545 0.192 ;
    END
  END crom_q[31]
  PIN crom_q[32]
    DIRECTION INPUT ;
    USE SIGNAL ;
    PORT
      LAYER M5 ;
        RECT 160.800 0.000 160.824 0.192 ;
    END
  END crom_q[32]
  PIN crom_q[33]
    DIRECTION INPUT ;
    USE SIGNAL ;
    PORT
      LAYER M3 ;
        RECT 161.133 0.000 161.157 0.192 ;
    END
  END crom_q[33]
  PIN crom_q[34]
    DIRECTION INPUT ;
    USE SIGNAL ;
    PORT
      LAYER M5 ;
        RECT 161.424 0.000 161.448 0.192 ;
    END
  END crom_q[34]
  PIN crom_q[35]
    DIRECTION INPUT ;
    USE SIGNAL ;
    PORT
      LAYER M3 ;
        RECT 161.745 0.000 161.769 0.192 ;
    END
  END crom_q[35]
  PIN crom_q[36]
    DIRECTION INPUT ;
    USE SIGNAL ;
    PORT
      LAYER M5 ;
        RECT 162.048 0.000 162.072 0.192 ;
    END
  END crom_q[36]
  PIN crom_q[37]
    DIRECTION INPUT ;
    USE SIGNAL ;
    PORT
      LAYER M3 ;
        RECT 162.393 0.000 162.417 0.192 ;
    END
  END crom_q[37]
  PIN crom_q[38]
    DIRECTION INPUT ;
    USE SIGNAL ;
    PORT
      LAYER M5 ;
        RECT 162.672 0.000 162.696 0.192 ;
    END
  END crom_q[38]
  PIN crom_q[39]
    DIRECTION INPUT ;
    USE SIGNAL ;
    PORT
      LAYER M3 ;
        RECT 163.005 0.000 163.029 0.192 ;
    END
  END crom_q[39]
  PIN crom_q[40]
    DIRECTION INPUT ;
    USE SIGNAL ;
    PORT
      LAYER M5 ;
        RECT 163.296 0.000 163.320 0.192 ;
    END
  END crom_q[40]
  PIN crom_q[41]
    DIRECTION INPUT ;
    USE SIGNAL ;
    PORT
      LAYER M3 ;
        RECT 163.617 0.000 163.641 0.192 ;
    END
  END crom_q[41]
  PIN crom_q[42]
    DIRECTION INPUT ;
    USE SIGNAL ;
    PORT
      LAYER M5 ;
        RECT 163.920 0.000 163.944 0.192 ;
    END
  END crom_q[42]
  PIN crom_q[43]
    DIRECTION INPUT ;
    USE SIGNAL ;
    PORT
      LAYER M3 ;
        RECT 164.229 0.000 164.253 0.192 ;
    END
  END crom_q[43]
  PIN crom_q[44]
    DIRECTION INPUT ;
    USE SIGNAL ;
    PORT
      LAYER M5 ;
        RECT 164.544 0.000 164.568 0.192 ;
    END
  END crom_q[44]
  PIN crom_q[45]
    DIRECTION INPUT ;
    USE SIGNAL ;
    PORT
      LAYER M3 ;
        RECT 164.877 0.000 164.901 0.192 ;
    END
  END crom_q[45]
  PIN crom_q[46]
    DIRECTION INPUT ;
    USE SIGNAL ;
    PORT
      LAYER M5 ;
        RECT 165.168 0.000 165.192 0.192 ;
    END
  END crom_q[46]
  PIN crom_q[47]
    DIRECTION INPUT ;
    USE SIGNAL ;
    PORT
      LAYER M3 ;
        RECT 165.489 0.000 165.513 0.192 ;
    END
  END crom_q[47]
  PIN crom_q[48]
    DIRECTION INPUT ;
    USE SIGNAL ;
    PORT
      LAYER M5 ;
        RECT 165.792 0.000 165.816 0.192 ;
    END
  END crom_q[48]
  PIN crom_q[49]
    DIRECTION INPUT ;
    USE SIGNAL ;
    PORT
      LAYER M3 ;
        RECT 166.101 0.000 166.125 0.192 ;
    END
  END crom_q[49]
  PIN crom_q[50]
    DIRECTION INPUT ;
    USE SIGNAL ;
    PORT
      LAYER M5 ;
        RECT 166.416 0.000 166.440 0.192 ;
    END
  END crom_q[50]
  PIN crom_q[51]
    DIRECTION INPUT ;
    USE SIGNAL ;
    PORT
      LAYER M3 ;
        RECT 166.749 0.000 166.773 0.192 ;
    END
  END crom_q[51]
  PIN crom_q[52]
    DIRECTION INPUT ;
    USE SIGNAL ;
    PORT
      LAYER M5 ;
        RECT 167.040 0.000 167.064 0.192 ;
    END
  END crom_q[52]
  PIN crom_q[53]
    DIRECTION INPUT ;
    USE SIGNAL ;
    PORT
      LAYER M3 ;
        RECT 167.361 0.000 167.385 0.192 ;
    END
  END crom_q[53]
  PIN crom_q[54]
    DIRECTION INPUT ;
    USE SIGNAL ;
    PORT
      LAYER M5 ;
        RECT 167.664 0.000 167.688 0.192 ;
    END
  END crom_q[54]
  PIN crom_q[55]
    DIRECTION INPUT ;
    USE SIGNAL ;
    PORT
      LAYER M3 ;
        RECT 167.973 0.000 167.997 0.192 ;
    END
  END crom_q[55]
  PIN crom_q[56]
    DIRECTION INPUT ;
    USE SIGNAL ;
    PORT
      LAYER M5 ;
        RECT 168.288 0.000 168.312 0.192 ;
    END
  END crom_q[56]
  PIN crom_q[57]
    DIRECTION INPUT ;
    USE SIGNAL ;
    PORT
      LAYER M3 ;
        RECT 168.621 0.000 168.645 0.192 ;
    END
  END crom_q[57]
  PIN crom_q[58]
    DIRECTION INPUT ;
    USE SIGNAL ;
    PORT
      LAYER M5 ;
        RECT 168.912 0.000 168.936 0.192 ;
    END
  END crom_q[58]
  PIN crom_q[59]
    DIRECTION INPUT ;
    USE SIGNAL ;
    PORT
      LAYER M3 ;
        RECT 169.233 0.000 169.257 0.192 ;
    END
  END crom_q[59]
  PIN crom_q[60]
    DIRECTION INPUT ;
    USE SIGNAL ;
    PORT
      LAYER M5 ;
        RECT 169.536 0.000 169.560 0.192 ;
    END
  END crom_q[60]
  PIN crom_q[61]
    DIRECTION INPUT ;
    USE SIGNAL ;
    PORT
      LAYER M3 ;
        RECT 169.845 0.000 169.869 0.192 ;
    END
  END crom_q[61]
  PIN crom_q[62]
    DIRECTION INPUT ;
    USE SIGNAL ;
    PORT
      LAYER M5 ;
        RECT 170.160 0.000 170.184 0.192 ;
    END
  END crom_q[62]
  PIN crom_q[63]
    DIRECTION INPUT ;
    USE SIGNAL ;
    PORT
      LAYER M3 ;
        RECT 170.457 0.000 170.481 0.192 ;
    END
  END crom_q[63]
  PIN clk
    DIRECTION INPUT ;
    USE CLOCK ;
    PORT
      LAYER M5 ;
        RECT 2.352 129.408 2.376 129.600 ;
    END
  END clk
  PIN rst_n
    DIRECTION INPUT ;
    USE SIGNAL ;
    PORT
      LAYER M3 ;
        RECT 2.805 129.408 2.829 129.600 ;
    END
  END rst_n
  PIN vm_we
    DIRECTION OUTPUT ;
    USE SIGNAL ;
    PORT
      LAYER M5 ;
        RECT 3.264 129.408 3.288 129.600 ;
    END
  END vm_we
  PIN vm_waddr[0]
    DIRECTION OUTPUT ;
    USE SIGNAL ;
    PORT
      LAYER M3 ;
        RECT 3.705 129.408 3.729 129.600 ;
    END
  END vm_waddr[0]
  PIN vm_waddr[1]
    DIRECTION OUTPUT ;
    USE SIGNAL ;
    PORT
      LAYER M5 ;
        RECT 4.176 129.408 4.200 129.600 ;
    END
  END vm_waddr[1]
  PIN vm_waddr[2]
    DIRECTION OUTPUT ;
    USE SIGNAL ;
    PORT
      LAYER M3 ;
        RECT 4.605 129.408 4.629 129.600 ;
    END
  END vm_waddr[2]
  PIN vm_waddr[3]
    DIRECTION OUTPUT ;
    USE SIGNAL ;
    PORT
      LAYER M5 ;
        RECT 5.040 129.408 5.064 129.600 ;
    END
  END vm_waddr[3]
  PIN vm_waddr[4]
    DIRECTION OUTPUT ;
    USE SIGNAL ;
    PORT
      LAYER M3 ;
        RECT 5.505 129.408 5.529 129.600 ;
    END
  END vm_waddr[4]
  PIN vm_waddr[5]
    DIRECTION OUTPUT ;
    USE SIGNAL ;
    PORT
      LAYER M5 ;
        RECT 5.952 129.408 5.976 129.600 ;
    END
  END vm_waddr[5]
  PIN vm_waddr[6]
    DIRECTION OUTPUT ;
    USE SIGNAL ;
    PORT
      LAYER M3 ;
        RECT 6.369 129.408 6.393 129.600 ;
    END
  END vm_waddr[6]
  PIN vm_waddr[7]
    DIRECTION OUTPUT ;
    USE SIGNAL ;
    PORT
      LAYER M5 ;
        RECT 6.816 129.408 6.840 129.600 ;
    END
  END vm_waddr[7]
  PIN vm_waddr[8]
    DIRECTION OUTPUT ;
    USE SIGNAL ;
    PORT
      LAYER M3 ;
        RECT 7.269 129.408 7.293 129.600 ;
    END
  END vm_waddr[8]
  PIN vm_waddr[9]
    DIRECTION OUTPUT ;
    USE SIGNAL ;
    PORT
      LAYER M5 ;
        RECT 7.728 129.408 7.752 129.600 ;
    END
  END vm_waddr[9]
  PIN vm_waddr[10]
    DIRECTION OUTPUT ;
    USE SIGNAL ;
    PORT
      LAYER M3 ;
        RECT 8.169 129.408 8.193 129.600 ;
    END
  END vm_waddr[10]
  PIN vm_waddr[11]
    DIRECTION OUTPUT ;
    USE SIGNAL ;
    PORT
      LAYER M5 ;
        RECT 8.592 129.408 8.616 129.600 ;
    END
  END vm_waddr[11]
  PIN vm_waddr[12]
    DIRECTION OUTPUT ;
    USE SIGNAL ;
    PORT
      LAYER M3 ;
        RECT 9.069 129.408 9.093 129.600 ;
    END
  END vm_waddr[12]
  PIN vm_waddr[13]
    DIRECTION OUTPUT ;
    USE SIGNAL ;
    PORT
      LAYER M5 ;
        RECT 9.504 129.408 9.528 129.600 ;
    END
  END vm_waddr[13]
  PIN vm_waddr[14]
    DIRECTION OUTPUT ;
    USE SIGNAL ;
    PORT
      LAYER M3 ;
        RECT 9.933 129.408 9.957 129.600 ;
    END
  END vm_waddr[14]
  PIN vm_waddr[15]
    DIRECTION OUTPUT ;
    USE SIGNAL ;
    PORT
      LAYER M5 ;
        RECT 10.416 129.408 10.440 129.600 ;
    END
  END vm_waddr[15]
  PIN vm_waddr[16]
    DIRECTION OUTPUT ;
    USE SIGNAL ;
    PORT
      LAYER M3 ;
        RECT 10.833 129.408 10.857 129.600 ;
    END
  END vm_waddr[16]
  PIN vm_waddr[17]
    DIRECTION OUTPUT ;
    USE SIGNAL ;
    PORT
      LAYER M5 ;
        RECT 11.280 129.408 11.304 129.600 ;
    END
  END vm_waddr[17]
  PIN vm_waddr[18]
    DIRECTION OUTPUT ;
    USE SIGNAL ;
    PORT
      LAYER M3 ;
        RECT 11.733 129.408 11.757 129.600 ;
    END
  END vm_waddr[18]
  PIN vm_waddr[19]
    DIRECTION OUTPUT ;
    USE SIGNAL ;
    PORT
      LAYER M5 ;
        RECT 12.192 129.408 12.216 129.600 ;
    END
  END vm_waddr[19]
  PIN vm_waddr[20]
    DIRECTION OUTPUT ;
    USE SIGNAL ;
    PORT
      LAYER M3 ;
        RECT 12.633 129.408 12.657 129.600 ;
    END
  END vm_waddr[20]
  PIN vm_waddr[21]
    DIRECTION OUTPUT ;
    USE SIGNAL ;
    PORT
      LAYER M5 ;
        RECT 13.056 129.408 13.080 129.600 ;
    END
  END vm_waddr[21]
  PIN vm_waddr[22]
    DIRECTION OUTPUT ;
    USE SIGNAL ;
    PORT
      LAYER M3 ;
        RECT 13.497 129.408 13.521 129.600 ;
    END
  END vm_waddr[22]
  PIN vm_waddr[23]
    DIRECTION OUTPUT ;
    USE SIGNAL ;
    PORT
      LAYER M5 ;
        RECT 13.968 129.408 13.992 129.600 ;
    END
  END vm_waddr[23]
  PIN vm_wdata[0]
    DIRECTION OUTPUT ;
    USE SIGNAL ;
    PORT
      LAYER M3 ;
        RECT 14.397 129.408 14.421 129.600 ;
    END
  END vm_wdata[0]
  PIN vm_wdata[1]
    DIRECTION OUTPUT ;
    USE SIGNAL ;
    PORT
      LAYER M5 ;
        RECT 14.832 129.408 14.856 129.600 ;
    END
  END vm_wdata[1]
  PIN vm_wdata[2]
    DIRECTION OUTPUT ;
    USE SIGNAL ;
    PORT
      LAYER M3 ;
        RECT 15.297 129.408 15.321 129.600 ;
    END
  END vm_wdata[2]
  PIN vm_wdata[3]
    DIRECTION OUTPUT ;
    USE SIGNAL ;
    PORT
      LAYER M5 ;
        RECT 15.744 129.408 15.768 129.600 ;
    END
  END vm_wdata[3]
  PIN vm_wdata[4]
    DIRECTION OUTPUT ;
    USE SIGNAL ;
    PORT
      LAYER M3 ;
        RECT 16.197 129.408 16.221 129.600 ;
    END
  END vm_wdata[4]
  PIN vm_wdata[5]
    DIRECTION OUTPUT ;
    USE SIGNAL ;
    PORT
      LAYER M5 ;
        RECT 16.656 129.408 16.680 129.600 ;
    END
  END vm_wdata[5]
  PIN vm_wdata[6]
    DIRECTION OUTPUT ;
    USE SIGNAL ;
    PORT
      LAYER M3 ;
        RECT 17.097 129.408 17.121 129.600 ;
    END
  END vm_wdata[6]
  PIN vm_wdata[7]
    DIRECTION OUTPUT ;
    USE SIGNAL ;
    PORT
      LAYER M5 ;
        RECT 17.520 129.408 17.544 129.600 ;
    END
  END vm_wdata[7]
  PIN vm_wdata[8]
    DIRECTION OUTPUT ;
    USE SIGNAL ;
    PORT
      LAYER M3 ;
        RECT 17.961 129.408 17.985 129.600 ;
    END
  END vm_wdata[8]
  PIN vm_wdata[9]
    DIRECTION OUTPUT ;
    USE SIGNAL ;
    PORT
      LAYER M5 ;
        RECT 18.432 129.408 18.456 129.600 ;
    END
  END vm_wdata[9]
  PIN vm_wdata[10]
    DIRECTION OUTPUT ;
    USE SIGNAL ;
    PORT
      LAYER M3 ;
        RECT 18.861 129.408 18.885 129.600 ;
    END
  END vm_wdata[10]
  PIN vm_wdata[11]
    DIRECTION OUTPUT ;
    USE SIGNAL ;
    PORT
      LAYER M5 ;
        RECT 19.296 129.408 19.320 129.600 ;
    END
  END vm_wdata[11]
  PIN vm_wdata[12]
    DIRECTION OUTPUT ;
    USE SIGNAL ;
    PORT
      LAYER M3 ;
        RECT 19.761 129.408 19.785 129.600 ;
    END
  END vm_wdata[12]
  PIN vm_wdata[13]
    DIRECTION OUTPUT ;
    USE SIGNAL ;
    PORT
      LAYER M5 ;
        RECT 20.208 129.408 20.232 129.600 ;
    END
  END vm_wdata[13]
  PIN vm_wdata[14]
    DIRECTION OUTPUT ;
    USE SIGNAL ;
    PORT
      LAYER M3 ;
        RECT 20.661 129.408 20.685 129.600 ;
    END
  END vm_wdata[14]
  PIN vm_wdata[15]
    DIRECTION OUTPUT ;
    USE SIGNAL ;
    PORT
      LAYER M5 ;
        RECT 21.072 129.408 21.096 129.600 ;
    END
  END vm_wdata[15]
  PIN vm_wdata[16]
    DIRECTION OUTPUT ;
    USE SIGNAL ;
    PORT
      LAYER M3 ;
        RECT 21.525 129.408 21.549 129.600 ;
    END
  END vm_wdata[16]
  PIN vm_wdata[17]
    DIRECTION OUTPUT ;
    USE SIGNAL ;
    PORT
      LAYER M5 ;
        RECT 21.984 129.408 22.008 129.600 ;
    END
  END vm_wdata[17]
  PIN vm_wdata[18]
    DIRECTION OUTPUT ;
    USE SIGNAL ;
    PORT
      LAYER M3 ;
        RECT 22.425 129.408 22.449 129.600 ;
    END
  END vm_wdata[18]
  PIN vm_wdata[19]
    DIRECTION OUTPUT ;
    USE SIGNAL ;
    PORT
      LAYER M5 ;
        RECT 22.896 129.408 22.920 129.600 ;
    END
  END vm_wdata[19]
  PIN vm_wdata[20]
    DIRECTION OUTPUT ;
    USE SIGNAL ;
    PORT
      LAYER M3 ;
        RECT 23.325 129.408 23.349 129.600 ;
    END
  END vm_wdata[20]
  PIN vm_wdata[21]
    DIRECTION OUTPUT ;
    USE SIGNAL ;
    PORT
      LAYER M5 ;
        RECT 23.760 129.408 23.784 129.600 ;
    END
  END vm_wdata[21]
  PIN vm_wdata[22]
    DIRECTION OUTPUT ;
    USE SIGNAL ;
    PORT
      LAYER M3 ;
        RECT 24.225 129.408 24.249 129.600 ;
    END
  END vm_wdata[22]
  PIN vm_wdata[23]
    DIRECTION OUTPUT ;
    USE SIGNAL ;
    PORT
      LAYER M5 ;
        RECT 24.672 129.408 24.696 129.600 ;
    END
  END vm_wdata[23]
  PIN vm_wdata[24]
    DIRECTION OUTPUT ;
    USE SIGNAL ;
    PORT
      LAYER M3 ;
        RECT 25.089 129.408 25.113 129.600 ;
    END
  END vm_wdata[24]
  PIN vm_wdata[25]
    DIRECTION OUTPUT ;
    USE SIGNAL ;
    PORT
      LAYER M5 ;
        RECT 25.536 129.408 25.560 129.600 ;
    END
  END vm_wdata[25]
  PIN vm_wdata[26]
    DIRECTION OUTPUT ;
    USE SIGNAL ;
    PORT
      LAYER M3 ;
        RECT 25.989 129.408 26.013 129.600 ;
    END
  END vm_wdata[26]
  PIN vm_wdata[27]
    DIRECTION OUTPUT ;
    USE SIGNAL ;
    PORT
      LAYER M5 ;
        RECT 26.448 129.408 26.472 129.600 ;
    END
  END vm_wdata[27]
  PIN vm_wdata[28]
    DIRECTION OUTPUT ;
    USE SIGNAL ;
    PORT
      LAYER M3 ;
        RECT 26.889 129.408 26.913 129.600 ;
    END
  END vm_wdata[28]
  PIN vm_wdata[29]
    DIRECTION OUTPUT ;
    USE SIGNAL ;
    PORT
      LAYER M5 ;
        RECT 27.312 129.408 27.336 129.600 ;
    END
  END vm_wdata[29]
  PIN vm_wdata[30]
    DIRECTION OUTPUT ;
    USE SIGNAL ;
    PORT
      LAYER M3 ;
        RECT 27.789 129.408 27.813 129.600 ;
    END
  END vm_wdata[30]
  PIN vm_wdata[31]
    DIRECTION OUTPUT ;
    USE SIGNAL ;
    PORT
      LAYER M5 ;
        RECT 28.224 129.408 28.248 129.600 ;
    END
  END vm_wdata[31]
  PIN kv_we
    DIRECTION OUTPUT ;
    USE SIGNAL ;
    PORT
      LAYER M3 ;
        RECT 28.653 129.408 28.677 129.600 ;
    END
  END kv_we
  PIN kv_waddr[0]
    DIRECTION OUTPUT ;
    USE SIGNAL ;
    PORT
      LAYER M5 ;
        RECT 29.136 129.408 29.160 129.600 ;
    END
  END kv_waddr[0]
  PIN kv_waddr[1]
    DIRECTION OUTPUT ;
    USE SIGNAL ;
    PORT
      LAYER M3 ;
        RECT 29.553 129.408 29.577 129.600 ;
    END
  END kv_waddr[1]
  PIN kv_waddr[2]
    DIRECTION OUTPUT ;
    USE SIGNAL ;
    PORT
      LAYER M5 ;
        RECT 30.000 129.408 30.024 129.600 ;
    END
  END kv_waddr[2]
  PIN kv_waddr[3]
    DIRECTION OUTPUT ;
    USE SIGNAL ;
    PORT
      LAYER M3 ;
        RECT 30.453 129.408 30.477 129.600 ;
    END
  END kv_waddr[3]
  PIN kv_waddr[4]
    DIRECTION OUTPUT ;
    USE SIGNAL ;
    PORT
      LAYER M5 ;
        RECT 30.912 129.408 30.936 129.600 ;
    END
  END kv_waddr[4]
  PIN kv_waddr[5]
    DIRECTION OUTPUT ;
    USE SIGNAL ;
    PORT
      LAYER M3 ;
        RECT 31.353 129.408 31.377 129.600 ;
    END
  END kv_waddr[5]
  PIN kv_waddr[6]
    DIRECTION OUTPUT ;
    USE SIGNAL ;
    PORT
      LAYER M5 ;
        RECT 31.776 129.408 31.800 129.600 ;
    END
  END kv_waddr[6]
  PIN kv_waddr[7]
    DIRECTION OUTPUT ;
    USE SIGNAL ;
    PORT
      LAYER M3 ;
        RECT 32.217 129.408 32.241 129.600 ;
    END
  END kv_waddr[7]
  PIN kv_waddr[8]
    DIRECTION OUTPUT ;
    USE SIGNAL ;
    PORT
      LAYER M5 ;
        RECT 32.688 129.408 32.712 129.600 ;
    END
  END kv_waddr[8]
  PIN kv_waddr[9]
    DIRECTION OUTPUT ;
    USE SIGNAL ;
    PORT
      LAYER M3 ;
        RECT 33.117 129.408 33.141 129.600 ;
    END
  END kv_waddr[9]
  PIN kv_waddr[10]
    DIRECTION OUTPUT ;
    USE SIGNAL ;
    PORT
      LAYER M5 ;
        RECT 33.552 129.408 33.576 129.600 ;
    END
  END kv_waddr[10]
  PIN kv_waddr[11]
    DIRECTION OUTPUT ;
    USE SIGNAL ;
    PORT
      LAYER M3 ;
        RECT 34.017 129.408 34.041 129.600 ;
    END
  END kv_waddr[11]
  PIN kv_waddr[12]
    DIRECTION OUTPUT ;
    USE SIGNAL ;
    PORT
      LAYER M5 ;
        RECT 34.464 129.408 34.488 129.600 ;
    END
  END kv_waddr[12]
  PIN kv_waddr[13]
    DIRECTION OUTPUT ;
    USE SIGNAL ;
    PORT
      LAYER M3 ;
        RECT 34.917 129.408 34.941 129.600 ;
    END
  END kv_waddr[13]
  PIN kv_waddr[14]
    DIRECTION OUTPUT ;
    USE SIGNAL ;
    PORT
      LAYER M5 ;
        RECT 35.376 129.408 35.400 129.600 ;
    END
  END kv_waddr[14]
  PIN kv_waddr[15]
    DIRECTION OUTPUT ;
    USE SIGNAL ;
    PORT
      LAYER M3 ;
        RECT 35.817 129.408 35.841 129.600 ;
    END
  END kv_waddr[15]
  PIN kv_waddr[16]
    DIRECTION OUTPUT ;
    USE SIGNAL ;
    PORT
      LAYER M5 ;
        RECT 36.240 129.408 36.264 129.600 ;
    END
  END kv_waddr[16]
  PIN kv_waddr[17]
    DIRECTION OUTPUT ;
    USE SIGNAL ;
    PORT
      LAYER M3 ;
        RECT 36.681 129.408 36.705 129.600 ;
    END
  END kv_waddr[17]
  PIN kv_waddr[18]
    DIRECTION OUTPUT ;
    USE SIGNAL ;
    PORT
      LAYER M5 ;
        RECT 37.152 129.408 37.176 129.600 ;
    END
  END kv_waddr[18]
  PIN kv_waddr[19]
    DIRECTION OUTPUT ;
    USE SIGNAL ;
    PORT
      LAYER M3 ;
        RECT 37.581 129.408 37.605 129.600 ;
    END
  END kv_waddr[19]
  PIN kv_waddr[20]
    DIRECTION OUTPUT ;
    USE SIGNAL ;
    PORT
      LAYER M5 ;
        RECT 38.016 129.408 38.040 129.600 ;
    END
  END kv_waddr[20]
  PIN kv_waddr[21]
    DIRECTION OUTPUT ;
    USE SIGNAL ;
    PORT
      LAYER M3 ;
        RECT 38.481 129.408 38.505 129.600 ;
    END
  END kv_waddr[21]
  PIN kv_waddr[22]
    DIRECTION OUTPUT ;
    USE SIGNAL ;
    PORT
      LAYER M5 ;
        RECT 38.928 129.408 38.952 129.600 ;
    END
  END kv_waddr[22]
  PIN kv_waddr[23]
    DIRECTION OUTPUT ;
    USE SIGNAL ;
    PORT
      LAYER M3 ;
        RECT 39.381 129.408 39.405 129.600 ;
    END
  END kv_waddr[23]
  PIN kv_wdata[0]
    DIRECTION OUTPUT ;
    USE SIGNAL ;
    PORT
      LAYER M5 ;
        RECT 39.792 129.408 39.816 129.600 ;
    END
  END kv_wdata[0]
  PIN kv_wdata[1]
    DIRECTION OUTPUT ;
    USE SIGNAL ;
    PORT
      LAYER M3 ;
        RECT 40.245 129.408 40.269 129.600 ;
    END
  END kv_wdata[1]
  PIN kv_wdata[2]
    DIRECTION OUTPUT ;
    USE SIGNAL ;
    PORT
      LAYER M5 ;
        RECT 40.704 129.408 40.728 129.600 ;
    END
  END kv_wdata[2]
  PIN kv_wdata[3]
    DIRECTION OUTPUT ;
    USE SIGNAL ;
    PORT
      LAYER M3 ;
        RECT 41.145 129.408 41.169 129.600 ;
    END
  END kv_wdata[3]
  PIN kv_wdata[4]
    DIRECTION OUTPUT ;
    USE SIGNAL ;
    PORT
      LAYER M5 ;
        RECT 41.616 129.408 41.640 129.600 ;
    END
  END kv_wdata[4]
  PIN kv_wdata[5]
    DIRECTION OUTPUT ;
    USE SIGNAL ;
    PORT
      LAYER M3 ;
        RECT 42.045 129.408 42.069 129.600 ;
    END
  END kv_wdata[5]
  PIN kv_wdata[6]
    DIRECTION OUTPUT ;
    USE SIGNAL ;
    PORT
      LAYER M5 ;
        RECT 42.480 129.408 42.504 129.600 ;
    END
  END kv_wdata[6]
  PIN kv_wdata[7]
    DIRECTION OUTPUT ;
    USE SIGNAL ;
    PORT
      LAYER M3 ;
        RECT 42.945 129.408 42.969 129.600 ;
    END
  END kv_wdata[7]
  PIN kv_wdata[8]
    DIRECTION OUTPUT ;
    USE SIGNAL ;
    PORT
      LAYER M5 ;
        RECT 43.392 129.408 43.416 129.600 ;
    END
  END kv_wdata[8]
  PIN kv_wdata[9]
    DIRECTION OUTPUT ;
    USE SIGNAL ;
    PORT
      LAYER M3 ;
        RECT 43.809 129.408 43.833 129.600 ;
    END
  END kv_wdata[9]
  PIN kv_wdata[10]
    DIRECTION OUTPUT ;
    USE SIGNAL ;
    PORT
      LAYER M5 ;
        RECT 44.256 129.408 44.280 129.600 ;
    END
  END kv_wdata[10]
  PIN kv_wdata[11]
    DIRECTION OUTPUT ;
    USE SIGNAL ;
    PORT
      LAYER M3 ;
        RECT 44.709 129.408 44.733 129.600 ;
    END
  END kv_wdata[11]
  PIN kv_wdata[12]
    DIRECTION OUTPUT ;
    USE SIGNAL ;
    PORT
      LAYER M5 ;
        RECT 45.168 129.408 45.192 129.600 ;
    END
  END kv_wdata[12]
  PIN kv_wdata[13]
    DIRECTION OUTPUT ;
    USE SIGNAL ;
    PORT
      LAYER M3 ;
        RECT 45.609 129.408 45.633 129.600 ;
    END
  END kv_wdata[13]
  PIN kv_wdata[14]
    DIRECTION OUTPUT ;
    USE SIGNAL ;
    PORT
      LAYER M5 ;
        RECT 46.032 129.408 46.056 129.600 ;
    END
  END kv_wdata[14]
  PIN kv_wdata[15]
    DIRECTION OUTPUT ;
    USE SIGNAL ;
    PORT
      LAYER M3 ;
        RECT 46.509 129.408 46.533 129.600 ;
    END
  END kv_wdata[15]
  PIN kv_wdata[16]
    DIRECTION OUTPUT ;
    USE SIGNAL ;
    PORT
      LAYER M5 ;
        RECT 46.944 129.408 46.968 129.600 ;
    END
  END kv_wdata[16]
  PIN kv_wdata[17]
    DIRECTION OUTPUT ;
    USE SIGNAL ;
    PORT
      LAYER M3 ;
        RECT 47.373 129.408 47.397 129.600 ;
    END
  END kv_wdata[17]
  PIN kv_wdata[18]
    DIRECTION OUTPUT ;
    USE SIGNAL ;
    PORT
      LAYER M5 ;
        RECT 47.856 129.408 47.880 129.600 ;
    END
  END kv_wdata[18]
  PIN kv_wdata[19]
    DIRECTION OUTPUT ;
    USE SIGNAL ;
    PORT
      LAYER M3 ;
        RECT 48.273 129.408 48.297 129.600 ;
    END
  END kv_wdata[19]
  PIN kv_wdata[20]
    DIRECTION OUTPUT ;
    USE SIGNAL ;
    PORT
      LAYER M5 ;
        RECT 48.720 129.408 48.744 129.600 ;
    END
  END kv_wdata[20]
  PIN kv_wdata[21]
    DIRECTION OUTPUT ;
    USE SIGNAL ;
    PORT
      LAYER M3 ;
        RECT 49.173 129.408 49.197 129.600 ;
    END
  END kv_wdata[21]
  PIN kv_wdata[22]
    DIRECTION OUTPUT ;
    USE SIGNAL ;
    PORT
      LAYER M5 ;
        RECT 49.632 129.408 49.656 129.600 ;
    END
  END kv_wdata[22]
  PIN kv_wdata[23]
    DIRECTION OUTPUT ;
    USE SIGNAL ;
    PORT
      LAYER M3 ;
        RECT 50.073 129.408 50.097 129.600 ;
    END
  END kv_wdata[23]
  PIN kv_wdata[24]
    DIRECTION OUTPUT ;
    USE SIGNAL ;
    PORT
      LAYER M5 ;
        RECT 50.496 129.408 50.520 129.600 ;
    END
  END kv_wdata[24]
  PIN kv_wdata[25]
    DIRECTION OUTPUT ;
    USE SIGNAL ;
    PORT
      LAYER M3 ;
        RECT 50.937 129.408 50.961 129.600 ;
    END
  END kv_wdata[25]
  PIN kv_wdata[26]
    DIRECTION OUTPUT ;
    USE SIGNAL ;
    PORT
      LAYER M5 ;
        RECT 51.408 129.408 51.432 129.600 ;
    END
  END kv_wdata[26]
  PIN kv_wdata[27]
    DIRECTION OUTPUT ;
    USE SIGNAL ;
    PORT
      LAYER M3 ;
        RECT 51.837 129.408 51.861 129.600 ;
    END
  END kv_wdata[27]
  PIN kv_wdata[28]
    DIRECTION OUTPUT ;
    USE SIGNAL ;
    PORT
      LAYER M5 ;
        RECT 52.272 129.408 52.296 129.600 ;
    END
  END kv_wdata[28]
  PIN kv_wdata[29]
    DIRECTION OUTPUT ;
    USE SIGNAL ;
    PORT
      LAYER M3 ;
        RECT 52.737 129.408 52.761 129.600 ;
    END
  END kv_wdata[29]
  PIN kv_wdata[30]
    DIRECTION OUTPUT ;
    USE SIGNAL ;
    PORT
      LAYER M5 ;
        RECT 53.184 129.408 53.208 129.600 ;
    END
  END kv_wdata[30]
  PIN kv_wdata[31]
    DIRECTION OUTPUT ;
    USE SIGNAL ;
    PORT
      LAYER M3 ;
        RECT 53.637 129.408 53.661 129.600 ;
    END
  END kv_wdata[31]
  PIN l_ov
    DIRECTION OUTPUT ;
    USE SIGNAL ;
    PORT
      LAYER M5 ;
        RECT 54.096 129.408 54.120 129.600 ;
    END
  END l_ov
  PIN l_out[0]
    DIRECTION OUTPUT ;
    USE SIGNAL ;
    PORT
      LAYER M3 ;
        RECT 54.537 129.408 54.561 129.600 ;
    END
  END l_out[0]
  PIN l_out[1]
    DIRECTION OUTPUT ;
    USE SIGNAL ;
    PORT
      LAYER M5 ;
        RECT 54.960 129.408 54.984 129.600 ;
    END
  END l_out[1]
  PIN l_out[2]
    DIRECTION OUTPUT ;
    USE SIGNAL ;
    PORT
      LAYER M3 ;
        RECT 55.401 129.408 55.425 129.600 ;
    END
  END l_out[2]
  PIN l_out[3]
    DIRECTION OUTPUT ;
    USE SIGNAL ;
    PORT
      LAYER M5 ;
        RECT 55.872 129.408 55.896 129.600 ;
    END
  END l_out[3]
  PIN l_out[4]
    DIRECTION OUTPUT ;
    USE SIGNAL ;
    PORT
      LAYER M3 ;
        RECT 56.301 129.408 56.325 129.600 ;
    END
  END l_out[4]
  PIN l_out[5]
    DIRECTION OUTPUT ;
    USE SIGNAL ;
    PORT
      LAYER M5 ;
        RECT 56.736 129.408 56.760 129.600 ;
    END
  END l_out[5]
  PIN l_out[6]
    DIRECTION OUTPUT ;
    USE SIGNAL ;
    PORT
      LAYER M3 ;
        RECT 57.201 129.408 57.225 129.600 ;
    END
  END l_out[6]
  PIN l_out[7]
    DIRECTION OUTPUT ;
    USE SIGNAL ;
    PORT
      LAYER M5 ;
        RECT 57.648 129.408 57.672 129.600 ;
    END
  END l_out[7]
  PIN l_out[8]
    DIRECTION OUTPUT ;
    USE SIGNAL ;
    PORT
      LAYER M3 ;
        RECT 58.101 129.408 58.125 129.600 ;
    END
  END l_out[8]
  PIN l_out[9]
    DIRECTION OUTPUT ;
    USE SIGNAL ;
    PORT
      LAYER M5 ;
        RECT 58.512 129.408 58.536 129.600 ;
    END
  END l_out[9]
  PIN l_out[10]
    DIRECTION OUTPUT ;
    USE SIGNAL ;
    PORT
      LAYER M3 ;
        RECT 58.965 129.408 58.989 129.600 ;
    END
  END l_out[10]
  PIN l_out[11]
    DIRECTION OUTPUT ;
    USE SIGNAL ;
    PORT
      LAYER M5 ;
        RECT 59.424 129.408 59.448 129.600 ;
    END
  END l_out[11]
  PIN l_out[12]
    DIRECTION OUTPUT ;
    USE SIGNAL ;
    PORT
      LAYER M3 ;
        RECT 59.865 129.408 59.889 129.600 ;
    END
  END l_out[12]
  PIN l_out[13]
    DIRECTION OUTPUT ;
    USE SIGNAL ;
    PORT
      LAYER M5 ;
        RECT 60.336 129.408 60.360 129.600 ;
    END
  END l_out[13]
  PIN l_out[14]
    DIRECTION OUTPUT ;
    USE SIGNAL ;
    PORT
      LAYER M3 ;
        RECT 60.765 129.408 60.789 129.600 ;
    END
  END l_out[14]
  PIN l_out[15]
    DIRECTION OUTPUT ;
    USE SIGNAL ;
    PORT
      LAYER M5 ;
        RECT 61.200 129.408 61.224 129.600 ;
    END
  END l_out[15]
  PIN l_out[16]
    DIRECTION OUTPUT ;
    USE SIGNAL ;
    PORT
      LAYER M3 ;
        RECT 61.665 129.408 61.689 129.600 ;
    END
  END l_out[16]
  PIN l_out[17]
    DIRECTION OUTPUT ;
    USE SIGNAL ;
    PORT
      LAYER M5 ;
        RECT 62.112 129.408 62.136 129.600 ;
    END
  END l_out[17]
  PIN l_out[18]
    DIRECTION OUTPUT ;
    USE SIGNAL ;
    PORT
      LAYER M3 ;
        RECT 62.529 129.408 62.553 129.600 ;
    END
  END l_out[18]
  PIN l_out[19]
    DIRECTION OUTPUT ;
    USE SIGNAL ;
    PORT
      LAYER M5 ;
        RECT 62.976 129.408 63.000 129.600 ;
    END
  END l_out[19]
  PIN l_out[20]
    DIRECTION OUTPUT ;
    USE SIGNAL ;
    PORT
      LAYER M3 ;
        RECT 63.429 129.408 63.453 129.600 ;
    END
  END l_out[20]
  PIN l_out[21]
    DIRECTION OUTPUT ;
    USE SIGNAL ;
    PORT
      LAYER M5 ;
        RECT 63.888 129.408 63.912 129.600 ;
    END
  END l_out[21]
  PIN l_out[22]
    DIRECTION OUTPUT ;
    USE SIGNAL ;
    PORT
      LAYER M3 ;
        RECT 64.329 129.408 64.353 129.600 ;
    END
  END l_out[22]
  PIN l_out[23]
    DIRECTION OUTPUT ;
    USE SIGNAL ;
    PORT
      LAYER M5 ;
        RECT 64.752 129.408 64.776 129.600 ;
    END
  END l_out[23]
  PIN l_out[24]
    DIRECTION OUTPUT ;
    USE SIGNAL ;
    PORT
      LAYER M3 ;
        RECT 65.229 129.408 65.253 129.600 ;
    END
  END l_out[24]
  PIN l_out[25]
    DIRECTION OUTPUT ;
    USE SIGNAL ;
    PORT
      LAYER M5 ;
        RECT 65.664 129.408 65.688 129.600 ;
    END
  END l_out[25]
  PIN l_out[26]
    DIRECTION OUTPUT ;
    USE SIGNAL ;
    PORT
      LAYER M3 ;
        RECT 66.093 129.408 66.117 129.600 ;
    END
  END l_out[26]
  PIN l_out[27]
    DIRECTION OUTPUT ;
    USE SIGNAL ;
    PORT
      LAYER M5 ;
        RECT 66.576 129.408 66.600 129.600 ;
    END
  END l_out[27]
  PIN l_out[28]
    DIRECTION OUTPUT ;
    USE SIGNAL ;
    PORT
      LAYER M3 ;
        RECT 66.993 129.408 67.017 129.600 ;
    END
  END l_out[28]
  PIN l_out[29]
    DIRECTION OUTPUT ;
    USE SIGNAL ;
    PORT
      LAYER M5 ;
        RECT 67.440 129.408 67.464 129.600 ;
    END
  END l_out[29]
  PIN l_out[30]
    DIRECTION OUTPUT ;
    USE SIGNAL ;
    PORT
      LAYER M3 ;
        RECT 67.893 129.408 67.917 129.600 ;
    END
  END l_out[30]
  PIN l_out[31]
    DIRECTION OUTPUT ;
    USE SIGNAL ;
    PORT
      LAYER M5 ;
        RECT 68.352 129.408 68.376 129.600 ;
    END
  END l_out[31]
  PIN l_red[0]
    DIRECTION OUTPUT ;
    USE SIGNAL ;
    PORT
      LAYER M3 ;
        RECT 68.793 129.408 68.817 129.600 ;
    END
  END l_red[0]
  PIN l_red[1]
    DIRECTION OUTPUT ;
    USE SIGNAL ;
    PORT
      LAYER M5 ;
        RECT 69.216 129.408 69.240 129.600 ;
    END
  END l_red[1]
  PIN l_redsq
    DIRECTION OUTPUT ;
    USE SIGNAL ;
    PORT
      LAYER M3 ;
        RECT 69.657 129.408 69.681 129.600 ;
    END
  END l_redsq
  PIN l_raddr[0]
    DIRECTION OUTPUT ;
    USE SIGNAL ;
    PORT
      LAYER M5 ;
        RECT 70.128 129.408 70.152 129.600 ;
    END
  END l_raddr[0]
  PIN l_raddr[1]
    DIRECTION OUTPUT ;
    USE SIGNAL ;
    PORT
      LAYER M3 ;
        RECT 70.557 129.408 70.581 129.600 ;
    END
  END l_raddr[1]
  PIN l_raddr[2]
    DIRECTION OUTPUT ;
    USE SIGNAL ;
    PORT
      LAYER M5 ;
        RECT 70.992 129.408 71.016 129.600 ;
    END
  END l_raddr[2]
  PIN l_raddr[3]
    DIRECTION OUTPUT ;
    USE SIGNAL ;
    PORT
      LAYER M3 ;
        RECT 71.457 129.408 71.481 129.600 ;
    END
  END l_raddr[3]
  PIN l_raddr[4]
    DIRECTION OUTPUT ;
    USE SIGNAL ;
    PORT
      LAYER M5 ;
        RECT 71.904 129.408 71.928 129.600 ;
    END
  END l_raddr[4]
  PIN l_raddr[5]
    DIRECTION OUTPUT ;
    USE SIGNAL ;
    PORT
      LAYER M3 ;
        RECT 72.357 129.408 72.381 129.600 ;
    END
  END l_raddr[5]
  PIN l_raddr[6]
    DIRECTION OUTPUT ;
    USE SIGNAL ;
    PORT
      LAYER M5 ;
        RECT 72.816 129.408 72.840 129.600 ;
    END
  END l_raddr[6]
  PIN l_raddr[7]
    DIRECTION OUTPUT ;
    USE SIGNAL ;
    PORT
      LAYER M3 ;
        RECT 73.257 129.408 73.281 129.600 ;
    END
  END l_raddr[7]
  PIN l_raddr[8]
    DIRECTION OUTPUT ;
    USE SIGNAL ;
    PORT
      LAYER M5 ;
        RECT 73.680 129.408 73.704 129.600 ;
    END
  END l_raddr[8]
  PIN l_raddr[9]
    DIRECTION OUTPUT ;
    USE SIGNAL ;
    PORT
      LAYER M3 ;
        RECT 74.121 129.408 74.145 129.600 ;
    END
  END l_raddr[9]
  PIN l_raddr[10]
    DIRECTION OUTPUT ;
    USE SIGNAL ;
    PORT
      LAYER M5 ;
        RECT 74.592 129.408 74.616 129.600 ;
    END
  END l_raddr[10]
  PIN l_raddr[11]
    DIRECTION OUTPUT ;
    USE SIGNAL ;
    PORT
      LAYER M3 ;
        RECT 75.021 129.408 75.045 129.600 ;
    END
  END l_raddr[11]
  PIN l_raddr[12]
    DIRECTION OUTPUT ;
    USE SIGNAL ;
    PORT
      LAYER M5 ;
        RECT 75.456 129.408 75.480 129.600 ;
    END
  END l_raddr[12]
  PIN l_raddr[13]
    DIRECTION OUTPUT ;
    USE SIGNAL ;
    PORT
      LAYER M3 ;
        RECT 75.921 129.408 75.945 129.600 ;
    END
  END l_raddr[13]
  PIN l_raddr[14]
    DIRECTION OUTPUT ;
    USE SIGNAL ;
    PORT
      LAYER M5 ;
        RECT 76.368 129.408 76.392 129.600 ;
    END
  END l_raddr[14]
  PIN l_raddr[15]
    DIRECTION OUTPUT ;
    USE SIGNAL ;
    PORT
      LAYER M3 ;
        RECT 76.821 129.408 76.845 129.600 ;
    END
  END l_raddr[15]
  PIN l_raddr[16]
    DIRECTION OUTPUT ;
    USE SIGNAL ;
    PORT
      LAYER M5 ;
        RECT 77.232 129.408 77.256 129.600 ;
    END
  END l_raddr[16]
  PIN l_raddr[17]
    DIRECTION OUTPUT ;
    USE SIGNAL ;
    PORT
      LAYER M3 ;
        RECT 77.685 129.408 77.709 129.600 ;
    END
  END l_raddr[17]
  PIN l_raddr[18]
    DIRECTION OUTPUT ;
    USE SIGNAL ;
    PORT
      LAYER M5 ;
        RECT 78.144 129.408 78.168 129.600 ;
    END
  END l_raddr[18]
  PIN l_raddr[19]
    DIRECTION OUTPUT ;
    USE SIGNAL ;
    PORT
      LAYER M3 ;
        RECT 78.585 129.408 78.609 129.600 ;
    END
  END l_raddr[19]
  PIN l_raddr[20]
    DIRECTION OUTPUT ;
    USE SIGNAL ;
    PORT
      LAYER M5 ;
        RECT 79.056 129.408 79.080 129.600 ;
    END
  END l_raddr[20]
  PIN l_raddr[21]
    DIRECTION OUTPUT ;
    USE SIGNAL ;
    PORT
      LAYER M3 ;
        RECT 79.485 129.408 79.509 129.600 ;
    END
  END l_raddr[21]
  PIN l_raddr[22]
    DIRECTION OUTPUT ;
    USE SIGNAL ;
    PORT
      LAYER M5 ;
        RECT 79.920 129.408 79.944 129.600 ;
    END
  END l_raddr[22]
  PIN l_raddr[23]
    DIRECTION OUTPUT ;
    USE SIGNAL ;
    PORT
      LAYER M3 ;
        RECT 80.385 129.408 80.409 129.600 ;
    END
  END l_raddr[23]
  PIN l_last
    DIRECTION OUTPUT ;
    USE SIGNAL ;
    PORT
      LAYER M5 ;
        RECT 80.832 129.408 80.856 129.600 ;
    END
  END l_last
  PIN retire
    DIRECTION OUTPUT ;
    USE SIGNAL ;
    PORT
      LAYER M3 ;
        RECT 81.249 129.408 81.273 129.600 ;
    END
  END retire
  PIN l_fault
    DIRECTION OUTPUT ;
    USE SIGNAL ;
    PORT
      LAYER M5 ;
        RECT 81.696 129.408 81.720 129.600 ;
    END
  END l_fault
  PIN sx_exp_v
    DIRECTION OUTPUT ;
    USE SIGNAL ;
    PORT
      LAYER M3 ;
        RECT 82.149 129.408 82.173 129.600 ;
    END
  END sx_exp_v
  PIN sx_exp_x[0]
    DIRECTION OUTPUT ;
    USE SIGNAL ;
    PORT
      LAYER M5 ;
        RECT 82.608 129.408 82.632 129.600 ;
    END
  END sx_exp_x[0]
  PIN sx_exp_x[1]
    DIRECTION OUTPUT ;
    USE SIGNAL ;
    PORT
      LAYER M3 ;
        RECT 83.049 129.408 83.073 129.600 ;
    END
  END sx_exp_x[1]
  PIN sx_exp_x[2]
    DIRECTION OUTPUT ;
    USE SIGNAL ;
    PORT
      LAYER M5 ;
        RECT 83.472 129.408 83.496 129.600 ;
    END
  END sx_exp_x[2]
  PIN sx_exp_x[3]
    DIRECTION OUTPUT ;
    USE SIGNAL ;
    PORT
      LAYER M3 ;
        RECT 83.949 129.408 83.973 129.600 ;
    END
  END sx_exp_x[3]
  PIN sx_exp_x[4]
    DIRECTION OUTPUT ;
    USE SIGNAL ;
    PORT
      LAYER M5 ;
        RECT 84.384 129.408 84.408 129.600 ;
    END
  END sx_exp_x[4]
  PIN sx_exp_x[5]
    DIRECTION OUTPUT ;
    USE SIGNAL ;
    PORT
      LAYER M3 ;
        RECT 84.813 129.408 84.837 129.600 ;
    END
  END sx_exp_x[5]
  PIN sx_exp_x[6]
    DIRECTION OUTPUT ;
    USE SIGNAL ;
    PORT
      LAYER M5 ;
        RECT 85.296 129.408 85.320 129.600 ;
    END
  END sx_exp_x[6]
  PIN sx_exp_x[7]
    DIRECTION OUTPUT ;
    USE SIGNAL ;
    PORT
      LAYER M3 ;
        RECT 85.713 129.408 85.737 129.600 ;
    END
  END sx_exp_x[7]
  PIN sx_exp_x[8]
    DIRECTION OUTPUT ;
    USE SIGNAL ;
    PORT
      LAYER M5 ;
        RECT 86.160 129.408 86.184 129.600 ;
    END
  END sx_exp_x[8]
  PIN sx_exp_x[9]
    DIRECTION OUTPUT ;
    USE SIGNAL ;
    PORT
      LAYER M3 ;
        RECT 86.613 129.408 86.637 129.600 ;
    END
  END sx_exp_x[9]
  PIN sx_exp_x[10]
    DIRECTION OUTPUT ;
    USE SIGNAL ;
    PORT
      LAYER M5 ;
        RECT 87.072 129.408 87.096 129.600 ;
    END
  END sx_exp_x[10]
  PIN sx_exp_x[11]
    DIRECTION OUTPUT ;
    USE SIGNAL ;
    PORT
      LAYER M3 ;
        RECT 87.513 129.408 87.537 129.600 ;
    END
  END sx_exp_x[11]
  PIN sx_exp_x[12]
    DIRECTION OUTPUT ;
    USE SIGNAL ;
    PORT
      LAYER M5 ;
        RECT 87.936 129.408 87.960 129.600 ;
    END
  END sx_exp_x[12]
  PIN sx_exp_x[13]
    DIRECTION OUTPUT ;
    USE SIGNAL ;
    PORT
      LAYER M3 ;
        RECT 88.377 129.408 88.401 129.600 ;
    END
  END sx_exp_x[13]
  PIN sx_exp_x[14]
    DIRECTION OUTPUT ;
    USE SIGNAL ;
    PORT
      LAYER M5 ;
        RECT 88.848 129.408 88.872 129.600 ;
    END
  END sx_exp_x[14]
  PIN sx_exp_x[15]
    DIRECTION OUTPUT ;
    USE SIGNAL ;
    PORT
      LAYER M3 ;
        RECT 89.277 129.408 89.301 129.600 ;
    END
  END sx_exp_x[15]
  PIN sx_exp_x[16]
    DIRECTION OUTPUT ;
    USE SIGNAL ;
    PORT
      LAYER M5 ;
        RECT 89.712 129.408 89.736 129.600 ;
    END
  END sx_exp_x[16]
  PIN sx_exp_x[17]
    DIRECTION OUTPUT ;
    USE SIGNAL ;
    PORT
      LAYER M3 ;
        RECT 90.177 129.408 90.201 129.600 ;
    END
  END sx_exp_x[17]
  PIN sx_exp_x[18]
    DIRECTION OUTPUT ;
    USE SIGNAL ;
    PORT
      LAYER M5 ;
        RECT 90.624 129.408 90.648 129.600 ;
    END
  END sx_exp_x[18]
  PIN sx_exp_x[19]
    DIRECTION OUTPUT ;
    USE SIGNAL ;
    PORT
      LAYER M3 ;
        RECT 91.077 129.408 91.101 129.600 ;
    END
  END sx_exp_x[19]
  PIN sx_exp_x[20]
    DIRECTION OUTPUT ;
    USE SIGNAL ;
    PORT
      LAYER M5 ;
        RECT 91.536 129.408 91.560 129.600 ;
    END
  END sx_exp_x[20]
  PIN sx_exp_x[21]
    DIRECTION OUTPUT ;
    USE SIGNAL ;
    PORT
      LAYER M3 ;
        RECT 91.977 129.408 92.001 129.600 ;
    END
  END sx_exp_x[21]
  PIN sx_exp_x[22]
    DIRECTION OUTPUT ;
    USE SIGNAL ;
    PORT
      LAYER M5 ;
        RECT 92.400 129.408 92.424 129.600 ;
    END
  END sx_exp_x[22]
  PIN sx_exp_x[23]
    DIRECTION OUTPUT ;
    USE SIGNAL ;
    PORT
      LAYER M3 ;
        RECT 92.841 129.408 92.865 129.600 ;
    END
  END sx_exp_x[23]
  PIN sx_exp_x[24]
    DIRECTION OUTPUT ;
    USE SIGNAL ;
    PORT
      LAYER M5 ;
        RECT 93.312 129.408 93.336 129.600 ;
    END
  END sx_exp_x[24]
  PIN sx_exp_x[25]
    DIRECTION OUTPUT ;
    USE SIGNAL ;
    PORT
      LAYER M3 ;
        RECT 93.741 129.408 93.765 129.600 ;
    END
  END sx_exp_x[25]
  PIN sx_exp_x[26]
    DIRECTION OUTPUT ;
    USE SIGNAL ;
    PORT
      LAYER M5 ;
        RECT 94.176 129.408 94.200 129.600 ;
    END
  END sx_exp_x[26]
  PIN sx_exp_x[27]
    DIRECTION OUTPUT ;
    USE SIGNAL ;
    PORT
      LAYER M3 ;
        RECT 94.641 129.408 94.665 129.600 ;
    END
  END sx_exp_x[27]
  PIN sx_exp_x[28]
    DIRECTION OUTPUT ;
    USE SIGNAL ;
    PORT
      LAYER M5 ;
        RECT 95.088 129.408 95.112 129.600 ;
    END
  END sx_exp_x[28]
  PIN sx_exp_x[29]
    DIRECTION OUTPUT ;
    USE SIGNAL ;
    PORT
      LAYER M3 ;
        RECT 95.541 129.408 95.565 129.600 ;
    END
  END sx_exp_x[29]
  PIN sx_exp_x[30]
    DIRECTION OUTPUT ;
    USE SIGNAL ;
    PORT
      LAYER M5 ;
        RECT 95.952 129.408 95.976 129.600 ;
    END
  END sx_exp_x[30]
  PIN sx_exp_x[31]
    DIRECTION OUTPUT ;
    USE SIGNAL ;
    PORT
      LAYER M3 ;
        RECT 96.405 129.408 96.429 129.600 ;
    END
  END sx_exp_x[31]
  PIN sy_exp_y[0]
    DIRECTION INPUT ;
    USE SIGNAL ;
    PORT
      LAYER M5 ;
        RECT 96.864 129.408 96.888 129.600 ;
    END
  END sy_exp_y[0]
  PIN sy_exp_y[1]
    DIRECTION INPUT ;
    USE SIGNAL ;
    PORT
      LAYER M3 ;
        RECT 97.305 129.408 97.329 129.600 ;
    END
  END sy_exp_y[1]
  PIN sy_exp_y[2]
    DIRECTION INPUT ;
    USE SIGNAL ;
    PORT
      LAYER M5 ;
        RECT 97.776 129.408 97.800 129.600 ;
    END
  END sy_exp_y[2]
  PIN sy_exp_y[3]
    DIRECTION INPUT ;
    USE SIGNAL ;
    PORT
      LAYER M3 ;
        RECT 98.205 129.408 98.229 129.600 ;
    END
  END sy_exp_y[3]
  PIN sy_exp_y[4]
    DIRECTION INPUT ;
    USE SIGNAL ;
    PORT
      LAYER M5 ;
        RECT 98.640 129.408 98.664 129.600 ;
    END
  END sy_exp_y[4]
  PIN sy_exp_y[5]
    DIRECTION INPUT ;
    USE SIGNAL ;
    PORT
      LAYER M3 ;
        RECT 99.105 129.408 99.129 129.600 ;
    END
  END sy_exp_y[5]
  PIN sy_exp_y[6]
    DIRECTION INPUT ;
    USE SIGNAL ;
    PORT
      LAYER M5 ;
        RECT 99.552 129.408 99.576 129.600 ;
    END
  END sy_exp_y[6]
  PIN sy_exp_y[7]
    DIRECTION INPUT ;
    USE SIGNAL ;
    PORT
      LAYER M3 ;
        RECT 99.969 129.408 99.993 129.600 ;
    END
  END sy_exp_y[7]
  PIN sy_exp_y[8]
    DIRECTION INPUT ;
    USE SIGNAL ;
    PORT
      LAYER M5 ;
        RECT 100.416 129.408 100.440 129.600 ;
    END
  END sy_exp_y[8]
  PIN sy_exp_y[9]
    DIRECTION INPUT ;
    USE SIGNAL ;
    PORT
      LAYER M3 ;
        RECT 100.869 129.408 100.893 129.600 ;
    END
  END sy_exp_y[9]
  PIN sy_exp_y[10]
    DIRECTION INPUT ;
    USE SIGNAL ;
    PORT
      LAYER M5 ;
        RECT 101.328 129.408 101.352 129.600 ;
    END
  END sy_exp_y[10]
  PIN sy_exp_y[11]
    DIRECTION INPUT ;
    USE SIGNAL ;
    PORT
      LAYER M3 ;
        RECT 101.769 129.408 101.793 129.600 ;
    END
  END sy_exp_y[11]
  PIN sy_exp_y[12]
    DIRECTION INPUT ;
    USE SIGNAL ;
    PORT
      LAYER M5 ;
        RECT 102.192 129.408 102.216 129.600 ;
    END
  END sy_exp_y[12]
  PIN sy_exp_y[13]
    DIRECTION INPUT ;
    USE SIGNAL ;
    PORT
      LAYER M3 ;
        RECT 102.669 129.408 102.693 129.600 ;
    END
  END sy_exp_y[13]
  PIN sy_exp_y[14]
    DIRECTION INPUT ;
    USE SIGNAL ;
    PORT
      LAYER M5 ;
        RECT 103.104 129.408 103.128 129.600 ;
    END
  END sy_exp_y[14]
  PIN sy_exp_y[15]
    DIRECTION INPUT ;
    USE SIGNAL ;
    PORT
      LAYER M3 ;
        RECT 103.533 129.408 103.557 129.600 ;
    END
  END sy_exp_y[15]
  PIN sy_exp_y[16]
    DIRECTION INPUT ;
    USE SIGNAL ;
    PORT
      LAYER M5 ;
        RECT 104.016 129.408 104.040 129.600 ;
    END
  END sy_exp_y[16]
  PIN sy_exp_y[17]
    DIRECTION INPUT ;
    USE SIGNAL ;
    PORT
      LAYER M3 ;
        RECT 104.433 129.408 104.457 129.600 ;
    END
  END sy_exp_y[17]
  PIN sy_exp_y[18]
    DIRECTION INPUT ;
    USE SIGNAL ;
    PORT
      LAYER M5 ;
        RECT 104.880 129.408 104.904 129.600 ;
    END
  END sy_exp_y[18]
  PIN sy_exp_y[19]
    DIRECTION INPUT ;
    USE SIGNAL ;
    PORT
      LAYER M3 ;
        RECT 105.333 129.408 105.357 129.600 ;
    END
  END sy_exp_y[19]
  PIN sy_exp_y[20]
    DIRECTION INPUT ;
    USE SIGNAL ;
    PORT
      LAYER M5 ;
        RECT 105.792 129.408 105.816 129.600 ;
    END
  END sy_exp_y[20]
  PIN sy_exp_y[21]
    DIRECTION INPUT ;
    USE SIGNAL ;
    PORT
      LAYER M3 ;
        RECT 106.233 129.408 106.257 129.600 ;
    END
  END sy_exp_y[21]
  PIN sy_exp_y[22]
    DIRECTION INPUT ;
    USE SIGNAL ;
    PORT
      LAYER M5 ;
        RECT 106.656 129.408 106.680 129.600 ;
    END
  END sy_exp_y[22]
  PIN sy_exp_y[23]
    DIRECTION INPUT ;
    USE SIGNAL ;
    PORT
      LAYER M3 ;
        RECT 107.097 129.408 107.121 129.600 ;
    END
  END sy_exp_y[23]
  PIN sy_exp_y[24]
    DIRECTION INPUT ;
    USE SIGNAL ;
    PORT
      LAYER M5 ;
        RECT 107.568 129.408 107.592 129.600 ;
    END
  END sy_exp_y[24]
  PIN sy_exp_y[25]
    DIRECTION INPUT ;
    USE SIGNAL ;
    PORT
      LAYER M3 ;
        RECT 107.997 129.408 108.021 129.600 ;
    END
  END sy_exp_y[25]
  PIN sy_exp_y[26]
    DIRECTION INPUT ;
    USE SIGNAL ;
    PORT
      LAYER M5 ;
        RECT 108.432 129.408 108.456 129.600 ;
    END
  END sy_exp_y[26]
  PIN sy_exp_y[27]
    DIRECTION INPUT ;
    USE SIGNAL ;
    PORT
      LAYER M3 ;
        RECT 108.897 129.408 108.921 129.600 ;
    END
  END sy_exp_y[27]
  PIN sy_exp_y[28]
    DIRECTION INPUT ;
    USE SIGNAL ;
    PORT
      LAYER M5 ;
        RECT 109.344 129.408 109.368 129.600 ;
    END
  END sy_exp_y[28]
  PIN sy_exp_y[29]
    DIRECTION INPUT ;
    USE SIGNAL ;
    PORT
      LAYER M3 ;
        RECT 109.797 129.408 109.821 129.600 ;
    END
  END sy_exp_y[29]
  PIN sy_exp_y[30]
    DIRECTION INPUT ;
    USE SIGNAL ;
    PORT
      LAYER M5 ;
        RECT 110.256 129.408 110.280 129.600 ;
    END
  END sy_exp_y[30]
  PIN sy_exp_y[31]
    DIRECTION INPUT ;
    USE SIGNAL ;
    PORT
      LAYER M3 ;
        RECT 110.697 129.408 110.721 129.600 ;
    END
  END sy_exp_y[31]
  PIN sy_exp_vo
    DIRECTION INPUT ;
    USE SIGNAL ;
    PORT
      LAYER M5 ;
        RECT 111.120 129.408 111.144 129.600 ;
    END
  END sy_exp_vo
  PIN sy_exp_f
    DIRECTION INPUT ;
    USE SIGNAL ;
    PORT
      LAYER M3 ;
        RECT 111.561 129.408 111.585 129.600 ;
    END
  END sy_exp_f
  PIN sx_rcp_v
    DIRECTION OUTPUT ;
    USE SIGNAL ;
    PORT
      LAYER M5 ;
        RECT 112.032 129.408 112.056 129.600 ;
    END
  END sx_rcp_v
  PIN sx_rcp_x[0]
    DIRECTION OUTPUT ;
    USE SIGNAL ;
    PORT
      LAYER M3 ;
        RECT 112.461 129.408 112.485 129.600 ;
    END
  END sx_rcp_x[0]
  PIN sx_rcp_x[1]
    DIRECTION OUTPUT ;
    USE SIGNAL ;
    PORT
      LAYER M5 ;
        RECT 112.896 129.408 112.920 129.600 ;
    END
  END sx_rcp_x[1]
  PIN sx_rcp_x[2]
    DIRECTION OUTPUT ;
    USE SIGNAL ;
    PORT
      LAYER M3 ;
        RECT 113.361 129.408 113.385 129.600 ;
    END
  END sx_rcp_x[2]
  PIN sx_rcp_x[3]
    DIRECTION OUTPUT ;
    USE SIGNAL ;
    PORT
      LAYER M5 ;
        RECT 113.808 129.408 113.832 129.600 ;
    END
  END sx_rcp_x[3]
  PIN sx_rcp_x[4]
    DIRECTION OUTPUT ;
    USE SIGNAL ;
    PORT
      LAYER M3 ;
        RECT 114.261 129.408 114.285 129.600 ;
    END
  END sx_rcp_x[4]
  PIN sx_rcp_x[5]
    DIRECTION OUTPUT ;
    USE SIGNAL ;
    PORT
      LAYER M5 ;
        RECT 114.672 129.408 114.696 129.600 ;
    END
  END sx_rcp_x[5]
  PIN sx_rcp_x[6]
    DIRECTION OUTPUT ;
    USE SIGNAL ;
    PORT
      LAYER M3 ;
        RECT 115.125 129.408 115.149 129.600 ;
    END
  END sx_rcp_x[6]
  PIN sx_rcp_x[7]
    DIRECTION OUTPUT ;
    USE SIGNAL ;
    PORT
      LAYER M5 ;
        RECT 115.584 129.408 115.608 129.600 ;
    END
  END sx_rcp_x[7]
  PIN sx_rcp_x[8]
    DIRECTION OUTPUT ;
    USE SIGNAL ;
    PORT
      LAYER M3 ;
        RECT 116.025 129.408 116.049 129.600 ;
    END
  END sx_rcp_x[8]
  PIN sx_rcp_x[9]
    DIRECTION OUTPUT ;
    USE SIGNAL ;
    PORT
      LAYER M5 ;
        RECT 116.496 129.408 116.520 129.600 ;
    END
  END sx_rcp_x[9]
  PIN sx_rcp_x[10]
    DIRECTION OUTPUT ;
    USE SIGNAL ;
    PORT
      LAYER M3 ;
        RECT 116.925 129.408 116.949 129.600 ;
    END
  END sx_rcp_x[10]
  PIN sx_rcp_x[11]
    DIRECTION OUTPUT ;
    USE SIGNAL ;
    PORT
      LAYER M5 ;
        RECT 117.360 129.408 117.384 129.600 ;
    END
  END sx_rcp_x[11]
  PIN sx_rcp_x[12]
    DIRECTION OUTPUT ;
    USE SIGNAL ;
    PORT
      LAYER M3 ;
        RECT 117.825 129.408 117.849 129.600 ;
    END
  END sx_rcp_x[12]
  PIN sx_rcp_x[13]
    DIRECTION OUTPUT ;
    USE SIGNAL ;
    PORT
      LAYER M5 ;
        RECT 118.272 129.408 118.296 129.600 ;
    END
  END sx_rcp_x[13]
  PIN sx_rcp_x[14]
    DIRECTION OUTPUT ;
    USE SIGNAL ;
    PORT
      LAYER M3 ;
        RECT 118.689 129.408 118.713 129.600 ;
    END
  END sx_rcp_x[14]
  PIN sx_rcp_x[15]
    DIRECTION OUTPUT ;
    USE SIGNAL ;
    PORT
      LAYER M5 ;
        RECT 119.136 129.408 119.160 129.600 ;
    END
  END sx_rcp_x[15]
  PIN sx_rcp_x[16]
    DIRECTION OUTPUT ;
    USE SIGNAL ;
    PORT
      LAYER M3 ;
        RECT 119.589 129.408 119.613 129.600 ;
    END
  END sx_rcp_x[16]
  PIN sx_rcp_x[17]
    DIRECTION OUTPUT ;
    USE SIGNAL ;
    PORT
      LAYER M5 ;
        RECT 120.048 129.408 120.072 129.600 ;
    END
  END sx_rcp_x[17]
  PIN sx_rcp_x[18]
    DIRECTION OUTPUT ;
    USE SIGNAL ;
    PORT
      LAYER M3 ;
        RECT 120.489 129.408 120.513 129.600 ;
    END
  END sx_rcp_x[18]
  PIN sx_rcp_x[19]
    DIRECTION OUTPUT ;
    USE SIGNAL ;
    PORT
      LAYER M5 ;
        RECT 120.912 129.408 120.936 129.600 ;
    END
  END sx_rcp_x[19]
  PIN sx_rcp_x[20]
    DIRECTION OUTPUT ;
    USE SIGNAL ;
    PORT
      LAYER M3 ;
        RECT 121.389 129.408 121.413 129.600 ;
    END
  END sx_rcp_x[20]
  PIN sx_rcp_x[21]
    DIRECTION OUTPUT ;
    USE SIGNAL ;
    PORT
      LAYER M5 ;
        RECT 121.824 129.408 121.848 129.600 ;
    END
  END sx_rcp_x[21]
  PIN sx_rcp_x[22]
    DIRECTION OUTPUT ;
    USE SIGNAL ;
    PORT
      LAYER M3 ;
        RECT 122.253 129.408 122.277 129.600 ;
    END
  END sx_rcp_x[22]
  PIN sx_rcp_x[23]
    DIRECTION OUTPUT ;
    USE SIGNAL ;
    PORT
      LAYER M5 ;
        RECT 122.736 129.408 122.760 129.600 ;
    END
  END sx_rcp_x[23]
  PIN sx_rcp_x[24]
    DIRECTION OUTPUT ;
    USE SIGNAL ;
    PORT
      LAYER M3 ;
        RECT 123.153 129.408 123.177 129.600 ;
    END
  END sx_rcp_x[24]
  PIN sx_rcp_x[25]
    DIRECTION OUTPUT ;
    USE SIGNAL ;
    PORT
      LAYER M5 ;
        RECT 123.600 129.408 123.624 129.600 ;
    END
  END sx_rcp_x[25]
  PIN sx_rcp_x[26]
    DIRECTION OUTPUT ;
    USE SIGNAL ;
    PORT
      LAYER M3 ;
        RECT 124.053 129.408 124.077 129.600 ;
    END
  END sx_rcp_x[26]
  PIN sx_rcp_x[27]
    DIRECTION OUTPUT ;
    USE SIGNAL ;
    PORT
      LAYER M5 ;
        RECT 124.512 129.408 124.536 129.600 ;
    END
  END sx_rcp_x[27]
  PIN sx_rcp_x[28]
    DIRECTION OUTPUT ;
    USE SIGNAL ;
    PORT
      LAYER M3 ;
        RECT 124.953 129.408 124.977 129.600 ;
    END
  END sx_rcp_x[28]
  PIN sx_rcp_x[29]
    DIRECTION OUTPUT ;
    USE SIGNAL ;
    PORT
      LAYER M5 ;
        RECT 125.376 129.408 125.400 129.600 ;
    END
  END sx_rcp_x[29]
  PIN sx_rcp_x[30]
    DIRECTION OUTPUT ;
    USE SIGNAL ;
    PORT
      LAYER M3 ;
        RECT 125.817 129.408 125.841 129.600 ;
    END
  END sx_rcp_x[30]
  PIN sx_rcp_x[31]
    DIRECTION OUTPUT ;
    USE SIGNAL ;
    PORT
      LAYER M5 ;
        RECT 126.288 129.408 126.312 129.600 ;
    END
  END sx_rcp_x[31]
  PIN sy_rcp_y[0]
    DIRECTION INPUT ;
    USE SIGNAL ;
    PORT
      LAYER M3 ;
        RECT 126.717 129.408 126.741 129.600 ;
    END
  END sy_rcp_y[0]
  PIN sy_rcp_y[1]
    DIRECTION INPUT ;
    USE SIGNAL ;
    PORT
      LAYER M5 ;
        RECT 127.152 129.408 127.176 129.600 ;
    END
  END sy_rcp_y[1]
  PIN sy_rcp_y[2]
    DIRECTION INPUT ;
    USE SIGNAL ;
    PORT
      LAYER M3 ;
        RECT 127.617 129.408 127.641 129.600 ;
    END
  END sy_rcp_y[2]
  PIN sy_rcp_y[3]
    DIRECTION INPUT ;
    USE SIGNAL ;
    PORT
      LAYER M5 ;
        RECT 128.064 129.408 128.088 129.600 ;
    END
  END sy_rcp_y[3]
  PIN sy_rcp_y[4]
    DIRECTION INPUT ;
    USE SIGNAL ;
    PORT
      LAYER M3 ;
        RECT 128.517 129.408 128.541 129.600 ;
    END
  END sy_rcp_y[4]
  PIN sy_rcp_y[5]
    DIRECTION INPUT ;
    USE SIGNAL ;
    PORT
      LAYER M5 ;
        RECT 128.976 129.408 129.000 129.600 ;
    END
  END sy_rcp_y[5]
  PIN sy_rcp_y[6]
    DIRECTION INPUT ;
    USE SIGNAL ;
    PORT
      LAYER M3 ;
        RECT 129.417 129.408 129.441 129.600 ;
    END
  END sy_rcp_y[6]
  PIN sy_rcp_y[7]
    DIRECTION INPUT ;
    USE SIGNAL ;
    PORT
      LAYER M5 ;
        RECT 129.840 129.408 129.864 129.600 ;
    END
  END sy_rcp_y[7]
  PIN sy_rcp_y[8]
    DIRECTION INPUT ;
    USE SIGNAL ;
    PORT
      LAYER M3 ;
        RECT 130.281 129.408 130.305 129.600 ;
    END
  END sy_rcp_y[8]
  PIN sy_rcp_y[9]
    DIRECTION INPUT ;
    USE SIGNAL ;
    PORT
      LAYER M5 ;
        RECT 130.752 129.408 130.776 129.600 ;
    END
  END sy_rcp_y[9]
  PIN sy_rcp_y[10]
    DIRECTION INPUT ;
    USE SIGNAL ;
    PORT
      LAYER M3 ;
        RECT 131.181 129.408 131.205 129.600 ;
    END
  END sy_rcp_y[10]
  PIN sy_rcp_y[11]
    DIRECTION INPUT ;
    USE SIGNAL ;
    PORT
      LAYER M5 ;
        RECT 131.616 129.408 131.640 129.600 ;
    END
  END sy_rcp_y[11]
  PIN sy_rcp_y[12]
    DIRECTION INPUT ;
    USE SIGNAL ;
    PORT
      LAYER M3 ;
        RECT 132.081 129.408 132.105 129.600 ;
    END
  END sy_rcp_y[12]
  PIN sy_rcp_y[13]
    DIRECTION INPUT ;
    USE SIGNAL ;
    PORT
      LAYER M5 ;
        RECT 132.528 129.408 132.552 129.600 ;
    END
  END sy_rcp_y[13]
  PIN sy_rcp_y[14]
    DIRECTION INPUT ;
    USE SIGNAL ;
    PORT
      LAYER M3 ;
        RECT 132.981 129.408 133.005 129.600 ;
    END
  END sy_rcp_y[14]
  PIN sy_rcp_y[15]
    DIRECTION INPUT ;
    USE SIGNAL ;
    PORT
      LAYER M5 ;
        RECT 133.392 129.408 133.416 129.600 ;
    END
  END sy_rcp_y[15]
  PIN sy_rcp_y[16]
    DIRECTION INPUT ;
    USE SIGNAL ;
    PORT
      LAYER M3 ;
        RECT 133.845 129.408 133.869 129.600 ;
    END
  END sy_rcp_y[16]
  PIN sy_rcp_y[17]
    DIRECTION INPUT ;
    USE SIGNAL ;
    PORT
      LAYER M5 ;
        RECT 134.304 129.408 134.328 129.600 ;
    END
  END sy_rcp_y[17]
  PIN sy_rcp_y[18]
    DIRECTION INPUT ;
    USE SIGNAL ;
    PORT
      LAYER M3 ;
        RECT 134.745 129.408 134.769 129.600 ;
    END
  END sy_rcp_y[18]
  PIN sy_rcp_y[19]
    DIRECTION INPUT ;
    USE SIGNAL ;
    PORT
      LAYER M5 ;
        RECT 135.216 129.408 135.240 129.600 ;
    END
  END sy_rcp_y[19]
  PIN sy_rcp_y[20]
    DIRECTION INPUT ;
    USE SIGNAL ;
    PORT
      LAYER M3 ;
        RECT 135.645 129.408 135.669 129.600 ;
    END
  END sy_rcp_y[20]
  PIN sy_rcp_y[21]
    DIRECTION INPUT ;
    USE SIGNAL ;
    PORT
      LAYER M5 ;
        RECT 136.080 129.408 136.104 129.600 ;
    END
  END sy_rcp_y[21]
  PIN sy_rcp_y[22]
    DIRECTION INPUT ;
    USE SIGNAL ;
    PORT
      LAYER M3 ;
        RECT 136.545 129.408 136.569 129.600 ;
    END
  END sy_rcp_y[22]
  PIN sy_rcp_y[23]
    DIRECTION INPUT ;
    USE SIGNAL ;
    PORT
      LAYER M5 ;
        RECT 136.992 129.408 137.016 129.600 ;
    END
  END sy_rcp_y[23]
  PIN sy_rcp_y[24]
    DIRECTION INPUT ;
    USE SIGNAL ;
    PORT
      LAYER M3 ;
        RECT 137.409 129.408 137.433 129.600 ;
    END
  END sy_rcp_y[24]
  PIN sy_rcp_y[25]
    DIRECTION INPUT ;
    USE SIGNAL ;
    PORT
      LAYER M5 ;
        RECT 137.856 129.408 137.880 129.600 ;
    END
  END sy_rcp_y[25]
  PIN sy_rcp_y[26]
    DIRECTION INPUT ;
    USE SIGNAL ;
    PORT
      LAYER M3 ;
        RECT 138.309 129.408 138.333 129.600 ;
    END
  END sy_rcp_y[26]
  PIN sy_rcp_y[27]
    DIRECTION INPUT ;
    USE SIGNAL ;
    PORT
      LAYER M5 ;
        RECT 138.768 129.408 138.792 129.600 ;
    END
  END sy_rcp_y[27]
  PIN sy_rcp_y[28]
    DIRECTION INPUT ;
    USE SIGNAL ;
    PORT
      LAYER M3 ;
        RECT 139.209 129.408 139.233 129.600 ;
    END
  END sy_rcp_y[28]
  PIN sy_rcp_y[29]
    DIRECTION INPUT ;
    USE SIGNAL ;
    PORT
      LAYER M5 ;
        RECT 139.632 129.408 139.656 129.600 ;
    END
  END sy_rcp_y[29]
  PIN sy_rcp_y[30]
    DIRECTION INPUT ;
    USE SIGNAL ;
    PORT
      LAYER M3 ;
        RECT 140.109 129.408 140.133 129.600 ;
    END
  END sy_rcp_y[30]
  PIN sy_rcp_y[31]
    DIRECTION INPUT ;
    USE SIGNAL ;
    PORT
      LAYER M5 ;
        RECT 140.544 129.408 140.568 129.600 ;
    END
  END sy_rcp_y[31]
  PIN sy_rcp_f
    DIRECTION INPUT ;
    USE SIGNAL ;
    PORT
      LAYER M3 ;
        RECT 140.973 129.408 140.997 129.600 ;
    END
  END sy_rcp_f
  PIN sx_rsq_v
    DIRECTION OUTPUT ;
    USE SIGNAL ;
    PORT
      LAYER M5 ;
        RECT 141.456 129.408 141.480 129.600 ;
    END
  END sx_rsq_v
  PIN sx_rsq_x[0]
    DIRECTION OUTPUT ;
    USE SIGNAL ;
    PORT
      LAYER M3 ;
        RECT 141.873 129.408 141.897 129.600 ;
    END
  END sx_rsq_x[0]
  PIN sx_rsq_x[1]
    DIRECTION OUTPUT ;
    USE SIGNAL ;
    PORT
      LAYER M5 ;
        RECT 142.320 129.408 142.344 129.600 ;
    END
  END sx_rsq_x[1]
  PIN sx_rsq_x[2]
    DIRECTION OUTPUT ;
    USE SIGNAL ;
    PORT
      LAYER M3 ;
        RECT 142.773 129.408 142.797 129.600 ;
    END
  END sx_rsq_x[2]
  PIN sx_rsq_x[3]
    DIRECTION OUTPUT ;
    USE SIGNAL ;
    PORT
      LAYER M5 ;
        RECT 143.232 129.408 143.256 129.600 ;
    END
  END sx_rsq_x[3]
  PIN sx_rsq_x[4]
    DIRECTION OUTPUT ;
    USE SIGNAL ;
    PORT
      LAYER M3 ;
        RECT 143.673 129.408 143.697 129.600 ;
    END
  END sx_rsq_x[4]
  PIN sx_rsq_x[5]
    DIRECTION OUTPUT ;
    USE SIGNAL ;
    PORT
      LAYER M5 ;
        RECT 144.096 129.408 144.120 129.600 ;
    END
  END sx_rsq_x[5]
  PIN sx_rsq_x[6]
    DIRECTION OUTPUT ;
    USE SIGNAL ;
    PORT
      LAYER M3 ;
        RECT 144.537 129.408 144.561 129.600 ;
    END
  END sx_rsq_x[6]
  PIN sx_rsq_x[7]
    DIRECTION OUTPUT ;
    USE SIGNAL ;
    PORT
      LAYER M5 ;
        RECT 145.008 129.408 145.032 129.600 ;
    END
  END sx_rsq_x[7]
  PIN sx_rsq_x[8]
    DIRECTION OUTPUT ;
    USE SIGNAL ;
    PORT
      LAYER M3 ;
        RECT 145.437 129.408 145.461 129.600 ;
    END
  END sx_rsq_x[8]
  PIN sx_rsq_x[9]
    DIRECTION OUTPUT ;
    USE SIGNAL ;
    PORT
      LAYER M5 ;
        RECT 145.872 129.408 145.896 129.600 ;
    END
  END sx_rsq_x[9]
  PIN sx_rsq_x[10]
    DIRECTION OUTPUT ;
    USE SIGNAL ;
    PORT
      LAYER M3 ;
        RECT 146.337 129.408 146.361 129.600 ;
    END
  END sx_rsq_x[10]
  PIN sx_rsq_x[11]
    DIRECTION OUTPUT ;
    USE SIGNAL ;
    PORT
      LAYER M5 ;
        RECT 146.784 129.408 146.808 129.600 ;
    END
  END sx_rsq_x[11]
  PIN sx_rsq_x[12]
    DIRECTION OUTPUT ;
    USE SIGNAL ;
    PORT
      LAYER M3 ;
        RECT 147.237 129.408 147.261 129.600 ;
    END
  END sx_rsq_x[12]
  PIN sx_rsq_x[13]
    DIRECTION OUTPUT ;
    USE SIGNAL ;
    PORT
      LAYER M5 ;
        RECT 147.696 129.408 147.720 129.600 ;
    END
  END sx_rsq_x[13]
  PIN sx_rsq_x[14]
    DIRECTION OUTPUT ;
    USE SIGNAL ;
    PORT
      LAYER M3 ;
        RECT 148.137 129.408 148.161 129.600 ;
    END
  END sx_rsq_x[14]
  PIN sx_rsq_x[15]
    DIRECTION OUTPUT ;
    USE SIGNAL ;
    PORT
      LAYER M5 ;
        RECT 148.560 129.408 148.584 129.600 ;
    END
  END sx_rsq_x[15]
  PIN sx_rsq_x[16]
    DIRECTION OUTPUT ;
    USE SIGNAL ;
    PORT
      LAYER M3 ;
        RECT 149.001 129.408 149.025 129.600 ;
    END
  END sx_rsq_x[16]
  PIN sx_rsq_x[17]
    DIRECTION OUTPUT ;
    USE SIGNAL ;
    PORT
      LAYER M5 ;
        RECT 149.472 129.408 149.496 129.600 ;
    END
  END sx_rsq_x[17]
  PIN sx_rsq_x[18]
    DIRECTION OUTPUT ;
    USE SIGNAL ;
    PORT
      LAYER M3 ;
        RECT 149.901 129.408 149.925 129.600 ;
    END
  END sx_rsq_x[18]
  PIN sx_rsq_x[19]
    DIRECTION OUTPUT ;
    USE SIGNAL ;
    PORT
      LAYER M5 ;
        RECT 150.336 129.408 150.360 129.600 ;
    END
  END sx_rsq_x[19]
  PIN sx_rsq_x[20]
    DIRECTION OUTPUT ;
    USE SIGNAL ;
    PORT
      LAYER M3 ;
        RECT 150.801 129.408 150.825 129.600 ;
    END
  END sx_rsq_x[20]
  PIN sx_rsq_x[21]
    DIRECTION OUTPUT ;
    USE SIGNAL ;
    PORT
      LAYER M5 ;
        RECT 151.248 129.408 151.272 129.600 ;
    END
  END sx_rsq_x[21]
  PIN sx_rsq_x[22]
    DIRECTION OUTPUT ;
    USE SIGNAL ;
    PORT
      LAYER M3 ;
        RECT 151.701 129.408 151.725 129.600 ;
    END
  END sx_rsq_x[22]
  PIN sx_rsq_x[23]
    DIRECTION OUTPUT ;
    USE SIGNAL ;
    PORT
      LAYER M5 ;
        RECT 152.112 129.408 152.136 129.600 ;
    END
  END sx_rsq_x[23]
  PIN sx_rsq_x[24]
    DIRECTION OUTPUT ;
    USE SIGNAL ;
    PORT
      LAYER M3 ;
        RECT 152.565 129.408 152.589 129.600 ;
    END
  END sx_rsq_x[24]
  PIN sx_rsq_x[25]
    DIRECTION OUTPUT ;
    USE SIGNAL ;
    PORT
      LAYER M5 ;
        RECT 153.024 129.408 153.048 129.600 ;
    END
  END sx_rsq_x[25]
  PIN sx_rsq_x[26]
    DIRECTION OUTPUT ;
    USE SIGNAL ;
    PORT
      LAYER M3 ;
        RECT 153.465 129.408 153.489 129.600 ;
    END
  END sx_rsq_x[26]
  PIN sx_rsq_x[27]
    DIRECTION OUTPUT ;
    USE SIGNAL ;
    PORT
      LAYER M5 ;
        RECT 153.936 129.408 153.960 129.600 ;
    END
  END sx_rsq_x[27]
  PIN sx_rsq_x[28]
    DIRECTION OUTPUT ;
    USE SIGNAL ;
    PORT
      LAYER M3 ;
        RECT 154.365 129.408 154.389 129.600 ;
    END
  END sx_rsq_x[28]
  PIN sx_rsq_x[29]
    DIRECTION OUTPUT ;
    USE SIGNAL ;
    PORT
      LAYER M5 ;
        RECT 154.800 129.408 154.824 129.600 ;
    END
  END sx_rsq_x[29]
  PIN sx_rsq_x[30]
    DIRECTION OUTPUT ;
    USE SIGNAL ;
    PORT
      LAYER M3 ;
        RECT 155.265 129.408 155.289 129.600 ;
    END
  END sx_rsq_x[30]
  PIN sx_rsq_x[31]
    DIRECTION OUTPUT ;
    USE SIGNAL ;
    PORT
      LAYER M5 ;
        RECT 155.712 129.408 155.736 129.600 ;
    END
  END sx_rsq_x[31]
  PIN sy_rsq_y[0]
    DIRECTION INPUT ;
    USE SIGNAL ;
    PORT
      LAYER M3 ;
        RECT 156.129 129.408 156.153 129.600 ;
    END
  END sy_rsq_y[0]
  PIN sy_rsq_y[1]
    DIRECTION INPUT ;
    USE SIGNAL ;
    PORT
      LAYER M5 ;
        RECT 156.576 129.408 156.600 129.600 ;
    END
  END sy_rsq_y[1]
  PIN sy_rsq_y[2]
    DIRECTION INPUT ;
    USE SIGNAL ;
    PORT
      LAYER M3 ;
        RECT 157.029 129.408 157.053 129.600 ;
    END
  END sy_rsq_y[2]
  PIN sy_rsq_y[3]
    DIRECTION INPUT ;
    USE SIGNAL ;
    PORT
      LAYER M5 ;
        RECT 157.488 129.408 157.512 129.600 ;
    END
  END sy_rsq_y[3]
  PIN sy_rsq_y[4]
    DIRECTION INPUT ;
    USE SIGNAL ;
    PORT
      LAYER M3 ;
        RECT 157.929 129.408 157.953 129.600 ;
    END
  END sy_rsq_y[4]
  PIN sy_rsq_y[5]
    DIRECTION INPUT ;
    USE SIGNAL ;
    PORT
      LAYER M5 ;
        RECT 158.352 129.408 158.376 129.600 ;
    END
  END sy_rsq_y[5]
  PIN sy_rsq_y[6]
    DIRECTION INPUT ;
    USE SIGNAL ;
    PORT
      LAYER M3 ;
        RECT 158.829 129.408 158.853 129.600 ;
    END
  END sy_rsq_y[6]
  PIN sy_rsq_y[7]
    DIRECTION INPUT ;
    USE SIGNAL ;
    PORT
      LAYER M5 ;
        RECT 159.264 129.408 159.288 129.600 ;
    END
  END sy_rsq_y[7]
  PIN sy_rsq_y[8]
    DIRECTION INPUT ;
    USE SIGNAL ;
    PORT
      LAYER M3 ;
        RECT 159.693 129.408 159.717 129.600 ;
    END
  END sy_rsq_y[8]
  PIN sy_rsq_y[9]
    DIRECTION INPUT ;
    USE SIGNAL ;
    PORT
      LAYER M5 ;
        RECT 160.176 129.408 160.200 129.600 ;
    END
  END sy_rsq_y[9]
  PIN sy_rsq_y[10]
    DIRECTION INPUT ;
    USE SIGNAL ;
    PORT
      LAYER M3 ;
        RECT 160.593 129.408 160.617 129.600 ;
    END
  END sy_rsq_y[10]
  PIN sy_rsq_y[11]
    DIRECTION INPUT ;
    USE SIGNAL ;
    PORT
      LAYER M5 ;
        RECT 161.040 129.408 161.064 129.600 ;
    END
  END sy_rsq_y[11]
  PIN sy_rsq_y[12]
    DIRECTION INPUT ;
    USE SIGNAL ;
    PORT
      LAYER M3 ;
        RECT 161.493 129.408 161.517 129.600 ;
    END
  END sy_rsq_y[12]
  PIN sy_rsq_y[13]
    DIRECTION INPUT ;
    USE SIGNAL ;
    PORT
      LAYER M5 ;
        RECT 161.952 129.408 161.976 129.600 ;
    END
  END sy_rsq_y[13]
  PIN sy_rsq_y[14]
    DIRECTION INPUT ;
    USE SIGNAL ;
    PORT
      LAYER M3 ;
        RECT 162.393 129.408 162.417 129.600 ;
    END
  END sy_rsq_y[14]
  PIN sy_rsq_y[15]
    DIRECTION INPUT ;
    USE SIGNAL ;
    PORT
      LAYER M5 ;
        RECT 162.816 129.408 162.840 129.600 ;
    END
  END sy_rsq_y[15]
  PIN sy_rsq_y[16]
    DIRECTION INPUT ;
    USE SIGNAL ;
    PORT
      LAYER M3 ;
        RECT 163.257 129.408 163.281 129.600 ;
    END
  END sy_rsq_y[16]
  PIN sy_rsq_y[17]
    DIRECTION INPUT ;
    USE SIGNAL ;
    PORT
      LAYER M5 ;
        RECT 163.728 129.408 163.752 129.600 ;
    END
  END sy_rsq_y[17]
  PIN sy_rsq_y[18]
    DIRECTION INPUT ;
    USE SIGNAL ;
    PORT
      LAYER M3 ;
        RECT 164.157 129.408 164.181 129.600 ;
    END
  END sy_rsq_y[18]
  PIN sy_rsq_y[19]
    DIRECTION INPUT ;
    USE SIGNAL ;
    PORT
      LAYER M5 ;
        RECT 164.592 129.408 164.616 129.600 ;
    END
  END sy_rsq_y[19]
  PIN sy_rsq_y[20]
    DIRECTION INPUT ;
    USE SIGNAL ;
    PORT
      LAYER M3 ;
        RECT 165.057 129.408 165.081 129.600 ;
    END
  END sy_rsq_y[20]
  PIN sy_rsq_y[21]
    DIRECTION INPUT ;
    USE SIGNAL ;
    PORT
      LAYER M5 ;
        RECT 165.504 129.408 165.528 129.600 ;
    END
  END sy_rsq_y[21]
  PIN sy_rsq_y[22]
    DIRECTION INPUT ;
    USE SIGNAL ;
    PORT
      LAYER M3 ;
        RECT 165.957 129.408 165.981 129.600 ;
    END
  END sy_rsq_y[22]
  PIN sy_rsq_y[23]
    DIRECTION INPUT ;
    USE SIGNAL ;
    PORT
      LAYER M5 ;
        RECT 166.416 129.408 166.440 129.600 ;
    END
  END sy_rsq_y[23]
  PIN sy_rsq_y[24]
    DIRECTION INPUT ;
    USE SIGNAL ;
    PORT
      LAYER M3 ;
        RECT 166.857 129.408 166.881 129.600 ;
    END
  END sy_rsq_y[24]
  PIN sy_rsq_y[25]
    DIRECTION INPUT ;
    USE SIGNAL ;
    PORT
      LAYER M5 ;
        RECT 167.280 129.408 167.304 129.600 ;
    END
  END sy_rsq_y[25]
  PIN sy_rsq_y[26]
    DIRECTION INPUT ;
    USE SIGNAL ;
    PORT
      LAYER M3 ;
        RECT 167.721 129.408 167.745 129.600 ;
    END
  END sy_rsq_y[26]
  PIN sy_rsq_y[27]
    DIRECTION INPUT ;
    USE SIGNAL ;
    PORT
      LAYER M5 ;
        RECT 168.192 129.408 168.216 129.600 ;
    END
  END sy_rsq_y[27]
  PIN sy_rsq_y[28]
    DIRECTION INPUT ;
    USE SIGNAL ;
    PORT
      LAYER M3 ;
        RECT 168.621 129.408 168.645 129.600 ;
    END
  END sy_rsq_y[28]
  PIN sy_rsq_y[29]
    DIRECTION INPUT ;
    USE SIGNAL ;
    PORT
      LAYER M5 ;
        RECT 169.056 129.408 169.080 129.600 ;
    END
  END sy_rsq_y[29]
  PIN sy_rsq_y[30]
    DIRECTION INPUT ;
    USE SIGNAL ;
    PORT
      LAYER M3 ;
        RECT 169.521 129.408 169.545 129.600 ;
    END
  END sy_rsq_y[30]
  PIN sy_rsq_y[31]
    DIRECTION INPUT ;
    USE SIGNAL ;
    PORT
      LAYER M5 ;
        RECT 169.968 129.408 169.992 129.600 ;
    END
  END sy_rsq_y[31]
  PIN sy_rsq_f
    DIRECTION INPUT ;
    USE SIGNAL ;
    PORT
      LAYER M3 ;
        RECT 170.421 129.408 170.445 129.600 ;
    END
  END sy_rsq_f
  PIN VDD
    DIRECTION INOUT ;
    USE POWER ;
    PORT
      LAYER M5 ;
        RECT 2.460 0.500 2.580 129.100 ;
        RECT 7.860 0.500 7.980 129.100 ;
        RECT 13.260 0.500 13.380 129.100 ;
        RECT 18.660 0.500 18.780 129.100 ;
        RECT 24.060 0.500 24.180 129.100 ;
        RECT 29.460 0.500 29.580 129.100 ;
        RECT 34.860 0.500 34.980 129.100 ;
        RECT 40.260 0.500 40.380 129.100 ;
        RECT 45.660 0.500 45.780 129.100 ;
        RECT 51.060 0.500 51.180 129.100 ;
        RECT 56.460 0.500 56.580 129.100 ;
        RECT 61.860 0.500 61.980 129.100 ;
        RECT 67.260 0.500 67.380 129.100 ;
        RECT 72.660 0.500 72.780 129.100 ;
        RECT 78.060 0.500 78.180 129.100 ;
        RECT 83.460 0.500 83.580 129.100 ;
        RECT 88.860 0.500 88.980 129.100 ;
        RECT 94.260 0.500 94.380 129.100 ;
        RECT 99.660 0.500 99.780 129.100 ;
        RECT 105.060 0.500 105.180 129.100 ;
        RECT 110.460 0.500 110.580 129.100 ;
        RECT 115.860 0.500 115.980 129.100 ;
        RECT 121.260 0.500 121.380 129.100 ;
        RECT 126.660 0.500 126.780 129.100 ;
        RECT 132.060 0.500 132.180 129.100 ;
        RECT 137.460 0.500 137.580 129.100 ;
        RECT 142.860 0.500 142.980 129.100 ;
        RECT 148.260 0.500 148.380 129.100 ;
        RECT 153.660 0.500 153.780 129.100 ;
        RECT 159.060 0.500 159.180 129.100 ;
        RECT 164.460 0.500 164.580 129.100 ;
        RECT 169.860 0.500 169.980 129.100 ;
    END
  END VDD
  PIN VSS
    DIRECTION INOUT ;
    USE GROUND ;
    PORT
      LAYER M5 ;
        RECT 2.652 0.500 2.772 129.100 ;
        RECT 8.052 0.500 8.172 129.100 ;
        RECT 13.452 0.500 13.572 129.100 ;
        RECT 18.852 0.500 18.972 129.100 ;
        RECT 24.252 0.500 24.372 129.100 ;
        RECT 29.652 0.500 29.772 129.100 ;
        RECT 35.052 0.500 35.172 129.100 ;
        RECT 40.452 0.500 40.572 129.100 ;
        RECT 45.852 0.500 45.972 129.100 ;
        RECT 51.252 0.500 51.372 129.100 ;
        RECT 56.652 0.500 56.772 129.100 ;
        RECT 62.052 0.500 62.172 129.100 ;
        RECT 67.452 0.500 67.572 129.100 ;
        RECT 72.852 0.500 72.972 129.100 ;
        RECT 78.252 0.500 78.372 129.100 ;
        RECT 83.652 0.500 83.772 129.100 ;
        RECT 89.052 0.500 89.172 129.100 ;
        RECT 94.452 0.500 94.572 129.100 ;
        RECT 99.852 0.500 99.972 129.100 ;
        RECT 105.252 0.500 105.372 129.100 ;
        RECT 110.652 0.500 110.772 129.100 ;
        RECT 116.052 0.500 116.172 129.100 ;
        RECT 121.452 0.500 121.572 129.100 ;
        RECT 126.852 0.500 126.972 129.100 ;
        RECT 132.252 0.500 132.372 129.100 ;
        RECT 137.652 0.500 137.772 129.100 ;
        RECT 143.052 0.500 143.172 129.100 ;
        RECT 148.452 0.500 148.572 129.100 ;
        RECT 153.852 0.500 153.972 129.100 ;
        RECT 159.252 0.500 159.372 129.100 ;
        RECT 164.652 0.500 164.772 129.100 ;
        RECT 170.052 0.500 170.172 129.100 ;
    END
  END VSS
  OBS
    LAYER M1 ;
      RECT 0.500 0.500 172.300 129.100 ;
    LAYER M2 ;
      RECT 0.500 0.500 172.300 129.100 ;
    LAYER M3 ;
      RECT 10.800 10.800 172.300 118.800 ;
    LAYER M4 ;
      RECT 10.800 10.800 172.300 118.800 ;
    LAYER M5 ;
      RECT 10.800 10.800 13.260 118.800 ;
      RECT 13.380 10.800 13.452 118.800 ;
      RECT 13.572 10.800 18.660 118.800 ;
      RECT 18.780 10.800 18.852 118.800 ;
      RECT 18.972 10.800 24.060 118.800 ;
      RECT 24.180 10.800 24.252 118.800 ;
      RECT 24.372 10.800 29.460 118.800 ;
      RECT 29.580 10.800 29.652 118.800 ;
      RECT 29.772 10.800 34.860 118.800 ;
      RECT 34.980 10.800 35.052 118.800 ;
      RECT 35.172 10.800 40.260 118.800 ;
      RECT 40.380 10.800 40.452 118.800 ;
      RECT 40.572 10.800 45.660 118.800 ;
      RECT 45.780 10.800 45.852 118.800 ;
      RECT 45.972 10.800 51.060 118.800 ;
      RECT 51.180 10.800 51.252 118.800 ;
      RECT 51.372 10.800 56.460 118.800 ;
      RECT 56.580 10.800 56.652 118.800 ;
      RECT 56.772 10.800 61.860 118.800 ;
      RECT 61.980 10.800 62.052 118.800 ;
      RECT 62.172 10.800 67.260 118.800 ;
      RECT 67.380 10.800 67.452 118.800 ;
      RECT 67.572 10.800 72.660 118.800 ;
      RECT 72.780 10.800 72.852 118.800 ;
      RECT 72.972 10.800 78.060 118.800 ;
      RECT 78.180 10.800 78.252 118.800 ;
      RECT 78.372 10.800 83.460 118.800 ;
      RECT 83.580 10.800 83.652 118.800 ;
      RECT 83.772 10.800 88.860 118.800 ;
      RECT 88.980 10.800 89.052 118.800 ;
      RECT 89.172 10.800 94.260 118.800 ;
      RECT 94.380 10.800 94.452 118.800 ;
      RECT 94.572 10.800 99.660 118.800 ;
      RECT 99.780 10.800 99.852 118.800 ;
      RECT 99.972 10.800 105.060 118.800 ;
      RECT 105.180 10.800 105.252 118.800 ;
      RECT 105.372 10.800 110.460 118.800 ;
      RECT 110.580 10.800 110.652 118.800 ;
      RECT 110.772 10.800 115.860 118.800 ;
      RECT 115.980 10.800 116.052 118.800 ;
      RECT 116.172 10.800 121.260 118.800 ;
      RECT 121.380 10.800 121.452 118.800 ;
      RECT 121.572 10.800 126.660 118.800 ;
      RECT 126.780 10.800 126.852 118.800 ;
      RECT 126.972 10.800 132.060 118.800 ;
      RECT 132.180 10.800 132.252 118.800 ;
      RECT 132.372 10.800 137.460 118.800 ;
      RECT 137.580 10.800 137.652 118.800 ;
      RECT 137.772 10.800 142.860 118.800 ;
      RECT 142.980 10.800 143.052 118.800 ;
      RECT 143.172 10.800 148.260 118.800 ;
      RECT 148.380 10.800 148.452 118.800 ;
      RECT 148.572 10.800 153.660 118.800 ;
      RECT 153.780 10.800 153.852 118.800 ;
      RECT 153.972 10.800 159.060 118.800 ;
      RECT 159.180 10.800 159.252 118.800 ;
      RECT 159.372 10.800 164.460 118.800 ;
      RECT 164.580 10.800 164.652 118.800 ;
      RECT 164.772 10.800 169.860 118.800 ;
      RECT 169.980 10.800 170.052 118.800 ;
      RECT 170.172 10.800 172.300 118.800 ;
  END
END qfd_dv_lane_h
END LIBRARY
